VERSION 5.8 ;
BUSBITCHARS "[]" ;
DIVIDERCHAR "/" ;
UNITS
    DATABASE MICRONS 1000 ;
END UNITS

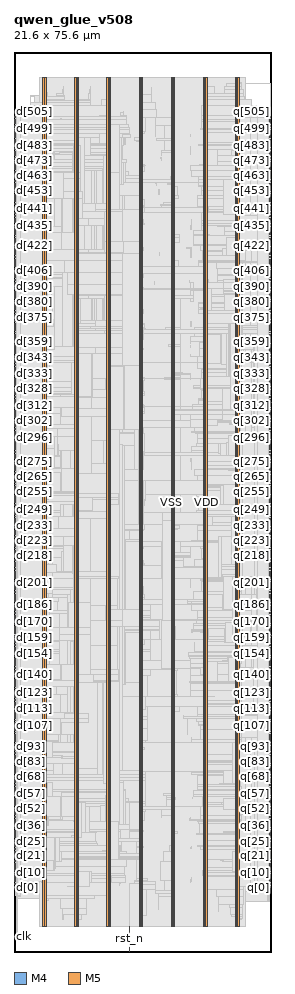
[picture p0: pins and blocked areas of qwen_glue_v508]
MACRO qwen_glue_v508
  FOREIGN qwen_glue_v508 0 0 ;
  CLASS BLOCK ;
  SIZE 21.6 BY 75.6 ;
  PIN clk
    DIRECTION INPUT ;
    USE SIGNAL ;
    PORT
      LAYER M4 ;
        RECT  0.054 1.296 0.138 1.32 ;
    END
    PORT
      LAYER M4 ;
        RECT  0.108 1.296 0.275 1.32 ;
    END
  END clk
  PIN d[0]
    DIRECTION INPUT ;
    USE SIGNAL ;
    PORT
      LAYER M4 ;
        RECT  0.054 5.424 0.138 5.448 ;
    END
  END d[0]
  PIN d[100]
    DIRECTION INPUT ;
    USE SIGNAL ;
    PORT
      LAYER M4 ;
        RECT  0.054 18.192 0.138 18.216 ;
    END
  END d[100]
  PIN d[101]
    DIRECTION INPUT ;
    USE SIGNAL ;
    PORT
      LAYER M4 ;
        RECT  0.054 18.288 0.138 18.312 ;
    END
  END d[101]
  PIN d[102]
    DIRECTION INPUT ;
    USE SIGNAL ;
    PORT
      LAYER M4 ;
        RECT  0.054 18.432 0.138 18.456 ;
    END
  END d[102]
  PIN d[103]
    DIRECTION INPUT ;
    USE SIGNAL ;
    PORT
      LAYER M4 ;
        RECT  0.054 18.576 0.138 18.6 ;
    END
  END d[103]
  PIN d[104]
    DIRECTION INPUT ;
    USE SIGNAL ;
    PORT
      LAYER M4 ;
        RECT  0.054 18.672 0.138 18.696 ;
    END
  END d[104]
  PIN d[105]
    DIRECTION INPUT ;
    USE SIGNAL ;
    PORT
      LAYER M4 ;
        RECT  0.054 18.816 0.138 18.84 ;
    END
  END d[105]
  PIN d[106]
    DIRECTION INPUT ;
    USE SIGNAL ;
    PORT
      LAYER M4 ;
        RECT  0.054 18.912 0.138 18.936 ;
    END
  END d[106]
  PIN d[107]
    DIRECTION INPUT ;
    USE SIGNAL ;
    PORT
      LAYER M4 ;
        RECT  0.054 19.056 0.138 19.08 ;
    END
  END d[107]
  PIN d[108]
    DIRECTION INPUT ;
    USE SIGNAL ;
    PORT
      LAYER M4 ;
        RECT  0.054 19.2 0.138 19.224 ;
    END
  END d[108]
  PIN d[109]
    DIRECTION INPUT ;
    USE SIGNAL ;
    PORT
      LAYER M4 ;
        RECT  0.054 19.296 0.138 19.32 ;
    END
  END d[109]
  PIN d[10]
    DIRECTION INPUT ;
    USE SIGNAL ;
    PORT
      LAYER M4 ;
        RECT  0.054 6.672 0.138 6.696 ;
    END
  END d[10]
  PIN d[110]
    DIRECTION INPUT ;
    USE SIGNAL ;
    PORT
      LAYER M4 ;
        RECT  0.054 19.44 0.138 19.464 ;
    END
  END d[110]
  PIN d[111]
    DIRECTION INPUT ;
    USE SIGNAL ;
    PORT
      LAYER M4 ;
        RECT  0.054 19.584 0.138 19.608 ;
    END
  END d[111]
  PIN d[112]
    DIRECTION INPUT ;
    USE SIGNAL ;
    PORT
      LAYER M4 ;
        RECT  0.054 19.68 0.138 19.704 ;
    END
  END d[112]
  PIN d[113]
    DIRECTION INPUT ;
    USE SIGNAL ;
    PORT
      LAYER M4 ;
        RECT  0.054 19.824 0.138 19.848 ;
    END
  END d[113]
  PIN d[114]
    DIRECTION INPUT ;
    USE SIGNAL ;
    PORT
      LAYER M4 ;
        RECT  0.054 19.968 0.138 19.992 ;
    END
  END d[114]
  PIN d[115]
    DIRECTION INPUT ;
    USE SIGNAL ;
    PORT
      LAYER M4 ;
        RECT  0.054 20.064 0.138 20.088 ;
    END
  END d[115]
  PIN d[116]
    DIRECTION INPUT ;
    USE SIGNAL ;
    PORT
      LAYER M4 ;
        RECT  0.054 20.208 0.138 20.232 ;
    END
  END d[116]
  PIN d[117]
    DIRECTION INPUT ;
    USE SIGNAL ;
    PORT
      LAYER M4 ;
        RECT  0.054 20.352 0.138 20.376 ;
    END
  END d[117]
  PIN d[118]
    DIRECTION INPUT ;
    USE SIGNAL ;
    PORT
      LAYER M4 ;
        RECT  0.054 20.448 0.138 20.472 ;
    END
  END d[118]
  PIN d[119]
    DIRECTION INPUT ;
    USE SIGNAL ;
    PORT
      LAYER M4 ;
        RECT  0.054 20.592 0.138 20.616 ;
    END
  END d[119]
  PIN d[11]
    DIRECTION INPUT ;
    USE SIGNAL ;
    PORT
      LAYER M4 ;
        RECT  0.054 6.816 0.138 6.84 ;
    END
  END d[11]
  PIN d[120]
    DIRECTION INPUT ;
    USE SIGNAL ;
    PORT
      LAYER M4 ;
        RECT  0.054 20.736 0.138 20.76 ;
    END
  END d[120]
  PIN d[121]
    DIRECTION INPUT ;
    USE SIGNAL ;
    PORT
      LAYER M4 ;
        RECT  0.054 20.832 0.138 20.856 ;
    END
  END d[121]
  PIN d[122]
    DIRECTION INPUT ;
    USE SIGNAL ;
    PORT
      LAYER M4 ;
        RECT  0.054 20.976 0.138 21 ;
    END
  END d[122]
  PIN d[123]
    DIRECTION INPUT ;
    USE SIGNAL ;
    PORT
      LAYER M4 ;
        RECT  0.054 21.12 0.138 21.144 ;
    END
  END d[123]
  PIN d[124]
    DIRECTION INPUT ;
    USE SIGNAL ;
    PORT
      LAYER M4 ;
        RECT  0.054 21.216 0.138 21.24 ;
    END
  END d[124]
  PIN d[125]
    DIRECTION INPUT ;
    USE SIGNAL ;
    PORT
      LAYER M4 ;
        RECT  0.054 21.36 0.138 21.384 ;
    END
  END d[125]
  PIN d[126]
    DIRECTION INPUT ;
    USE SIGNAL ;
    PORT
      LAYER M4 ;
        RECT  0.054 21.504 0.138 21.528 ;
    END
  END d[126]
  PIN d[127]
    DIRECTION INPUT ;
    USE SIGNAL ;
    PORT
      LAYER M4 ;
        RECT  0.054 21.6 0.138 21.624 ;
    END
  END d[127]
  PIN d[128]
    DIRECTION INPUT ;
    USE SIGNAL ;
    PORT
      LAYER M4 ;
        RECT  0.054 21.744 0.138 21.768 ;
    END
  END d[128]
  PIN d[129]
    DIRECTION INPUT ;
    USE SIGNAL ;
    PORT
      LAYER M4 ;
        RECT  0.054 21.888 0.138 21.912 ;
    END
  END d[129]
  PIN d[12]
    DIRECTION INPUT ;
    USE SIGNAL ;
    PORT
      LAYER M4 ;
        RECT  0.054 6.912 0.138 6.936 ;
    END
  END d[12]
  PIN d[130]
    DIRECTION INPUT ;
    USE SIGNAL ;
    PORT
      LAYER M4 ;
        RECT  0.054 21.984 0.138 22.008 ;
    END
  END d[130]
  PIN d[131]
    DIRECTION INPUT ;
    USE SIGNAL ;
    PORT
      LAYER M4 ;
        RECT  0.054 22.128 0.138 22.152 ;
    END
  END d[131]
  PIN d[132]
    DIRECTION INPUT ;
    USE SIGNAL ;
    PORT
      LAYER M4 ;
        RECT  0.054 22.272 0.138 22.296 ;
    END
  END d[132]
  PIN d[133]
    DIRECTION INPUT ;
    USE SIGNAL ;
    PORT
      LAYER M4 ;
        RECT  0.054 22.368 0.138 22.392 ;
    END
  END d[133]
  PIN d[134]
    DIRECTION INPUT ;
    USE SIGNAL ;
    PORT
      LAYER M4 ;
        RECT  0.054 22.512 0.138 22.536 ;
    END
  END d[134]
  PIN d[135]
    DIRECTION INPUT ;
    USE SIGNAL ;
    PORT
      LAYER M4 ;
        RECT  0.054 22.656 0.138 22.68 ;
    END
  END d[135]
  PIN d[136]
    DIRECTION INPUT ;
    USE SIGNAL ;
    PORT
      LAYER M4 ;
        RECT  0.054 22.752 0.138 22.776 ;
    END
  END d[136]
  PIN d[137]
    DIRECTION INPUT ;
    USE SIGNAL ;
    PORT
      LAYER M4 ;
        RECT  0.054 22.896 0.138 22.92 ;
    END
  END d[137]
  PIN d[138]
    DIRECTION INPUT ;
    USE SIGNAL ;
    PORT
      LAYER M4 ;
        RECT  0.054 23.04 0.138 23.064 ;
    END
  END d[138]
  PIN d[139]
    DIRECTION INPUT ;
    USE SIGNAL ;
    PORT
      LAYER M4 ;
        RECT  0.054 23.136 0.138 23.16 ;
    END
  END d[139]
  PIN d[13]
    DIRECTION INPUT ;
    USE SIGNAL ;
    PORT
      LAYER M4 ;
        RECT  0.054 7.056 0.138 7.08 ;
    END
  END d[13]
  PIN d[140]
    DIRECTION INPUT ;
    USE SIGNAL ;
    PORT
      LAYER M4 ;
        RECT  0.054 23.28 0.138 23.304 ;
    END
  END d[140]
  PIN d[141]
    DIRECTION INPUT ;
    USE SIGNAL ;
    PORT
      LAYER M4 ;
        RECT  0.054 23.424 0.138 23.448 ;
    END
  END d[141]
  PIN d[142]
    DIRECTION INPUT ;
    USE SIGNAL ;
    PORT
      LAYER M4 ;
        RECT  0.054 23.52 0.138 23.544 ;
    END
  END d[142]
  PIN d[143]
    DIRECTION INPUT ;
    USE SIGNAL ;
    PORT
      LAYER M4 ;
        RECT  0.054 23.664 0.138 23.688 ;
    END
  END d[143]
  PIN d[144]
    DIRECTION INPUT ;
    USE SIGNAL ;
    PORT
      LAYER M4 ;
        RECT  0.054 23.808 0.138 23.832 ;
    END
  END d[144]
  PIN d[145]
    DIRECTION INPUT ;
    USE SIGNAL ;
    PORT
      LAYER M4 ;
        RECT  0.054 23.904 0.138 23.928 ;
    END
  END d[145]
  PIN d[146]
    DIRECTION INPUT ;
    USE SIGNAL ;
    PORT
      LAYER M4 ;
        RECT  0.054 24.048 0.138 24.072 ;
    END
  END d[146]
  PIN d[147]
    DIRECTION INPUT ;
    USE SIGNAL ;
    PORT
      LAYER M4 ;
        RECT  0.054 24.192 0.138 24.216 ;
    END
  END d[147]
  PIN d[148]
    DIRECTION INPUT ;
    USE SIGNAL ;
    PORT
      LAYER M4 ;
        RECT  0.054 24.288 0.138 24.312 ;
    END
  END d[148]
  PIN d[149]
    DIRECTION INPUT ;
    USE SIGNAL ;
    PORT
      LAYER M4 ;
        RECT  0.054 24.432 0.138 24.456 ;
    END
  END d[149]
  PIN d[14]
    DIRECTION INPUT ;
    USE SIGNAL ;
    PORT
      LAYER M4 ;
        RECT  0.054 7.2 0.138 7.224 ;
    END
  END d[14]
  PIN d[150]
    DIRECTION INPUT ;
    USE SIGNAL ;
    PORT
      LAYER M4 ;
        RECT  0.054 24.576 0.138 24.6 ;
    END
  END d[150]
  PIN d[151]
    DIRECTION INPUT ;
    USE SIGNAL ;
    PORT
      LAYER M4 ;
        RECT  0.054 24.672 0.138 24.696 ;
    END
  END d[151]
  PIN d[152]
    DIRECTION INPUT ;
    USE SIGNAL ;
    PORT
      LAYER M4 ;
        RECT  0.054 24.816 0.138 24.84 ;
    END
  END d[152]
  PIN d[153]
    DIRECTION INPUT ;
    USE SIGNAL ;
    PORT
      LAYER M4 ;
        RECT  0.054 24.96 0.138 24.984 ;
    END
  END d[153]
  PIN d[154]
    DIRECTION INPUT ;
    USE SIGNAL ;
    PORT
      LAYER M4 ;
        RECT  0.054 25.056 0.138 25.08 ;
    END
  END d[154]
  PIN d[155]
    DIRECTION INPUT ;
    USE SIGNAL ;
    PORT
      LAYER M4 ;
        RECT  0.054 25.2 0.138 25.224 ;
    END
  END d[155]
  PIN d[156]
    DIRECTION INPUT ;
    USE SIGNAL ;
    PORT
      LAYER M4 ;
        RECT  0.054 25.344 0.138 25.368 ;
    END
  END d[156]
  PIN d[157]
    DIRECTION INPUT ;
    USE SIGNAL ;
    PORT
      LAYER M4 ;
        RECT  0.054 25.44 0.138 25.464 ;
    END
  END d[157]
  PIN d[158]
    DIRECTION INPUT ;
    USE SIGNAL ;
    PORT
      LAYER M4 ;
        RECT  0.054 25.584 0.138 25.608 ;
    END
  END d[158]
  PIN d[159]
    DIRECTION INPUT ;
    USE SIGNAL ;
    PORT
      LAYER M4 ;
        RECT  0.054 25.728 0.138 25.752 ;
    END
  END d[159]
  PIN d[15]
    DIRECTION INPUT ;
    USE SIGNAL ;
    PORT
      LAYER M4 ;
        RECT  0.054 7.296 0.138 7.32 ;
    END
  END d[15]
  PIN d[160]
    DIRECTION INPUT ;
    USE SIGNAL ;
    PORT
      LAYER M4 ;
        RECT  0.054 25.824 0.138 25.848 ;
    END
  END d[160]
  PIN d[161]
    DIRECTION INPUT ;
    USE SIGNAL ;
    PORT
      LAYER M4 ;
        RECT  0.054 25.968 0.138 25.992 ;
    END
  END d[161]
  PIN d[162]
    DIRECTION INPUT ;
    USE SIGNAL ;
    PORT
      LAYER M4 ;
        RECT  0.054 26.112 0.138 26.136 ;
    END
  END d[162]
  PIN d[163]
    DIRECTION INPUT ;
    USE SIGNAL ;
    PORT
      LAYER M4 ;
        RECT  0.054 26.208 0.138 26.232 ;
    END
  END d[163]
  PIN d[164]
    DIRECTION INPUT ;
    USE SIGNAL ;
    PORT
      LAYER M4 ;
        RECT  0.054 26.352 0.138 26.376 ;
    END
  END d[164]
  PIN d[165]
    DIRECTION INPUT ;
    USE SIGNAL ;
    PORT
      LAYER M4 ;
        RECT  0.054 26.496 0.138 26.52 ;
    END
  END d[165]
  PIN d[166]
    DIRECTION INPUT ;
    USE SIGNAL ;
    PORT
      LAYER M4 ;
        RECT  0.054 26.592 0.138 26.616 ;
    END
    PORT
      LAYER M4 ;
        RECT  0.025 26.592 0.108 26.616 ;
    END
  END d[166]
  PIN d[167]
    DIRECTION INPUT ;
    USE SIGNAL ;
    PORT
      LAYER M4 ;
        RECT  0.054 26.736 0.138 26.76 ;
    END
  END d[167]
  PIN d[168]
    DIRECTION INPUT ;
    USE SIGNAL ;
    PORT
      LAYER M4 ;
        RECT  0.054 26.88 0.138 26.904 ;
    END
  END d[168]
  PIN d[169]
    DIRECTION INPUT ;
    USE SIGNAL ;
    PORT
      LAYER M4 ;
        RECT  0.054 26.976 0.138 27 ;
    END
  END d[169]
  PIN d[16]
    DIRECTION INPUT ;
    USE SIGNAL ;
    PORT
      LAYER M4 ;
        RECT  0.054 7.44 0.138 7.464 ;
    END
  END d[16]
  PIN d[170]
    DIRECTION INPUT ;
    USE SIGNAL ;
    PORT
      LAYER M4 ;
        RECT  0.054 27.12 0.138 27.144 ;
    END
  END d[170]
  PIN d[171]
    DIRECTION INPUT ;
    USE SIGNAL ;
    PORT
      LAYER M4 ;
        RECT  0.054 27.264 0.138 27.288 ;
    END
  END d[171]
  PIN d[172]
    DIRECTION INPUT ;
    USE SIGNAL ;
    PORT
      LAYER M4 ;
        RECT  0.054 27.36 0.138 27.384 ;
    END
  END d[172]
  PIN d[173]
    DIRECTION INPUT ;
    USE SIGNAL ;
    PORT
      LAYER M4 ;
        RECT  0.054 27.504 0.138 27.528 ;
    END
  END d[173]
  PIN d[174]
    DIRECTION INPUT ;
    USE SIGNAL ;
    PORT
      LAYER M4 ;
        RECT  0.054 27.648 0.138 27.672 ;
    END
  END d[174]
  PIN d[175]
    DIRECTION INPUT ;
    USE SIGNAL ;
    PORT
      LAYER M4 ;
        RECT  0.054 27.744 0.138 27.768 ;
    END
  END d[175]
  PIN d[176]
    DIRECTION INPUT ;
    USE SIGNAL ;
    PORT
      LAYER M4 ;
        RECT  0.054 27.888 0.138 27.912 ;
    END
  END d[176]
  PIN d[177]
    DIRECTION INPUT ;
    USE SIGNAL ;
    PORT
      LAYER M4 ;
        RECT  0.054 28.032 0.138 28.056 ;
    END
  END d[177]
  PIN d[178]
    DIRECTION INPUT ;
    USE SIGNAL ;
    PORT
      LAYER M4 ;
        RECT  0.054 28.128 0.138 28.152 ;
    END
  END d[178]
  PIN d[179]
    DIRECTION INPUT ;
    USE SIGNAL ;
    PORT
      LAYER M4 ;
        RECT  0.054 28.272 0.138 28.296 ;
    END
  END d[179]
  PIN d[17]
    DIRECTION INPUT ;
    USE SIGNAL ;
    PORT
      LAYER M4 ;
        RECT  0.054 7.584 0.138 7.608 ;
    END
  END d[17]
  PIN d[180]
    DIRECTION INPUT ;
    USE SIGNAL ;
    PORT
      LAYER M4 ;
        RECT  0.054 28.416 0.138 28.44 ;
    END
  END d[180]
  PIN d[181]
    DIRECTION INPUT ;
    USE SIGNAL ;
    PORT
      LAYER M4 ;
        RECT  0.054 28.512 0.138 28.536 ;
    END
  END d[181]
  PIN d[182]
    DIRECTION INPUT ;
    USE SIGNAL ;
    PORT
      LAYER M4 ;
        RECT  0.054 28.656 0.138 28.68 ;
    END
  END d[182]
  PIN d[183]
    DIRECTION INPUT ;
    USE SIGNAL ;
    PORT
      LAYER M4 ;
        RECT  0.054 28.8 0.138 28.824 ;
    END
  END d[183]
  PIN d[184]
    DIRECTION INPUT ;
    USE SIGNAL ;
    PORT
      LAYER M4 ;
        RECT  0.054 28.896 0.138 28.92 ;
    END
  END d[184]
  PIN d[185]
    DIRECTION INPUT ;
    USE SIGNAL ;
    PORT
      LAYER M4 ;
        RECT  0.054 29.04 0.138 29.064 ;
    END
  END d[185]
  PIN d[186]
    DIRECTION INPUT ;
    USE SIGNAL ;
    PORT
      LAYER M4 ;
        RECT  0.054 29.184 0.138 29.208 ;
    END
  END d[186]
  PIN d[187]
    DIRECTION INPUT ;
    USE SIGNAL ;
    PORT
      LAYER M4 ;
        RECT  0.054 29.28 0.138 29.304 ;
    END
  END d[187]
  PIN d[188]
    DIRECTION INPUT ;
    USE SIGNAL ;
    PORT
      LAYER M4 ;
        RECT  0.054 29.424 0.138 29.448 ;
    END
  END d[188]
  PIN d[189]
    DIRECTION INPUT ;
    USE SIGNAL ;
    PORT
      LAYER M4 ;
        RECT  0.054 29.568 0.138 29.592 ;
    END
  END d[189]
  PIN d[18]
    DIRECTION INPUT ;
    USE SIGNAL ;
    PORT
      LAYER M4 ;
        RECT  0.054 7.68 0.138 7.704 ;
    END
  END d[18]
  PIN d[190]
    DIRECTION INPUT ;
    USE SIGNAL ;
    PORT
      LAYER M4 ;
        RECT  0.054 29.664 0.138 29.688 ;
    END
  END d[190]
  PIN d[191]
    DIRECTION INPUT ;
    USE SIGNAL ;
    PORT
      LAYER M4 ;
        RECT  0.054 29.808 0.138 29.832 ;
    END
  END d[191]
  PIN d[192]
    DIRECTION INPUT ;
    USE SIGNAL ;
    PORT
      LAYER M4 ;
        RECT  0.054 29.904 0.138 29.928 ;
    END
  END d[192]
  PIN d[193]
    DIRECTION INPUT ;
    USE SIGNAL ;
    PORT
      LAYER M4 ;
        RECT  0.054 30.048 0.138 30.072 ;
    END
  END d[193]
  PIN d[194]
    DIRECTION INPUT ;
    USE SIGNAL ;
    PORT
      LAYER M4 ;
        RECT  0.054 30.192 0.138 30.216 ;
    END
  END d[194]
  PIN d[195]
    DIRECTION INPUT ;
    USE SIGNAL ;
    PORT
      LAYER M4 ;
        RECT  0.054 30.288 0.138 30.312 ;
    END
  END d[195]
  PIN d[196]
    DIRECTION INPUT ;
    USE SIGNAL ;
    PORT
      LAYER M4 ;
        RECT  0.054 30.432 0.138 30.456 ;
    END
  END d[196]
  PIN d[197]
    DIRECTION INPUT ;
    USE SIGNAL ;
    PORT
      LAYER M4 ;
        RECT  0.054 30.576 0.138 30.6 ;
    END
  END d[197]
  PIN d[198]
    DIRECTION INPUT ;
    USE SIGNAL ;
    PORT
      LAYER M4 ;
        RECT  0.054 30.672 0.138 30.696 ;
    END
  END d[198]
  PIN d[199]
    DIRECTION INPUT ;
    USE SIGNAL ;
    PORT
      LAYER M4 ;
        RECT  0.054 30.816 0.138 30.84 ;
    END
  END d[199]
  PIN d[19]
    DIRECTION INPUT ;
    USE SIGNAL ;
    PORT
      LAYER M4 ;
        RECT  0.054 7.824 0.138 7.848 ;
    END
  END d[19]
  PIN d[1]
    DIRECTION INPUT ;
    USE SIGNAL ;
    PORT
      LAYER M4 ;
        RECT  0.054 5.52 0.138 5.544 ;
    END
  END d[1]
  PIN d[200]
    DIRECTION INPUT ;
    USE SIGNAL ;
    PORT
      LAYER M4 ;
        RECT  0.054 30.96 0.138 30.984 ;
    END
  END d[200]
  PIN d[201]
    DIRECTION INPUT ;
    USE SIGNAL ;
    PORT
      LAYER M4 ;
        RECT  0.054 31.056 0.138 31.08 ;
    END
  END d[201]
  PIN d[202]
    DIRECTION INPUT ;
    USE SIGNAL ;
    PORT
      LAYER M4 ;
        RECT  0.054 31.2 0.138 31.224 ;
    END
  END d[202]
  PIN d[203]
    DIRECTION INPUT ;
    USE SIGNAL ;
    PORT
      LAYER M4 ;
        RECT  0.054 31.344 0.138 31.368 ;
    END
  END d[203]
  PIN d[204]
    DIRECTION INPUT ;
    USE SIGNAL ;
    PORT
      LAYER M4 ;
        RECT  0.054 31.44 0.138 31.464 ;
    END
  END d[204]
  PIN d[205]
    DIRECTION INPUT ;
    USE SIGNAL ;
    PORT
      LAYER M4 ;
        RECT  0.054 31.584 0.138 31.608 ;
    END
  END d[205]
  PIN d[206]
    DIRECTION INPUT ;
    USE SIGNAL ;
    PORT
      LAYER M4 ;
        RECT  0.054 31.728 0.138 31.752 ;
    END
  END d[206]
  PIN d[207]
    DIRECTION INPUT ;
    USE SIGNAL ;
    PORT
      LAYER M4 ;
        RECT  0.054 31.824 0.138 31.848 ;
    END
  END d[207]
  PIN d[208]
    DIRECTION INPUT ;
    USE SIGNAL ;
    PORT
      LAYER M4 ;
        RECT  0.054 31.968 0.138 31.992 ;
    END
  END d[208]
  PIN d[209]
    DIRECTION INPUT ;
    USE SIGNAL ;
    PORT
      LAYER M4 ;
        RECT  0.054 32.112 0.138 32.136 ;
    END
  END d[209]
  PIN d[20]
    DIRECTION INPUT ;
    USE SIGNAL ;
    PORT
      LAYER M4 ;
        RECT  0.054 7.968 0.138 7.992 ;
    END
  END d[20]
  PIN d[210]
    DIRECTION INPUT ;
    USE SIGNAL ;
    PORT
      LAYER M4 ;
        RECT  0.054 32.208 0.138 32.232 ;
    END
  END d[210]
  PIN d[211]
    DIRECTION INPUT ;
    USE SIGNAL ;
    PORT
      LAYER M4 ;
        RECT  0.054 32.352 0.138 32.376 ;
    END
  END d[211]
  PIN d[212]
    DIRECTION INPUT ;
    USE SIGNAL ;
    PORT
      LAYER M4 ;
        RECT  0.054 32.496 0.138 32.52 ;
    END
  END d[212]
  PIN d[213]
    DIRECTION INPUT ;
    USE SIGNAL ;
    PORT
      LAYER M4 ;
        RECT  0.054 32.592 0.138 32.616 ;
    END
  END d[213]
  PIN d[214]
    DIRECTION INPUT ;
    USE SIGNAL ;
    PORT
      LAYER M4 ;
        RECT  0.054 32.736 0.138 32.76 ;
    END
  END d[214]
  PIN d[215]
    DIRECTION INPUT ;
    USE SIGNAL ;
    PORT
      LAYER M4 ;
        RECT  0.054 32.88 0.138 32.904 ;
    END
  END d[215]
  PIN d[216]
    DIRECTION INPUT ;
    USE SIGNAL ;
    PORT
      LAYER M4 ;
        RECT  0.054 32.976 0.138 33 ;
    END
  END d[216]
  PIN d[217]
    DIRECTION INPUT ;
    USE SIGNAL ;
    PORT
      LAYER M4 ;
        RECT  0.054 33.12 0.138 33.144 ;
    END
  END d[217]
  PIN d[218]
    DIRECTION INPUT ;
    USE SIGNAL ;
    PORT
      LAYER M4 ;
        RECT  0.054 33.264 0.138 33.288 ;
    END
  END d[218]
  PIN d[219]
    DIRECTION INPUT ;
    USE SIGNAL ;
    PORT
      LAYER M4 ;
        RECT  0.054 33.36 0.138 33.384 ;
    END
  END d[219]
  PIN d[21]
    DIRECTION INPUT ;
    USE SIGNAL ;
    PORT
      LAYER M4 ;
        RECT  0.054 8.064 0.138 8.088 ;
    END
  END d[21]
  PIN d[220]
    DIRECTION INPUT ;
    USE SIGNAL ;
    PORT
      LAYER M4 ;
        RECT  0.054 33.504 0.138 33.528 ;
    END
    PORT
      LAYER M4 ;
        RECT  0.025 33.504 0.108 33.528 ;
    END
  END d[220]
  PIN d[221]
    DIRECTION INPUT ;
    USE SIGNAL ;
    PORT
      LAYER M4 ;
        RECT  0.054 33.648 0.138 33.672 ;
    END
  END d[221]
  PIN d[222]
    DIRECTION INPUT ;
    USE SIGNAL ;
    PORT
      LAYER M4 ;
        RECT  0.054 33.744 0.138 33.768 ;
    END
  END d[222]
  PIN d[223]
    DIRECTION INPUT ;
    USE SIGNAL ;
    PORT
      LAYER M4 ;
        RECT  0.054 33.888 0.138 33.912 ;
    END
  END d[223]
  PIN d[224]
    DIRECTION INPUT ;
    USE SIGNAL ;
    PORT
      LAYER M4 ;
        RECT  0.054 34.032 0.138 34.056 ;
    END
  END d[224]
  PIN d[225]
    DIRECTION INPUT ;
    USE SIGNAL ;
    PORT
      LAYER M4 ;
        RECT  0.054 34.128 0.138 34.152 ;
    END
  END d[225]
  PIN d[226]
    DIRECTION INPUT ;
    USE SIGNAL ;
    PORT
      LAYER M4 ;
        RECT  0.054 34.272 0.138 34.296 ;
    END
  END d[226]
  PIN d[227]
    DIRECTION INPUT ;
    USE SIGNAL ;
    PORT
      LAYER M4 ;
        RECT  0.054 34.416 0.138 34.44 ;
    END
  END d[227]
  PIN d[228]
    DIRECTION INPUT ;
    USE SIGNAL ;
    PORT
      LAYER M4 ;
        RECT  0.054 34.512 0.138 34.536 ;
    END
  END d[228]
  PIN d[229]
    DIRECTION INPUT ;
    USE SIGNAL ;
    PORT
      LAYER M4 ;
        RECT  0.054 34.656 0.138 34.68 ;
    END
  END d[229]
  PIN d[22]
    DIRECTION INPUT ;
    USE SIGNAL ;
    PORT
      LAYER M4 ;
        RECT  0.054 8.208 0.138 8.232 ;
    END
  END d[22]
  PIN d[230]
    DIRECTION INPUT ;
    USE SIGNAL ;
    PORT
      LAYER M4 ;
        RECT  0.054 34.8 0.138 34.824 ;
    END
  END d[230]
  PIN d[231]
    DIRECTION INPUT ;
    USE SIGNAL ;
    PORT
      LAYER M4 ;
        RECT  0.054 34.896 0.138 34.92 ;
    END
  END d[231]
  PIN d[232]
    DIRECTION INPUT ;
    USE SIGNAL ;
    PORT
      LAYER M4 ;
        RECT  0.054 35.04 0.138 35.064 ;
    END
  END d[232]
  PIN d[233]
    DIRECTION INPUT ;
    USE SIGNAL ;
    PORT
      LAYER M4 ;
        RECT  0.054 35.184 0.138 35.208 ;
    END
  END d[233]
  PIN d[234]
    DIRECTION INPUT ;
    USE SIGNAL ;
    PORT
      LAYER M4 ;
        RECT  0.054 35.28 0.138 35.304 ;
    END
  END d[234]
  PIN d[235]
    DIRECTION INPUT ;
    USE SIGNAL ;
    PORT
      LAYER M4 ;
        RECT  0.054 35.424 0.138 35.448 ;
    END
  END d[235]
  PIN d[236]
    DIRECTION INPUT ;
    USE SIGNAL ;
    PORT
      LAYER M4 ;
        RECT  0.054 35.568 0.138 35.592 ;
    END
  END d[236]
  PIN d[237]
    DIRECTION INPUT ;
    USE SIGNAL ;
    PORT
      LAYER M4 ;
        RECT  0.054 35.664 0.138 35.688 ;
    END
  END d[237]
  PIN d[238]
    DIRECTION INPUT ;
    USE SIGNAL ;
    PORT
      LAYER M4 ;
        RECT  0.054 35.808 0.138 35.832 ;
    END
  END d[238]
  PIN d[239]
    DIRECTION INPUT ;
    USE SIGNAL ;
    PORT
      LAYER M4 ;
        RECT  0.054 35.952 0.138 35.976 ;
    END
  END d[239]
  PIN d[23]
    DIRECTION INPUT ;
    USE SIGNAL ;
    PORT
      LAYER M4 ;
        RECT  0.054 8.304 0.138 8.328 ;
    END
  END d[23]
  PIN d[240]
    DIRECTION INPUT ;
    USE SIGNAL ;
    PORT
      LAYER M4 ;
        RECT  0.054 36.048 0.138 36.072 ;
    END
  END d[240]
  PIN d[241]
    DIRECTION INPUT ;
    USE SIGNAL ;
    PORT
      LAYER M4 ;
        RECT  0.054 36.192 0.138 36.216 ;
    END
  END d[241]
  PIN d[242]
    DIRECTION INPUT ;
    USE SIGNAL ;
    PORT
      LAYER M4 ;
        RECT  0.054 36.336 0.138 36.36 ;
    END
  END d[242]
  PIN d[243]
    DIRECTION INPUT ;
    USE SIGNAL ;
    PORT
      LAYER M4 ;
        RECT  0.054 36.432 0.138 36.456 ;
    END
  END d[243]
  PIN d[244]
    DIRECTION INPUT ;
    USE SIGNAL ;
    PORT
      LAYER M4 ;
        RECT  0.054 36.576 0.138 36.6 ;
    END
  END d[244]
  PIN d[245]
    DIRECTION INPUT ;
    USE SIGNAL ;
    PORT
      LAYER M4 ;
        RECT  0.054 36.72 0.138 36.744 ;
    END
  END d[245]
  PIN d[246]
    DIRECTION INPUT ;
    USE SIGNAL ;
    PORT
      LAYER M4 ;
        RECT  0.054 36.816 0.138 36.84 ;
    END
  END d[246]
  PIN d[247]
    DIRECTION INPUT ;
    USE SIGNAL ;
    PORT
      LAYER M4 ;
        RECT  0.054 36.96 0.138 36.984 ;
    END
  END d[247]
  PIN d[248]
    DIRECTION INPUT ;
    USE SIGNAL ;
    PORT
      LAYER M4 ;
        RECT  0.054 37.104 0.138 37.128 ;
    END
  END d[248]
  PIN d[249]
    DIRECTION INPUT ;
    USE SIGNAL ;
    PORT
      LAYER M4 ;
        RECT  0.054 37.2 0.138 37.224 ;
    END
  END d[249]
  PIN d[24]
    DIRECTION INPUT ;
    USE SIGNAL ;
    PORT
      LAYER M4 ;
        RECT  0.054 8.448 0.138 8.472 ;
    END
  END d[24]
  PIN d[250]
    DIRECTION INPUT ;
    USE SIGNAL ;
    PORT
      LAYER M4 ;
        RECT  0.054 37.344 0.138 37.368 ;
    END
  END d[250]
  PIN d[251]
    DIRECTION INPUT ;
    USE SIGNAL ;
    PORT
      LAYER M4 ;
        RECT  0.054 37.488 0.138 37.512 ;
    END
  END d[251]
  PIN d[252]
    DIRECTION INPUT ;
    USE SIGNAL ;
    PORT
      LAYER M4 ;
        RECT  0.054 37.584 0.138 37.608 ;
    END
  END d[252]
  PIN d[253]
    DIRECTION INPUT ;
    USE SIGNAL ;
    PORT
      LAYER M4 ;
        RECT  0.054 37.728 0.138 37.752 ;
    END
  END d[253]
  PIN d[254]
    DIRECTION INPUT ;
    USE SIGNAL ;
    PORT
      LAYER M4 ;
        RECT  0.054 37.872 0.138 37.896 ;
    END
  END d[254]
  PIN d[255]
    DIRECTION INPUT ;
    USE SIGNAL ;
    PORT
      LAYER M4 ;
        RECT  0.054 37.968 0.138 37.992 ;
    END
  END d[255]
  PIN d[256]
    DIRECTION INPUT ;
    USE SIGNAL ;
    PORT
      LAYER M4 ;
        RECT  0.054 38.112 0.138 38.136 ;
    END
  END d[256]
  PIN d[257]
    DIRECTION INPUT ;
    USE SIGNAL ;
    PORT
      LAYER M4 ;
        RECT  0.054 38.256 0.138 38.28 ;
    END
  END d[257]
  PIN d[258]
    DIRECTION INPUT ;
    USE SIGNAL ;
    PORT
      LAYER M4 ;
        RECT  0.054 38.352 0.138 38.376 ;
    END
  END d[258]
  PIN d[259]
    DIRECTION INPUT ;
    USE SIGNAL ;
    PORT
      LAYER M4 ;
        RECT  0.054 38.496 0.138 38.52 ;
    END
  END d[259]
  PIN d[25]
    DIRECTION INPUT ;
    USE SIGNAL ;
    PORT
      LAYER M4 ;
        RECT  0.054 8.592 0.138 8.616 ;
    END
  END d[25]
  PIN d[260]
    DIRECTION INPUT ;
    USE SIGNAL ;
    PORT
      LAYER M4 ;
        RECT  0.054 38.64 0.138 38.664 ;
    END
  END d[260]
  PIN d[261]
    DIRECTION INPUT ;
    USE SIGNAL ;
    PORT
      LAYER M4 ;
        RECT  0.054 38.736 0.138 38.76 ;
    END
  END d[261]
  PIN d[262]
    DIRECTION INPUT ;
    USE SIGNAL ;
    PORT
      LAYER M4 ;
        RECT  0.054 38.88 0.138 38.904 ;
    END
  END d[262]
  PIN d[263]
    DIRECTION INPUT ;
    USE SIGNAL ;
    PORT
      LAYER M4 ;
        RECT  0.054 39.024 0.138 39.048 ;
    END
  END d[263]
  PIN d[264]
    DIRECTION INPUT ;
    USE SIGNAL ;
    PORT
      LAYER M4 ;
        RECT  0.054 39.12 0.138 39.144 ;
    END
  END d[264]
  PIN d[265]
    DIRECTION INPUT ;
    USE SIGNAL ;
    PORT
      LAYER M4 ;
        RECT  0.054 39.264 0.138 39.288 ;
    END
  END d[265]
  PIN d[266]
    DIRECTION INPUT ;
    USE SIGNAL ;
    PORT
      LAYER M4 ;
        RECT  0.054 39.408 0.138 39.432 ;
    END
  END d[266]
  PIN d[267]
    DIRECTION INPUT ;
    USE SIGNAL ;
    PORT
      LAYER M4 ;
        RECT  0.054 39.504 0.138 39.528 ;
    END
  END d[267]
  PIN d[268]
    DIRECTION INPUT ;
    USE SIGNAL ;
    PORT
      LAYER M4 ;
        RECT  0.054 39.648 0.138 39.672 ;
    END
  END d[268]
  PIN d[269]
    DIRECTION INPUT ;
    USE SIGNAL ;
    PORT
      LAYER M4 ;
        RECT  0.054 39.792 0.138 39.816 ;
    END
  END d[269]
  PIN d[26]
    DIRECTION INPUT ;
    USE SIGNAL ;
    PORT
      LAYER M4 ;
        RECT  0.054 8.688 0.138 8.712 ;
    END
  END d[26]
  PIN d[270]
    DIRECTION INPUT ;
    USE SIGNAL ;
    PORT
      LAYER M4 ;
        RECT  0.054 39.888 0.138 39.912 ;
    END
  END d[270]
  PIN d[271]
    DIRECTION INPUT ;
    USE SIGNAL ;
    PORT
      LAYER M4 ;
        RECT  0.054 40.032 0.138 40.056 ;
    END
  END d[271]
  PIN d[272]
    DIRECTION INPUT ;
    USE SIGNAL ;
    PORT
      LAYER M4 ;
        RECT  0.054 40.176 0.138 40.2 ;
    END
  END d[272]
  PIN d[273]
    DIRECTION INPUT ;
    USE SIGNAL ;
    PORT
      LAYER M4 ;
        RECT  0.054 40.272 0.138 40.296 ;
    END
  END d[273]
  PIN d[274]
    DIRECTION INPUT ;
    USE SIGNAL ;
    PORT
      LAYER M4 ;
        RECT  0.054 40.416 0.138 40.44 ;
    END
  END d[274]
  PIN d[275]
    DIRECTION INPUT ;
    USE SIGNAL ;
    PORT
      LAYER M4 ;
        RECT  0.054 40.512 0.138 40.536 ;
    END
  END d[275]
  PIN d[276]
    DIRECTION INPUT ;
    USE SIGNAL ;
    PORT
      LAYER M4 ;
        RECT  0.054 40.656 0.138 40.68 ;
    END
  END d[276]
  PIN d[277]
    DIRECTION INPUT ;
    USE SIGNAL ;
    PORT
      LAYER M4 ;
        RECT  0.054 40.8 0.138 40.824 ;
    END
  END d[277]
  PIN d[278]
    DIRECTION INPUT ;
    USE SIGNAL ;
    PORT
      LAYER M4 ;
        RECT  0.054 40.896 0.138 40.92 ;
    END
  END d[278]
  PIN d[279]
    DIRECTION INPUT ;
    USE SIGNAL ;
    PORT
      LAYER M4 ;
        RECT  0.054 41.04 0.138 41.064 ;
    END
  END d[279]
  PIN d[27]
    DIRECTION INPUT ;
    USE SIGNAL ;
    PORT
      LAYER M4 ;
        RECT  0.054 8.832 0.138 8.856 ;
    END
  END d[27]
  PIN d[280]
    DIRECTION INPUT ;
    USE SIGNAL ;
    PORT
      LAYER M4 ;
        RECT  0.054 41.184 0.138 41.208 ;
    END
  END d[280]
  PIN d[281]
    DIRECTION INPUT ;
    USE SIGNAL ;
    PORT
      LAYER M4 ;
        RECT  0.054 41.28 0.138 41.304 ;
    END
  END d[281]
  PIN d[282]
    DIRECTION INPUT ;
    USE SIGNAL ;
    PORT
      LAYER M4 ;
        RECT  0.054 41.424 0.138 41.448 ;
    END
  END d[282]
  PIN d[283]
    DIRECTION INPUT ;
    USE SIGNAL ;
    PORT
      LAYER M4 ;
        RECT  0.054 41.568 0.138 41.592 ;
    END
  END d[283]
  PIN d[284]
    DIRECTION INPUT ;
    USE SIGNAL ;
    PORT
      LAYER M4 ;
        RECT  0.054 41.664 0.138 41.688 ;
    END
  END d[284]
  PIN d[285]
    DIRECTION INPUT ;
    USE SIGNAL ;
    PORT
      LAYER M4 ;
        RECT  0.054 41.808 0.138 41.832 ;
    END
  END d[285]
  PIN d[286]
    DIRECTION INPUT ;
    USE SIGNAL ;
    PORT
      LAYER M4 ;
        RECT  0.054 41.952 0.138 41.976 ;
    END
  END d[286]
  PIN d[287]
    DIRECTION INPUT ;
    USE SIGNAL ;
    PORT
      LAYER M4 ;
        RECT  0.054 42.048 0.138 42.072 ;
    END
  END d[287]
  PIN d[288]
    DIRECTION INPUT ;
    USE SIGNAL ;
    PORT
      LAYER M4 ;
        RECT  0.054 42.192 0.138 42.216 ;
    END
  END d[288]
  PIN d[289]
    DIRECTION INPUT ;
    USE SIGNAL ;
    PORT
      LAYER M4 ;
        RECT  0.054 42.336 0.138 42.36 ;
    END
  END d[289]
  PIN d[28]
    DIRECTION INPUT ;
    USE SIGNAL ;
    PORT
      LAYER M4 ;
        RECT  0.054 8.976 0.138 9 ;
    END
  END d[28]
  PIN d[290]
    DIRECTION INPUT ;
    USE SIGNAL ;
    PORT
      LAYER M4 ;
        RECT  0.054 42.432 0.138 42.456 ;
    END
  END d[290]
  PIN d[291]
    DIRECTION INPUT ;
    USE SIGNAL ;
    PORT
      LAYER M4 ;
        RECT  0.054 42.576 0.138 42.6 ;
    END
  END d[291]
  PIN d[292]
    DIRECTION INPUT ;
    USE SIGNAL ;
    PORT
      LAYER M4 ;
        RECT  0.054 42.72 0.138 42.744 ;
    END
  END d[292]
  PIN d[293]
    DIRECTION INPUT ;
    USE SIGNAL ;
    PORT
      LAYER M4 ;
        RECT  0.054 42.816 0.138 42.84 ;
    END
  END d[293]
  PIN d[294]
    DIRECTION INPUT ;
    USE SIGNAL ;
    PORT
      LAYER M4 ;
        RECT  0.054 42.96 0.138 42.984 ;
    END
  END d[294]
  PIN d[295]
    DIRECTION INPUT ;
    USE SIGNAL ;
    PORT
      LAYER M4 ;
        RECT  0.054 43.104 0.138 43.128 ;
    END
  END d[295]
  PIN d[296]
    DIRECTION INPUT ;
    USE SIGNAL ;
    PORT
      LAYER M4 ;
        RECT  0.054 43.2 0.138 43.224 ;
    END
  END d[296]
  PIN d[297]
    DIRECTION INPUT ;
    USE SIGNAL ;
    PORT
      LAYER M4 ;
        RECT  0.054 43.344 0.138 43.368 ;
    END
  END d[297]
  PIN d[298]
    DIRECTION INPUT ;
    USE SIGNAL ;
    PORT
      LAYER M4 ;
        RECT  0.054 43.488 0.138 43.512 ;
    END
  END d[298]
  PIN d[299]
    DIRECTION INPUT ;
    USE SIGNAL ;
    PORT
      LAYER M4 ;
        RECT  0.054 43.584 0.138 43.608 ;
    END
  END d[299]
  PIN d[29]
    DIRECTION INPUT ;
    USE SIGNAL ;
    PORT
      LAYER M4 ;
        RECT  0.054 9.072 0.138 9.096 ;
    END
  END d[29]
  PIN d[2]
    DIRECTION INPUT ;
    USE SIGNAL ;
    PORT
      LAYER M4 ;
        RECT  0.054 5.664 0.138 5.688 ;
    END
  END d[2]
  PIN d[300]
    DIRECTION INPUT ;
    USE SIGNAL ;
    PORT
      LAYER M4 ;
        RECT  0.054 43.728 0.138 43.752 ;
    END
  END d[300]
  PIN d[301]
    DIRECTION INPUT ;
    USE SIGNAL ;
    PORT
      LAYER M4 ;
        RECT  0.054 43.872 0.138 43.896 ;
    END
  END d[301]
  PIN d[302]
    DIRECTION INPUT ;
    USE SIGNAL ;
    PORT
      LAYER M4 ;
        RECT  0.054 43.968 0.138 43.992 ;
    END
  END d[302]
  PIN d[303]
    DIRECTION INPUT ;
    USE SIGNAL ;
    PORT
      LAYER M4 ;
        RECT  0.054 44.112 0.138 44.136 ;
    END
  END d[303]
  PIN d[304]
    DIRECTION INPUT ;
    USE SIGNAL ;
    PORT
      LAYER M4 ;
        RECT  0.054 44.256 0.138 44.28 ;
    END
  END d[304]
  PIN d[305]
    DIRECTION INPUT ;
    USE SIGNAL ;
    PORT
      LAYER M4 ;
        RECT  0.054 44.352 0.138 44.376 ;
    END
  END d[305]
  PIN d[306]
    DIRECTION INPUT ;
    USE SIGNAL ;
    PORT
      LAYER M4 ;
        RECT  0.054 44.496 0.138 44.52 ;
    END
  END d[306]
  PIN d[307]
    DIRECTION INPUT ;
    USE SIGNAL ;
    PORT
      LAYER M4 ;
        RECT  0.054 44.64 0.138 44.664 ;
    END
  END d[307]
  PIN d[308]
    DIRECTION INPUT ;
    USE SIGNAL ;
    PORT
      LAYER M4 ;
        RECT  0.054 44.736 0.138 44.76 ;
    END
  END d[308]
  PIN d[309]
    DIRECTION INPUT ;
    USE SIGNAL ;
    PORT
      LAYER M4 ;
        RECT  0.054 44.88 0.138 44.904 ;
    END
  END d[309]
  PIN d[30]
    DIRECTION INPUT ;
    USE SIGNAL ;
    PORT
      LAYER M4 ;
        RECT  0.054 9.216 0.138 9.24 ;
    END
  END d[30]
  PIN d[310]
    DIRECTION INPUT ;
    USE SIGNAL ;
    PORT
      LAYER M4 ;
        RECT  0.054 45.024 0.138 45.048 ;
    END
  END d[310]
  PIN d[311]
    DIRECTION INPUT ;
    USE SIGNAL ;
    PORT
      LAYER M4 ;
        RECT  0.054 45.12 0.138 45.144 ;
    END
  END d[311]
  PIN d[312]
    DIRECTION INPUT ;
    USE SIGNAL ;
    PORT
      LAYER M4 ;
        RECT  0.054 45.264 0.138 45.288 ;
    END
  END d[312]
  PIN d[313]
    DIRECTION INPUT ;
    USE SIGNAL ;
    PORT
      LAYER M4 ;
        RECT  0.054 45.408 0.138 45.432 ;
    END
  END d[313]
  PIN d[314]
    DIRECTION INPUT ;
    USE SIGNAL ;
    PORT
      LAYER M4 ;
        RECT  0.054 45.504 0.138 45.528 ;
    END
  END d[314]
  PIN d[315]
    DIRECTION INPUT ;
    USE SIGNAL ;
    PORT
      LAYER M4 ;
        RECT  0.054 45.648 0.138 45.672 ;
    END
  END d[315]
  PIN d[316]
    DIRECTION INPUT ;
    USE SIGNAL ;
    PORT
      LAYER M4 ;
        RECT  0.054 45.792 0.138 45.816 ;
    END
  END d[316]
  PIN d[317]
    DIRECTION INPUT ;
    USE SIGNAL ;
    PORT
      LAYER M4 ;
        RECT  0.054 45.888 0.138 45.912 ;
    END
  END d[317]
  PIN d[318]
    DIRECTION INPUT ;
    USE SIGNAL ;
    PORT
      LAYER M4 ;
        RECT  0.054 46.032 0.138 46.056 ;
    END
  END d[318]
  PIN d[319]
    DIRECTION INPUT ;
    USE SIGNAL ;
    PORT
      LAYER M4 ;
        RECT  0.054 46.176 0.138 46.2 ;
    END
  END d[319]
  PIN d[31]
    DIRECTION INPUT ;
    USE SIGNAL ;
    PORT
      LAYER M4 ;
        RECT  0.054 9.36 0.138 9.384 ;
    END
  END d[31]
  PIN d[320]
    DIRECTION INPUT ;
    USE SIGNAL ;
    PORT
      LAYER M4 ;
        RECT  0.054 46.272 0.138 46.296 ;
    END
  END d[320]
  PIN d[321]
    DIRECTION INPUT ;
    USE SIGNAL ;
    PORT
      LAYER M4 ;
        RECT  0.054 46.416 0.138 46.44 ;
    END
  END d[321]
  PIN d[322]
    DIRECTION INPUT ;
    USE SIGNAL ;
    PORT
      LAYER M4 ;
        RECT  0.054 46.56 0.138 46.584 ;
    END
  END d[322]
  PIN d[323]
    DIRECTION INPUT ;
    USE SIGNAL ;
    PORT
      LAYER M4 ;
        RECT  0.054 46.656 0.138 46.68 ;
    END
  END d[323]
  PIN d[324]
    DIRECTION INPUT ;
    USE SIGNAL ;
    PORT
      LAYER M4 ;
        RECT  0.054 46.8 0.138 46.824 ;
    END
  END d[324]
  PIN d[325]
    DIRECTION INPUT ;
    USE SIGNAL ;
    PORT
      LAYER M4 ;
        RECT  0.054 46.944 0.138 46.968 ;
    END
  END d[325]
  PIN d[326]
    DIRECTION INPUT ;
    USE SIGNAL ;
    PORT
      LAYER M4 ;
        RECT  0.054 47.04 0.138 47.064 ;
    END
  END d[326]
  PIN d[327]
    DIRECTION INPUT ;
    USE SIGNAL ;
    PORT
      LAYER M4 ;
        RECT  0.054 47.184 0.138 47.208 ;
    END
  END d[327]
  PIN d[328]
    DIRECTION INPUT ;
    USE SIGNAL ;
    PORT
      LAYER M4 ;
        RECT  0.054 47.328 0.138 47.352 ;
    END
  END d[328]
  PIN d[329]
    DIRECTION INPUT ;
    USE SIGNAL ;
    PORT
      LAYER M4 ;
        RECT  0.054 47.424 0.138 47.448 ;
    END
  END d[329]
  PIN d[32]
    DIRECTION INPUT ;
    USE SIGNAL ;
    PORT
      LAYER M4 ;
        RECT  0.054 9.456 0.138 9.48 ;
    END
  END d[32]
  PIN d[330]
    DIRECTION INPUT ;
    USE SIGNAL ;
    PORT
      LAYER M4 ;
        RECT  0.054 47.568 0.138 47.592 ;
    END
  END d[330]
  PIN d[331]
    DIRECTION INPUT ;
    USE SIGNAL ;
    PORT
      LAYER M4 ;
        RECT  0.054 47.712 0.138 47.736 ;
    END
  END d[331]
  PIN d[332]
    DIRECTION INPUT ;
    USE SIGNAL ;
    PORT
      LAYER M4 ;
        RECT  0.054 47.808 0.138 47.832 ;
    END
  END d[332]
  PIN d[333]
    DIRECTION INPUT ;
    USE SIGNAL ;
    PORT
      LAYER M4 ;
        RECT  0.054 47.952 0.138 47.976 ;
    END
  END d[333]
  PIN d[334]
    DIRECTION INPUT ;
    USE SIGNAL ;
    PORT
      LAYER M4 ;
        RECT  0.054 48.096 0.138 48.12 ;
    END
  END d[334]
  PIN d[335]
    DIRECTION INPUT ;
    USE SIGNAL ;
    PORT
      LAYER M4 ;
        RECT  0.054 48.192 0.138 48.216 ;
    END
  END d[335]
  PIN d[336]
    DIRECTION INPUT ;
    USE SIGNAL ;
    PORT
      LAYER M4 ;
        RECT  0.054 48.336 0.138 48.36 ;
    END
  END d[336]
  PIN d[337]
    DIRECTION INPUT ;
    USE SIGNAL ;
    PORT
      LAYER M4 ;
        RECT  0.054 48.48 0.138 48.504 ;
    END
  END d[337]
  PIN d[338]
    DIRECTION INPUT ;
    USE SIGNAL ;
    PORT
      LAYER M4 ;
        RECT  0.054 48.576 0.138 48.6 ;
    END
  END d[338]
  PIN d[339]
    DIRECTION INPUT ;
    USE SIGNAL ;
    PORT
      LAYER M4 ;
        RECT  0.054 48.72 0.138 48.744 ;
    END
  END d[339]
  PIN d[33]
    DIRECTION INPUT ;
    USE SIGNAL ;
    PORT
      LAYER M4 ;
        RECT  0.054 9.6 0.138 9.624 ;
    END
  END d[33]
  PIN d[340]
    DIRECTION INPUT ;
    USE SIGNAL ;
    PORT
      LAYER M4 ;
        RECT  0.054 48.864 0.138 48.888 ;
    END
  END d[340]
  PIN d[341]
    DIRECTION INPUT ;
    USE SIGNAL ;
    PORT
      LAYER M4 ;
        RECT  0.054 48.96 0.138 48.984 ;
    END
  END d[341]
  PIN d[342]
    DIRECTION INPUT ;
    USE SIGNAL ;
    PORT
      LAYER M4 ;
        RECT  0.054 49.104 0.138 49.128 ;
    END
  END d[342]
  PIN d[343]
    DIRECTION INPUT ;
    USE SIGNAL ;
    PORT
      LAYER M4 ;
        RECT  0.054 49.248 0.138 49.272 ;
    END
  END d[343]
  PIN d[344]
    DIRECTION INPUT ;
    USE SIGNAL ;
    PORT
      LAYER M4 ;
        RECT  0.054 49.344 0.138 49.368 ;
    END
  END d[344]
  PIN d[345]
    DIRECTION INPUT ;
    USE SIGNAL ;
    PORT
      LAYER M4 ;
        RECT  0.054 49.488 0.138 49.512 ;
    END
  END d[345]
  PIN d[346]
    DIRECTION INPUT ;
    USE SIGNAL ;
    PORT
      LAYER M4 ;
        RECT  0.054 49.632 0.138 49.656 ;
    END
  END d[346]
  PIN d[347]
    DIRECTION INPUT ;
    USE SIGNAL ;
    PORT
      LAYER M4 ;
        RECT  0.054 49.728 0.138 49.752 ;
    END
  END d[347]
  PIN d[348]
    DIRECTION INPUT ;
    USE SIGNAL ;
    PORT
      LAYER M4 ;
        RECT  0.054 49.872 0.138 49.896 ;
    END
  END d[348]
  PIN d[349]
    DIRECTION INPUT ;
    USE SIGNAL ;
    PORT
      LAYER M4 ;
        RECT  0.054 50.016 0.138 50.04 ;
    END
  END d[349]
  PIN d[34]
    DIRECTION INPUT ;
    USE SIGNAL ;
    PORT
      LAYER M4 ;
        RECT  0.054 9.744 0.138 9.768 ;
    END
  END d[34]
  PIN d[350]
    DIRECTION INPUT ;
    USE SIGNAL ;
    PORT
      LAYER M4 ;
        RECT  0.054 50.112 0.138 50.136 ;
    END
  END d[350]
  PIN d[351]
    DIRECTION INPUT ;
    USE SIGNAL ;
    PORT
      LAYER M4 ;
        RECT  0.054 50.256 0.138 50.28 ;
    END
  END d[351]
  PIN d[352]
    DIRECTION INPUT ;
    USE SIGNAL ;
    PORT
      LAYER M4 ;
        RECT  0.054 50.4 0.138 50.424 ;
    END
  END d[352]
  PIN d[353]
    DIRECTION INPUT ;
    USE SIGNAL ;
    PORT
      LAYER M4 ;
        RECT  0.054 50.496 0.138 50.52 ;
    END
  END d[353]
  PIN d[354]
    DIRECTION INPUT ;
    USE SIGNAL ;
    PORT
      LAYER M4 ;
        RECT  0.054 50.64 0.138 50.664 ;
    END
  END d[354]
  PIN d[355]
    DIRECTION INPUT ;
    USE SIGNAL ;
    PORT
      LAYER M4 ;
        RECT  0.054 50.784 0.138 50.808 ;
    END
  END d[355]
  PIN d[356]
    DIRECTION INPUT ;
    USE SIGNAL ;
    PORT
      LAYER M4 ;
        RECT  0.054 50.88 0.138 50.904 ;
    END
  END d[356]
  PIN d[357]
    DIRECTION INPUT ;
    USE SIGNAL ;
    PORT
      LAYER M4 ;
        RECT  0.054 51.024 0.138 51.048 ;
    END
  END d[357]
  PIN d[358]
    DIRECTION INPUT ;
    USE SIGNAL ;
    PORT
      LAYER M4 ;
        RECT  0.054 51.168 0.138 51.192 ;
    END
  END d[358]
  PIN d[359]
    DIRECTION INPUT ;
    USE SIGNAL ;
    PORT
      LAYER M4 ;
        RECT  0.054 51.264 0.138 51.288 ;
    END
  END d[359]
  PIN d[35]
    DIRECTION INPUT ;
    USE SIGNAL ;
    PORT
      LAYER M4 ;
        RECT  0.054 9.84 0.138 9.864 ;
    END
  END d[35]
  PIN d[360]
    DIRECTION INPUT ;
    USE SIGNAL ;
    PORT
      LAYER M4 ;
        RECT  0.054 51.408 0.138 51.432 ;
    END
  END d[360]
  PIN d[361]
    DIRECTION INPUT ;
    USE SIGNAL ;
    PORT
      LAYER M4 ;
        RECT  0.054 51.504 0.138 51.528 ;
    END
  END d[361]
  PIN d[362]
    DIRECTION INPUT ;
    USE SIGNAL ;
    PORT
      LAYER M4 ;
        RECT  0.054 51.648 0.138 51.672 ;
    END
  END d[362]
  PIN d[363]
    DIRECTION INPUT ;
    USE SIGNAL ;
    PORT
      LAYER M4 ;
        RECT  0.054 51.792 0.138 51.816 ;
    END
  END d[363]
  PIN d[364]
    DIRECTION INPUT ;
    USE SIGNAL ;
    PORT
      LAYER M4 ;
        RECT  0.054 51.888 0.138 51.912 ;
    END
  END d[364]
  PIN d[365]
    DIRECTION INPUT ;
    USE SIGNAL ;
    PORT
      LAYER M4 ;
        RECT  0.054 52.032 0.138 52.056 ;
    END
  END d[365]
  PIN d[366]
    DIRECTION INPUT ;
    USE SIGNAL ;
    PORT
      LAYER M4 ;
        RECT  0.054 52.176 0.138 52.2 ;
    END
  END d[366]
  PIN d[367]
    DIRECTION INPUT ;
    USE SIGNAL ;
    PORT
      LAYER M4 ;
        RECT  0.054 52.272 0.138 52.296 ;
    END
  END d[367]
  PIN d[368]
    DIRECTION INPUT ;
    USE SIGNAL ;
    PORT
      LAYER M4 ;
        RECT  0.054 52.416 0.138 52.44 ;
    END
  END d[368]
  PIN d[369]
    DIRECTION INPUT ;
    USE SIGNAL ;
    PORT
      LAYER M4 ;
        RECT  0.054 52.56 0.138 52.584 ;
    END
  END d[369]
  PIN d[36]
    DIRECTION INPUT ;
    USE SIGNAL ;
    PORT
      LAYER M4 ;
        RECT  0.054 9.984 0.138 10.008 ;
    END
  END d[36]
  PIN d[370]
    DIRECTION INPUT ;
    USE SIGNAL ;
    PORT
      LAYER M4 ;
        RECT  0.054 52.656 0.138 52.68 ;
    END
  END d[370]
  PIN d[371]
    DIRECTION INPUT ;
    USE SIGNAL ;
    PORT
      LAYER M4 ;
        RECT  0.054 52.8 0.138 52.824 ;
    END
  END d[371]
  PIN d[372]
    DIRECTION INPUT ;
    USE SIGNAL ;
    PORT
      LAYER M4 ;
        RECT  0.054 52.944 0.138 52.968 ;
    END
  END d[372]
  PIN d[373]
    DIRECTION INPUT ;
    USE SIGNAL ;
    PORT
      LAYER M4 ;
        RECT  0.054 53.04 0.138 53.064 ;
    END
  END d[373]
  PIN d[374]
    DIRECTION INPUT ;
    USE SIGNAL ;
    PORT
      LAYER M4 ;
        RECT  0.054 53.184 0.138 53.208 ;
    END
  END d[374]
  PIN d[375]
    DIRECTION INPUT ;
    USE SIGNAL ;
    PORT
      LAYER M4 ;
        RECT  0.054 53.328 0.138 53.352 ;
    END
  END d[375]
  PIN d[376]
    DIRECTION INPUT ;
    USE SIGNAL ;
    PORT
      LAYER M4 ;
        RECT  0.054 53.424 0.138 53.448 ;
    END
  END d[376]
  PIN d[377]
    DIRECTION INPUT ;
    USE SIGNAL ;
    PORT
      LAYER M4 ;
        RECT  0.054 53.568 0.138 53.592 ;
    END
  END d[377]
  PIN d[378]
    DIRECTION INPUT ;
    USE SIGNAL ;
    PORT
      LAYER M4 ;
        RECT  0.054 53.712 0.138 53.736 ;
    END
  END d[378]
  PIN d[379]
    DIRECTION INPUT ;
    USE SIGNAL ;
    PORT
      LAYER M4 ;
        RECT  0.054 53.808 0.138 53.832 ;
    END
  END d[379]
  PIN d[37]
    DIRECTION INPUT ;
    USE SIGNAL ;
    PORT
      LAYER M4 ;
        RECT  0.054 10.128 0.138 10.152 ;
    END
  END d[37]
  PIN d[380]
    DIRECTION INPUT ;
    USE SIGNAL ;
    PORT
      LAYER M4 ;
        RECT  0.054 53.952 0.138 53.976 ;
    END
  END d[380]
  PIN d[381]
    DIRECTION INPUT ;
    USE SIGNAL ;
    PORT
      LAYER M4 ;
        RECT  0.054 54.096 0.138 54.12 ;
    END
  END d[381]
  PIN d[382]
    DIRECTION INPUT ;
    USE SIGNAL ;
    PORT
      LAYER M4 ;
        RECT  0.054 54.192 0.138 54.216 ;
    END
  END d[382]
  PIN d[383]
    DIRECTION INPUT ;
    USE SIGNAL ;
    PORT
      LAYER M4 ;
        RECT  0.054 54.336 0.138 54.36 ;
    END
  END d[383]
  PIN d[384]
    DIRECTION INPUT ;
    USE SIGNAL ;
    PORT
      LAYER M4 ;
        RECT  0.054 54.48 0.138 54.504 ;
    END
  END d[384]
  PIN d[385]
    DIRECTION INPUT ;
    USE SIGNAL ;
    PORT
      LAYER M4 ;
        RECT  0.054 54.576 0.138 54.6 ;
    END
  END d[385]
  PIN d[386]
    DIRECTION INPUT ;
    USE SIGNAL ;
    PORT
      LAYER M4 ;
        RECT  0.054 54.72 0.138 54.744 ;
    END
  END d[386]
  PIN d[387]
    DIRECTION INPUT ;
    USE SIGNAL ;
    PORT
      LAYER M4 ;
        RECT  0.054 54.864 0.138 54.888 ;
    END
  END d[387]
  PIN d[388]
    DIRECTION INPUT ;
    USE SIGNAL ;
    PORT
      LAYER M4 ;
        RECT  0.054 54.96 0.138 54.984 ;
    END
  END d[388]
  PIN d[389]
    DIRECTION INPUT ;
    USE SIGNAL ;
    PORT
      LAYER M4 ;
        RECT  0.054 55.104 0.138 55.128 ;
    END
  END d[389]
  PIN d[38]
    DIRECTION INPUT ;
    USE SIGNAL ;
    PORT
      LAYER M4 ;
        RECT  0.054 10.224 0.138 10.248 ;
    END
  END d[38]
  PIN d[390]
    DIRECTION INPUT ;
    USE SIGNAL ;
    PORT
      LAYER M4 ;
        RECT  0.054 55.248 0.138 55.272 ;
    END
  END d[390]
  PIN d[391]
    DIRECTION INPUT ;
    USE SIGNAL ;
    PORT
      LAYER M4 ;
        RECT  0.054 55.344 0.138 55.368 ;
    END
  END d[391]
  PIN d[392]
    DIRECTION INPUT ;
    USE SIGNAL ;
    PORT
      LAYER M4 ;
        RECT  0.054 55.488 0.138 55.512 ;
    END
  END d[392]
  PIN d[393]
    DIRECTION INPUT ;
    USE SIGNAL ;
    PORT
      LAYER M4 ;
        RECT  0.054 55.632 0.138 55.656 ;
    END
  END d[393]
  PIN d[394]
    DIRECTION INPUT ;
    USE SIGNAL ;
    PORT
      LAYER M4 ;
        RECT  0.054 55.728 0.138 55.752 ;
    END
  END d[394]
  PIN d[395]
    DIRECTION INPUT ;
    USE SIGNAL ;
    PORT
      LAYER M4 ;
        RECT  0.054 55.872 0.138 55.896 ;
    END
  END d[395]
  PIN d[396]
    DIRECTION INPUT ;
    USE SIGNAL ;
    PORT
      LAYER M4 ;
        RECT  0.054 56.016 0.138 56.04 ;
    END
  END d[396]
  PIN d[397]
    DIRECTION INPUT ;
    USE SIGNAL ;
    PORT
      LAYER M4 ;
        RECT  0.054 56.112 0.138 56.136 ;
    END
  END d[397]
  PIN d[398]
    DIRECTION INPUT ;
    USE SIGNAL ;
    PORT
      LAYER M4 ;
        RECT  0.054 56.256 0.138 56.28 ;
    END
  END d[398]
  PIN d[399]
    DIRECTION INPUT ;
    USE SIGNAL ;
    PORT
      LAYER M4 ;
        RECT  0.054 56.4 0.138 56.424 ;
    END
  END d[399]
  PIN d[39]
    DIRECTION INPUT ;
    USE SIGNAL ;
    PORT
      LAYER M4 ;
        RECT  0.054 10.368 0.138 10.392 ;
    END
  END d[39]
  PIN d[3]
    DIRECTION INPUT ;
    USE SIGNAL ;
    PORT
      LAYER M4 ;
        RECT  0.054 5.76 0.138 5.784 ;
    END
  END d[3]
  PIN d[400]
    DIRECTION INPUT ;
    USE SIGNAL ;
    PORT
      LAYER M4 ;
        RECT  0.054 56.496 0.138 56.52 ;
    END
  END d[400]
  PIN d[401]
    DIRECTION INPUT ;
    USE SIGNAL ;
    PORT
      LAYER M4 ;
        RECT  0.054 56.64 0.138 56.664 ;
    END
  END d[401]
  PIN d[402]
    DIRECTION INPUT ;
    USE SIGNAL ;
    PORT
      LAYER M4 ;
        RECT  0.054 56.784 0.138 56.808 ;
    END
  END d[402]
  PIN d[403]
    DIRECTION INPUT ;
    USE SIGNAL ;
    PORT
      LAYER M4 ;
        RECT  0.054 56.88 0.138 56.904 ;
    END
  END d[403]
  PIN d[404]
    DIRECTION INPUT ;
    USE SIGNAL ;
    PORT
      LAYER M4 ;
        RECT  0.054 57.024 0.138 57.048 ;
    END
  END d[404]
  PIN d[405]
    DIRECTION INPUT ;
    USE SIGNAL ;
    PORT
      LAYER M4 ;
        RECT  0.054 57.168 0.138 57.192 ;
    END
  END d[405]
  PIN d[406]
    DIRECTION INPUT ;
    USE SIGNAL ;
    PORT
      LAYER M4 ;
        RECT  0.054 57.264 0.138 57.288 ;
    END
  END d[406]
  PIN d[407]
    DIRECTION INPUT ;
    USE SIGNAL ;
    PORT
      LAYER M4 ;
        RECT  0.054 57.408 0.138 57.432 ;
    END
  END d[407]
  PIN d[408]
    DIRECTION INPUT ;
    USE SIGNAL ;
    PORT
      LAYER M4 ;
        RECT  0.054 57.552 0.138 57.576 ;
    END
  END d[408]
  PIN d[409]
    DIRECTION INPUT ;
    USE SIGNAL ;
    PORT
      LAYER M4 ;
        RECT  0.054 57.648 0.138 57.672 ;
    END
  END d[409]
  PIN d[40]
    DIRECTION INPUT ;
    USE SIGNAL ;
    PORT
      LAYER M4 ;
        RECT  0.054 10.512 0.138 10.536 ;
    END
  END d[40]
  PIN d[410]
    DIRECTION INPUT ;
    USE SIGNAL ;
    PORT
      LAYER M4 ;
        RECT  0.054 57.792 0.138 57.816 ;
    END
  END d[410]
  PIN d[411]
    DIRECTION INPUT ;
    USE SIGNAL ;
    PORT
      LAYER M4 ;
        RECT  0.054 57.936 0.138 57.96 ;
    END
  END d[411]
  PIN d[412]
    DIRECTION INPUT ;
    USE SIGNAL ;
    PORT
      LAYER M4 ;
        RECT  0.054 58.032 0.138 58.056 ;
    END
  END d[412]
  PIN d[413]
    DIRECTION INPUT ;
    USE SIGNAL ;
    PORT
      LAYER M4 ;
        RECT  0.054 58.176 0.138 58.2 ;
    END
  END d[413]
  PIN d[414]
    DIRECTION INPUT ;
    USE SIGNAL ;
    PORT
      LAYER M4 ;
        RECT  0.054 58.32 0.138 58.344 ;
    END
  END d[414]
  PIN d[415]
    DIRECTION INPUT ;
    USE SIGNAL ;
    PORT
      LAYER M4 ;
        RECT  0.054 58.416 0.138 58.44 ;
    END
  END d[415]
  PIN d[416]
    DIRECTION INPUT ;
    USE SIGNAL ;
    PORT
      LAYER M4 ;
        RECT  0.054 58.56 0.138 58.584 ;
    END
  END d[416]
  PIN d[417]
    DIRECTION INPUT ;
    USE SIGNAL ;
    PORT
      LAYER M4 ;
        RECT  0.054 58.704 0.138 58.728 ;
    END
  END d[417]
  PIN d[418]
    DIRECTION INPUT ;
    USE SIGNAL ;
    PORT
      LAYER M4 ;
        RECT  0.054 58.8 0.138 58.824 ;
    END
  END d[418]
  PIN d[419]
    DIRECTION INPUT ;
    USE SIGNAL ;
    PORT
      LAYER M4 ;
        RECT  0.054 58.944 0.138 58.968 ;
    END
  END d[419]
  PIN d[41]
    DIRECTION INPUT ;
    USE SIGNAL ;
    PORT
      LAYER M4 ;
        RECT  0.054 10.608 0.138 10.632 ;
    END
  END d[41]
  PIN d[420]
    DIRECTION INPUT ;
    USE SIGNAL ;
    PORT
      LAYER M4 ;
        RECT  0.054 59.088 0.138 59.112 ;
    END
  END d[420]
  PIN d[421]
    DIRECTION INPUT ;
    USE SIGNAL ;
    PORT
      LAYER M4 ;
        RECT  0.054 59.184 0.138 59.208 ;
    END
  END d[421]
  PIN d[422]
    DIRECTION INPUT ;
    USE SIGNAL ;
    PORT
      LAYER M4 ;
        RECT  0.054 59.328 0.138 59.352 ;
    END
  END d[422]
  PIN d[423]
    DIRECTION INPUT ;
    USE SIGNAL ;
    PORT
      LAYER M4 ;
        RECT  0.054 59.472 0.138 59.496 ;
    END
  END d[423]
  PIN d[424]
    DIRECTION INPUT ;
    USE SIGNAL ;
    PORT
      LAYER M4 ;
        RECT  0.054 59.568 0.138 59.592 ;
    END
  END d[424]
  PIN d[425]
    DIRECTION INPUT ;
    USE SIGNAL ;
    PORT
      LAYER M4 ;
        RECT  0.054 59.712 0.138 59.736 ;
    END
  END d[425]
  PIN d[426]
    DIRECTION INPUT ;
    USE SIGNAL ;
    PORT
      LAYER M4 ;
        RECT  0.054 59.856 0.138 59.88 ;
    END
  END d[426]
  PIN d[427]
    DIRECTION INPUT ;
    USE SIGNAL ;
    PORT
      LAYER M4 ;
        RECT  0.054 59.952 0.138 59.976 ;
    END
  END d[427]
  PIN d[428]
    DIRECTION INPUT ;
    USE SIGNAL ;
    PORT
      LAYER M4 ;
        RECT  0.054 60.096 0.138 60.12 ;
    END
  END d[428]
  PIN d[429]
    DIRECTION INPUT ;
    USE SIGNAL ;
    PORT
      LAYER M4 ;
        RECT  0.054 60.24 0.138 60.264 ;
    END
  END d[429]
  PIN d[42]
    DIRECTION INPUT ;
    USE SIGNAL ;
    PORT
      LAYER M4 ;
        RECT  0.054 10.752 0.138 10.776 ;
    END
  END d[42]
  PIN d[430]
    DIRECTION INPUT ;
    USE SIGNAL ;
    PORT
      LAYER M4 ;
        RECT  0.054 60.336 0.138 60.36 ;
    END
  END d[430]
  PIN d[431]
    DIRECTION INPUT ;
    USE SIGNAL ;
    PORT
      LAYER M4 ;
        RECT  0.054 60.48 0.138 60.504 ;
    END
  END d[431]
  PIN d[432]
    DIRECTION INPUT ;
    USE SIGNAL ;
    PORT
      LAYER M4 ;
        RECT  0.054 60.624 0.138 60.648 ;
    END
  END d[432]
  PIN d[433]
    DIRECTION INPUT ;
    USE SIGNAL ;
    PORT
      LAYER M4 ;
        RECT  0.054 60.72 0.138 60.744 ;
    END
  END d[433]
  PIN d[434]
    DIRECTION INPUT ;
    USE SIGNAL ;
    PORT
      LAYER M4 ;
        RECT  0.054 60.864 0.138 60.888 ;
    END
  END d[434]
  PIN d[435]
    DIRECTION INPUT ;
    USE SIGNAL ;
    PORT
      LAYER M4 ;
        RECT  0.054 61.008 0.138 61.032 ;
    END
  END d[435]
  PIN d[436]
    DIRECTION INPUT ;
    USE SIGNAL ;
    PORT
      LAYER M4 ;
        RECT  0.054 61.104 0.138 61.128 ;
    END
  END d[436]
  PIN d[437]
    DIRECTION INPUT ;
    USE SIGNAL ;
    PORT
      LAYER M4 ;
        RECT  0.054 61.248 0.138 61.272 ;
    END
  END d[437]
  PIN d[438]
    DIRECTION INPUT ;
    USE SIGNAL ;
    PORT
      LAYER M4 ;
        RECT  0.054 61.392 0.138 61.416 ;
    END
  END d[438]
  PIN d[439]
    DIRECTION INPUT ;
    USE SIGNAL ;
    PORT
      LAYER M4 ;
        RECT  0.054 61.488 0.138 61.512 ;
    END
  END d[439]
  PIN d[43]
    DIRECTION INPUT ;
    USE SIGNAL ;
    PORT
      LAYER M4 ;
        RECT  0.054 10.896 0.138 10.92 ;
    END
  END d[43]
  PIN d[440]
    DIRECTION INPUT ;
    USE SIGNAL ;
    PORT
      LAYER M4 ;
        RECT  0.054 61.632 0.138 61.656 ;
    END
  END d[440]
  PIN d[441]
    DIRECTION INPUT ;
    USE SIGNAL ;
    PORT
      LAYER M4 ;
        RECT  0.054 61.776 0.138 61.8 ;
    END
  END d[441]
  PIN d[442]
    DIRECTION INPUT ;
    USE SIGNAL ;
    PORT
      LAYER M4 ;
        RECT  0.054 61.872 0.138 61.896 ;
    END
  END d[442]
  PIN d[443]
    DIRECTION INPUT ;
    USE SIGNAL ;
    PORT
      LAYER M4 ;
        RECT  0.054 62.016 0.138 62.04 ;
    END
  END d[443]
  PIN d[444]
    DIRECTION INPUT ;
    USE SIGNAL ;
    PORT
      LAYER M4 ;
        RECT  0.054 62.112 0.138 62.136 ;
    END
  END d[444]
  PIN d[445]
    DIRECTION INPUT ;
    USE SIGNAL ;
    PORT
      LAYER M4 ;
        RECT  0.054 62.256 0.138 62.28 ;
    END
  END d[445]
  PIN d[446]
    DIRECTION INPUT ;
    USE SIGNAL ;
    PORT
      LAYER M4 ;
        RECT  0.054 62.4 0.138 62.424 ;
    END
  END d[446]
  PIN d[447]
    DIRECTION INPUT ;
    USE SIGNAL ;
    PORT
      LAYER M4 ;
        RECT  0.054 62.496 0.138 62.52 ;
    END
  END d[447]
  PIN d[448]
    DIRECTION INPUT ;
    USE SIGNAL ;
    PORT
      LAYER M4 ;
        RECT  0.054 62.64 0.138 62.664 ;
    END
  END d[448]
  PIN d[449]
    DIRECTION INPUT ;
    USE SIGNAL ;
    PORT
      LAYER M4 ;
        RECT  0.054 62.784 0.138 62.808 ;
    END
  END d[449]
  PIN d[44]
    DIRECTION INPUT ;
    USE SIGNAL ;
    PORT
      LAYER M4 ;
        RECT  0.054 10.992 0.138 11.016 ;
    END
  END d[44]
  PIN d[450]
    DIRECTION INPUT ;
    USE SIGNAL ;
    PORT
      LAYER M4 ;
        RECT  0.054 62.88 0.138 62.904 ;
    END
  END d[450]
  PIN d[451]
    DIRECTION INPUT ;
    USE SIGNAL ;
    PORT
      LAYER M4 ;
        RECT  0.054 63.024 0.138 63.048 ;
    END
  END d[451]
  PIN d[452]
    DIRECTION INPUT ;
    USE SIGNAL ;
    PORT
      LAYER M4 ;
        RECT  0.054 63.168 0.138 63.192 ;
    END
  END d[452]
  PIN d[453]
    DIRECTION INPUT ;
    USE SIGNAL ;
    PORT
      LAYER M4 ;
        RECT  0.054 63.264 0.138 63.288 ;
    END
  END d[453]
  PIN d[454]
    DIRECTION INPUT ;
    USE SIGNAL ;
    PORT
      LAYER M4 ;
        RECT  0.054 63.408 0.138 63.432 ;
    END
  END d[454]
  PIN d[455]
    DIRECTION INPUT ;
    USE SIGNAL ;
    PORT
      LAYER M4 ;
        RECT  0.054 63.552 0.138 63.576 ;
    END
  END d[455]
  PIN d[456]
    DIRECTION INPUT ;
    USE SIGNAL ;
    PORT
      LAYER M4 ;
        RECT  0.054 63.648 0.138 63.672 ;
    END
  END d[456]
  PIN d[457]
    DIRECTION INPUT ;
    USE SIGNAL ;
    PORT
      LAYER M4 ;
        RECT  0.054 63.792 0.138 63.816 ;
    END
    PORT
      LAYER M4 ;
        RECT  0.025 63.792 0.108 63.816 ;
    END
  END d[457]
  PIN d[458]
    DIRECTION INPUT ;
    USE SIGNAL ;
    PORT
      LAYER M4 ;
        RECT  0.054 63.936 0.138 63.96 ;
    END
  END d[458]
  PIN d[459]
    DIRECTION INPUT ;
    USE SIGNAL ;
    PORT
      LAYER M4 ;
        RECT  0.054 64.032 0.138 64.056 ;
    END
  END d[459]
  PIN d[45]
    DIRECTION INPUT ;
    USE SIGNAL ;
    PORT
      LAYER M4 ;
        RECT  0.054 11.136 0.138 11.16 ;
    END
  END d[45]
  PIN d[460]
    DIRECTION INPUT ;
    USE SIGNAL ;
    PORT
      LAYER M4 ;
        RECT  0.054 64.176 0.138 64.2 ;
    END
  END d[460]
  PIN d[461]
    DIRECTION INPUT ;
    USE SIGNAL ;
    PORT
      LAYER M4 ;
        RECT  0.054 64.32 0.138 64.344 ;
    END
  END d[461]
  PIN d[462]
    DIRECTION INPUT ;
    USE SIGNAL ;
    PORT
      LAYER M4 ;
        RECT  0.054 64.416 0.138 64.44 ;
    END
  END d[462]
  PIN d[463]
    DIRECTION INPUT ;
    USE SIGNAL ;
    PORT
      LAYER M4 ;
        RECT  0.054 64.56 0.138 64.584 ;
    END
  END d[463]
  PIN d[464]
    DIRECTION INPUT ;
    USE SIGNAL ;
    PORT
      LAYER M4 ;
        RECT  0.054 64.704 0.138 64.728 ;
    END
  END d[464]
  PIN d[465]
    DIRECTION INPUT ;
    USE SIGNAL ;
    PORT
      LAYER M4 ;
        RECT  0.054 64.8 0.138 64.824 ;
    END
  END d[465]
  PIN d[466]
    DIRECTION INPUT ;
    USE SIGNAL ;
    PORT
      LAYER M4 ;
        RECT  0.054 64.944 0.138 64.968 ;
    END
  END d[466]
  PIN d[467]
    DIRECTION INPUT ;
    USE SIGNAL ;
    PORT
      LAYER M4 ;
        RECT  0.054 65.088 0.138 65.112 ;
    END
  END d[467]
  PIN d[468]
    DIRECTION INPUT ;
    USE SIGNAL ;
    PORT
      LAYER M4 ;
        RECT  0.054 65.184 0.138 65.208 ;
    END
  END d[468]
  PIN d[469]
    DIRECTION INPUT ;
    USE SIGNAL ;
    PORT
      LAYER M4 ;
        RECT  0.054 65.328 0.138 65.352 ;
    END
  END d[469]
  PIN d[46]
    DIRECTION INPUT ;
    USE SIGNAL ;
    PORT
      LAYER M4 ;
        RECT  0.054 11.28 0.138 11.304 ;
    END
  END d[46]
  PIN d[470]
    DIRECTION INPUT ;
    USE SIGNAL ;
    PORT
      LAYER M4 ;
        RECT  0.054 65.472 0.138 65.496 ;
    END
  END d[470]
  PIN d[471]
    DIRECTION INPUT ;
    USE SIGNAL ;
    PORT
      LAYER M4 ;
        RECT  0.054 65.568 0.138 65.592 ;
    END
  END d[471]
  PIN d[472]
    DIRECTION INPUT ;
    USE SIGNAL ;
    PORT
      LAYER M4 ;
        RECT  0.054 65.712 0.138 65.736 ;
    END
  END d[472]
  PIN d[473]
    DIRECTION INPUT ;
    USE SIGNAL ;
    PORT
      LAYER M4 ;
        RECT  0.054 65.856 0.138 65.88 ;
    END
  END d[473]
  PIN d[474]
    DIRECTION INPUT ;
    USE SIGNAL ;
    PORT
      LAYER M4 ;
        RECT  0.054 65.952 0.138 65.976 ;
    END
  END d[474]
  PIN d[475]
    DIRECTION INPUT ;
    USE SIGNAL ;
    PORT
      LAYER M4 ;
        RECT  0.054 66.096 0.138 66.12 ;
    END
  END d[475]
  PIN d[476]
    DIRECTION INPUT ;
    USE SIGNAL ;
    PORT
      LAYER M4 ;
        RECT  0.054 66.24 0.138 66.264 ;
    END
  END d[476]
  PIN d[477]
    DIRECTION INPUT ;
    USE SIGNAL ;
    PORT
      LAYER M4 ;
        RECT  0.054 66.336 0.138 66.36 ;
    END
  END d[477]
  PIN d[478]
    DIRECTION INPUT ;
    USE SIGNAL ;
    PORT
      LAYER M4 ;
        RECT  0.054 66.48 0.138 66.504 ;
    END
  END d[478]
  PIN d[479]
    DIRECTION INPUT ;
    USE SIGNAL ;
    PORT
      LAYER M4 ;
        RECT  0.054 66.624 0.138 66.648 ;
    END
  END d[479]
  PIN d[47]
    DIRECTION INPUT ;
    USE SIGNAL ;
    PORT
      LAYER M4 ;
        RECT  0.054 11.376 0.138 11.4 ;
    END
  END d[47]
  PIN d[480]
    DIRECTION INPUT ;
    USE SIGNAL ;
    PORT
      LAYER M4 ;
        RECT  0.054 66.72 0.138 66.744 ;
    END
  END d[480]
  PIN d[481]
    DIRECTION INPUT ;
    USE SIGNAL ;
    PORT
      LAYER M4 ;
        RECT  0.054 66.864 0.138 66.888 ;
    END
  END d[481]
  PIN d[482]
    DIRECTION INPUT ;
    USE SIGNAL ;
    PORT
      LAYER M4 ;
        RECT  0.054 67.008 0.138 67.032 ;
    END
  END d[482]
  PIN d[483]
    DIRECTION INPUT ;
    USE SIGNAL ;
    PORT
      LAYER M4 ;
        RECT  0.054 67.104 0.138 67.128 ;
    END
  END d[483]
  PIN d[484]
    DIRECTION INPUT ;
    USE SIGNAL ;
    PORT
      LAYER M4 ;
        RECT  0.054 67.248 0.138 67.272 ;
    END
  END d[484]
  PIN d[485]
    DIRECTION INPUT ;
    USE SIGNAL ;
    PORT
      LAYER M4 ;
        RECT  0.054 67.392 0.138 67.416 ;
    END
  END d[485]
  PIN d[486]
    DIRECTION INPUT ;
    USE SIGNAL ;
    PORT
      LAYER M4 ;
        RECT  0.054 67.488 0.138 67.512 ;
    END
  END d[486]
  PIN d[487]
    DIRECTION INPUT ;
    USE SIGNAL ;
    PORT
      LAYER M4 ;
        RECT  0.054 67.632 0.138 67.656 ;
    END
  END d[487]
  PIN d[488]
    DIRECTION INPUT ;
    USE SIGNAL ;
    PORT
      LAYER M4 ;
        RECT  0.054 67.776 0.138 67.8 ;
    END
  END d[488]
  PIN d[489]
    DIRECTION INPUT ;
    USE SIGNAL ;
    PORT
      LAYER M4 ;
        RECT  0.054 67.872 0.138 67.896 ;
    END
  END d[489]
  PIN d[48]
    DIRECTION INPUT ;
    USE SIGNAL ;
    PORT
      LAYER M4 ;
        RECT  0.054 11.52 0.138 11.544 ;
    END
  END d[48]
  PIN d[490]
    DIRECTION INPUT ;
    USE SIGNAL ;
    PORT
      LAYER M4 ;
        RECT  0.054 68.016 0.138 68.04 ;
    END
  END d[490]
  PIN d[491]
    DIRECTION INPUT ;
    USE SIGNAL ;
    PORT
      LAYER M4 ;
        RECT  0.054 68.16 0.138 68.184 ;
    END
  END d[491]
  PIN d[492]
    DIRECTION INPUT ;
    USE SIGNAL ;
    PORT
      LAYER M4 ;
        RECT  0.054 68.256 0.138 68.28 ;
    END
  END d[492]
  PIN d[493]
    DIRECTION INPUT ;
    USE SIGNAL ;
    PORT
      LAYER M4 ;
        RECT  0.054 68.4 0.138 68.424 ;
    END
  END d[493]
  PIN d[494]
    DIRECTION INPUT ;
    USE SIGNAL ;
    PORT
      LAYER M4 ;
        RECT  0.054 68.544 0.138 68.568 ;
    END
  END d[494]
  PIN d[495]
    DIRECTION INPUT ;
    USE SIGNAL ;
    PORT
      LAYER M4 ;
        RECT  0.054 68.64 0.138 68.664 ;
    END
    PORT
      LAYER M4 ;
        RECT  0.025 68.64 0.108 68.664 ;
    END
  END d[495]
  PIN d[496]
    DIRECTION INPUT ;
    USE SIGNAL ;
    PORT
      LAYER M4 ;
        RECT  0.054 68.784 0.138 68.808 ;
    END
  END d[496]
  PIN d[497]
    DIRECTION INPUT ;
    USE SIGNAL ;
    PORT
      LAYER M4 ;
        RECT  0.054 68.928 0.138 68.952 ;
    END
  END d[497]
  PIN d[498]
    DIRECTION INPUT ;
    USE SIGNAL ;
    PORT
      LAYER M4 ;
        RECT  0.054 69.024 0.138 69.048 ;
    END
  END d[498]
  PIN d[499]
    DIRECTION INPUT ;
    USE SIGNAL ;
    PORT
      LAYER M4 ;
        RECT  0.054 69.168 0.138 69.192 ;
    END
  END d[499]
  PIN d[49]
    DIRECTION INPUT ;
    USE SIGNAL ;
    PORT
      LAYER M4 ;
        RECT  0.054 11.664 0.138 11.688 ;
    END
  END d[49]
  PIN d[4]
    DIRECTION INPUT ;
    USE SIGNAL ;
    PORT
      LAYER M4 ;
        RECT  0.054 5.904 0.138 5.928 ;
    END
  END d[4]
  PIN d[500]
    DIRECTION INPUT ;
    USE SIGNAL ;
    PORT
      LAYER M4 ;
        RECT  0.054 69.312 0.138 69.336 ;
    END
  END d[500]
  PIN d[501]
    DIRECTION INPUT ;
    USE SIGNAL ;
    PORT
      LAYER M4 ;
        RECT  0.054 69.408 0.138 69.432 ;
    END
  END d[501]
  PIN d[502]
    DIRECTION INPUT ;
    USE SIGNAL ;
    PORT
      LAYER M4 ;
        RECT  0.054 69.552 0.138 69.576 ;
    END
  END d[502]
  PIN d[503]
    DIRECTION INPUT ;
    USE SIGNAL ;
    PORT
      LAYER M4 ;
        RECT  0.054 69.696 0.138 69.72 ;
    END
  END d[503]
  PIN d[504]
    DIRECTION INPUT ;
    USE SIGNAL ;
    PORT
      LAYER M4 ;
        RECT  0.054 69.792 0.138 69.816 ;
    END
    PORT
      LAYER M4 ;
        RECT  0.025 69.792 0.108 69.816 ;
    END
  END d[504]
  PIN d[505]
    DIRECTION INPUT ;
    USE SIGNAL ;
    PORT
      LAYER M4 ;
        RECT  0.054 69.936 0.138 69.96 ;
    END
  END d[505]
  PIN d[506]
    DIRECTION INPUT ;
    USE SIGNAL ;
    PORT
      LAYER M4 ;
        RECT  0.054 70.08 0.138 70.104 ;
    END
  END d[506]
  PIN d[507]
    DIRECTION INPUT ;
    USE SIGNAL ;
    PORT
      LAYER M4 ;
        RECT  0.054 70.176 0.138 70.2 ;
    END
  END d[507]
  PIN d[50]
    DIRECTION INPUT ;
    USE SIGNAL ;
    PORT
      LAYER M4 ;
        RECT  0.054 11.76 0.138 11.784 ;
    END
  END d[50]
  PIN d[51]
    DIRECTION INPUT ;
    USE SIGNAL ;
    PORT
      LAYER M4 ;
        RECT  0.054 11.904 0.138 11.928 ;
    END
  END d[51]
  PIN d[52]
    DIRECTION INPUT ;
    USE SIGNAL ;
    PORT
      LAYER M4 ;
        RECT  0.054 12.048 0.138 12.072 ;
    END
  END d[52]
  PIN d[53]
    DIRECTION INPUT ;
    USE SIGNAL ;
    PORT
      LAYER M4 ;
        RECT  0.054 12.144 0.138 12.168 ;
    END
  END d[53]
  PIN d[54]
    DIRECTION INPUT ;
    USE SIGNAL ;
    PORT
      LAYER M4 ;
        RECT  0.054 12.288 0.138 12.312 ;
    END
  END d[54]
  PIN d[55]
    DIRECTION INPUT ;
    USE SIGNAL ;
    PORT
      LAYER M4 ;
        RECT  0.054 12.432 0.138 12.456 ;
    END
  END d[55]
  PIN d[56]
    DIRECTION INPUT ;
    USE SIGNAL ;
    PORT
      LAYER M4 ;
        RECT  0.054 12.528 0.138 12.552 ;
    END
  END d[56]
  PIN d[57]
    DIRECTION INPUT ;
    USE SIGNAL ;
    PORT
      LAYER M4 ;
        RECT  0.054 12.672 0.138 12.696 ;
    END
  END d[57]
  PIN d[58]
    DIRECTION INPUT ;
    USE SIGNAL ;
    PORT
      LAYER M4 ;
        RECT  0.054 12.816 0.138 12.84 ;
    END
  END d[58]
  PIN d[59]
    DIRECTION INPUT ;
    USE SIGNAL ;
    PORT
      LAYER M4 ;
        RECT  0.054 12.912 0.138 12.936 ;
    END
  END d[59]
  PIN d[5]
    DIRECTION INPUT ;
    USE SIGNAL ;
    PORT
      LAYER M4 ;
        RECT  0.054 6.048 0.138 6.072 ;
    END
  END d[5]
  PIN d[60]
    DIRECTION INPUT ;
    USE SIGNAL ;
    PORT
      LAYER M4 ;
        RECT  0.054 13.056 0.138 13.08 ;
    END
  END d[60]
  PIN d[61]
    DIRECTION INPUT ;
    USE SIGNAL ;
    PORT
      LAYER M4 ;
        RECT  0.054 13.2 0.138 13.224 ;
    END
  END d[61]
  PIN d[62]
    DIRECTION INPUT ;
    USE SIGNAL ;
    PORT
      LAYER M4 ;
        RECT  0.054 13.296 0.138 13.32 ;
    END
  END d[62]
  PIN d[63]
    DIRECTION INPUT ;
    USE SIGNAL ;
    PORT
      LAYER M4 ;
        RECT  0.054 13.44 0.138 13.464 ;
    END
  END d[63]
  PIN d[64]
    DIRECTION INPUT ;
    USE SIGNAL ;
    PORT
      LAYER M4 ;
        RECT  0.054 13.584 0.138 13.608 ;
    END
  END d[64]
  PIN d[65]
    DIRECTION INPUT ;
    USE SIGNAL ;
    PORT
      LAYER M4 ;
        RECT  0.054 13.68 0.138 13.704 ;
    END
  END d[65]
  PIN d[66]
    DIRECTION INPUT ;
    USE SIGNAL ;
    PORT
      LAYER M4 ;
        RECT  0.054 13.824 0.138 13.848 ;
    END
  END d[66]
  PIN d[67]
    DIRECTION INPUT ;
    USE SIGNAL ;
    PORT
      LAYER M4 ;
        RECT  0.054 13.968 0.138 13.992 ;
    END
  END d[67]
  PIN d[68]
    DIRECTION INPUT ;
    USE SIGNAL ;
    PORT
      LAYER M4 ;
        RECT  0.054 14.064 0.138 14.088 ;
    END
  END d[68]
  PIN d[69]
    DIRECTION INPUT ;
    USE SIGNAL ;
    PORT
      LAYER M4 ;
        RECT  0.054 14.208 0.138 14.232 ;
    END
  END d[69]
  PIN d[6]
    DIRECTION INPUT ;
    USE SIGNAL ;
    PORT
      LAYER M4 ;
        RECT  0.054 6.144 0.138 6.168 ;
    END
  END d[6]
  PIN d[70]
    DIRECTION INPUT ;
    USE SIGNAL ;
    PORT
      LAYER M4 ;
        RECT  0.054 14.352 0.138 14.376 ;
    END
  END d[70]
  PIN d[71]
    DIRECTION INPUT ;
    USE SIGNAL ;
    PORT
      LAYER M4 ;
        RECT  0.054 14.448 0.138 14.472 ;
    END
  END d[71]
  PIN d[72]
    DIRECTION INPUT ;
    USE SIGNAL ;
    PORT
      LAYER M4 ;
        RECT  0.054 14.592 0.138 14.616 ;
    END
  END d[72]
  PIN d[73]
    DIRECTION INPUT ;
    USE SIGNAL ;
    PORT
      LAYER M4 ;
        RECT  0.054 14.736 0.138 14.76 ;
    END
  END d[73]
  PIN d[74]
    DIRECTION INPUT ;
    USE SIGNAL ;
    PORT
      LAYER M4 ;
        RECT  0.054 14.832 0.138 14.856 ;
    END
  END d[74]
  PIN d[75]
    DIRECTION INPUT ;
    USE SIGNAL ;
    PORT
      LAYER M4 ;
        RECT  0.054 14.976 0.138 15 ;
    END
  END d[75]
  PIN d[76]
    DIRECTION INPUT ;
    USE SIGNAL ;
    PORT
      LAYER M4 ;
        RECT  0.054 15.12 0.138 15.144 ;
    END
  END d[76]
  PIN d[77]
    DIRECTION INPUT ;
    USE SIGNAL ;
    PORT
      LAYER M4 ;
        RECT  0.054 15.216 0.138 15.24 ;
    END
  END d[77]
  PIN d[78]
    DIRECTION INPUT ;
    USE SIGNAL ;
    PORT
      LAYER M4 ;
        RECT  0.054 15.36 0.138 15.384 ;
    END
  END d[78]
  PIN d[79]
    DIRECTION INPUT ;
    USE SIGNAL ;
    PORT
      LAYER M4 ;
        RECT  0.054 15.504 0.138 15.528 ;
    END
  END d[79]
  PIN d[7]
    DIRECTION INPUT ;
    USE SIGNAL ;
    PORT
      LAYER M4 ;
        RECT  0.054 6.288 0.138 6.312 ;
    END
  END d[7]
  PIN d[80]
    DIRECTION INPUT ;
    USE SIGNAL ;
    PORT
      LAYER M4 ;
        RECT  0.054 15.6 0.138 15.624 ;
    END
  END d[80]
  PIN d[81]
    DIRECTION INPUT ;
    USE SIGNAL ;
    PORT
      LAYER M4 ;
        RECT  0.054 15.744 0.138 15.768 ;
    END
  END d[81]
  PIN d[82]
    DIRECTION INPUT ;
    USE SIGNAL ;
    PORT
      LAYER M4 ;
        RECT  0.054 15.888 0.138 15.912 ;
    END
  END d[82]
  PIN d[83]
    DIRECTION INPUT ;
    USE SIGNAL ;
    PORT
      LAYER M4 ;
        RECT  0.054 15.984 0.138 16.008 ;
    END
  END d[83]
  PIN d[84]
    DIRECTION INPUT ;
    USE SIGNAL ;
    PORT
      LAYER M4 ;
        RECT  0.054 16.128 0.138 16.152 ;
    END
  END d[84]
  PIN d[85]
    DIRECTION INPUT ;
    USE SIGNAL ;
    PORT
      LAYER M4 ;
        RECT  0.054 16.272 0.138 16.296 ;
    END
  END d[85]
  PIN d[86]
    DIRECTION INPUT ;
    USE SIGNAL ;
    PORT
      LAYER M4 ;
        RECT  0.054 16.368 0.138 16.392 ;
    END
  END d[86]
  PIN d[87]
    DIRECTION INPUT ;
    USE SIGNAL ;
    PORT
      LAYER M4 ;
        RECT  0.054 16.512 0.138 16.536 ;
    END
  END d[87]
  PIN d[88]
    DIRECTION INPUT ;
    USE SIGNAL ;
    PORT
      LAYER M4 ;
        RECT  0.054 16.656 0.138 16.68 ;
    END
  END d[88]
  PIN d[89]
    DIRECTION INPUT ;
    USE SIGNAL ;
    PORT
      LAYER M4 ;
        RECT  0.054 16.752 0.138 16.776 ;
    END
  END d[89]
  PIN d[8]
    DIRECTION INPUT ;
    USE SIGNAL ;
    PORT
      LAYER M4 ;
        RECT  0.054 6.432 0.138 6.456 ;
    END
  END d[8]
  PIN d[90]
    DIRECTION INPUT ;
    USE SIGNAL ;
    PORT
      LAYER M4 ;
        RECT  0.054 16.896 0.138 16.92 ;
    END
  END d[90]
  PIN d[91]
    DIRECTION INPUT ;
    USE SIGNAL ;
    PORT
      LAYER M4 ;
        RECT  0.054 17.04 0.138 17.064 ;
    END
  END d[91]
  PIN d[92]
    DIRECTION INPUT ;
    USE SIGNAL ;
    PORT
      LAYER M4 ;
        RECT  0.054 17.136 0.138 17.16 ;
    END
  END d[92]
  PIN d[93]
    DIRECTION INPUT ;
    USE SIGNAL ;
    PORT
      LAYER M4 ;
        RECT  0.054 17.28 0.138 17.304 ;
    END
  END d[93]
  PIN d[94]
    DIRECTION INPUT ;
    USE SIGNAL ;
    PORT
      LAYER M4 ;
        RECT  0.054 17.424 0.138 17.448 ;
    END
  END d[94]
  PIN d[95]
    DIRECTION INPUT ;
    USE SIGNAL ;
    PORT
      LAYER M4 ;
        RECT  0.054 17.52 0.138 17.544 ;
    END
  END d[95]
  PIN d[96]
    DIRECTION INPUT ;
    USE SIGNAL ;
    PORT
      LAYER M4 ;
        RECT  0.054 17.664 0.138 17.688 ;
    END
  END d[96]
  PIN d[97]
    DIRECTION INPUT ;
    USE SIGNAL ;
    PORT
      LAYER M4 ;
        RECT  0.054 17.808 0.138 17.832 ;
    END
  END d[97]
  PIN d[98]
    DIRECTION INPUT ;
    USE SIGNAL ;
    PORT
      LAYER M4 ;
        RECT  0.054 17.904 0.138 17.928 ;
    END
  END d[98]
  PIN d[99]
    DIRECTION INPUT ;
    USE SIGNAL ;
    PORT
      LAYER M4 ;
        RECT  0.054 18.048 0.138 18.072 ;
    END
  END d[99]
  PIN d[9]
    DIRECTION INPUT ;
    USE SIGNAL ;
    PORT
      LAYER M4 ;
        RECT  0.054 6.528 0.138 6.552 ;
    END
  END d[9]
  PIN q[0]
    DIRECTION OUTPUT ;
    USE SIGNAL ;
    PORT
      LAYER M4 ;
        RECT  21.462 5.424 21.546 5.448 ;
    END
  END q[0]
  PIN q[100]
    DIRECTION OUTPUT ;
    USE SIGNAL ;
    PORT
      LAYER M4 ;
        RECT  21.462 18.192 21.546 18.216 ;
    END
  END q[100]
  PIN q[101]
    DIRECTION OUTPUT ;
    USE SIGNAL ;
    PORT
      LAYER M4 ;
        RECT  21.462 18.288 21.546 18.312 ;
    END
  END q[101]
  PIN q[102]
    DIRECTION OUTPUT ;
    USE SIGNAL ;
    PORT
      LAYER M4 ;
        RECT  21.462 18.432 21.546 18.456 ;
    END
  END q[102]
  PIN q[103]
    DIRECTION OUTPUT ;
    USE SIGNAL ;
    PORT
      LAYER M4 ;
        RECT  21.462 18.576 21.546 18.6 ;
    END
  END q[103]
  PIN q[104]
    DIRECTION OUTPUT ;
    USE SIGNAL ;
    PORT
      LAYER M4 ;
        RECT  21.462 18.672 21.546 18.696 ;
    END
  END q[104]
  PIN q[105]
    DIRECTION OUTPUT ;
    USE SIGNAL ;
    PORT
      LAYER M4 ;
        RECT  21.462 18.816 21.546 18.84 ;
    END
  END q[105]
  PIN q[106]
    DIRECTION OUTPUT ;
    USE SIGNAL ;
    PORT
      LAYER M4 ;
        RECT  21.462 18.912 21.546 18.936 ;
    END
  END q[106]
  PIN q[107]
    DIRECTION OUTPUT ;
    USE SIGNAL ;
    PORT
      LAYER M4 ;
        RECT  21.462 19.056 21.546 19.08 ;
    END
  END q[107]
  PIN q[108]
    DIRECTION OUTPUT ;
    USE SIGNAL ;
    PORT
      LAYER M4 ;
        RECT  21.462 19.2 21.546 19.224 ;
    END
  END q[108]
  PIN q[109]
    DIRECTION OUTPUT ;
    USE SIGNAL ;
    PORT
      LAYER M4 ;
        RECT  21.462 19.296 21.546 19.32 ;
    END
  END q[109]
  PIN q[10]
    DIRECTION OUTPUT ;
    USE SIGNAL ;
    PORT
      LAYER M4 ;
        RECT  21.462 6.672 21.546 6.696 ;
    END
  END q[10]
  PIN q[110]
    DIRECTION OUTPUT ;
    USE SIGNAL ;
    PORT
      LAYER M4 ;
        RECT  21.462 19.44 21.546 19.464 ;
    END
  END q[110]
  PIN q[111]
    DIRECTION OUTPUT ;
    USE SIGNAL ;
    PORT
      LAYER M4 ;
        RECT  21.462 19.584 21.546 19.608 ;
    END
  END q[111]
  PIN q[112]
    DIRECTION OUTPUT ;
    USE SIGNAL ;
    PORT
      LAYER M4 ;
        RECT  21.462 19.68 21.546 19.704 ;
    END
  END q[112]
  PIN q[113]
    DIRECTION OUTPUT ;
    USE SIGNAL ;
    PORT
      LAYER M4 ;
        RECT  21.462 19.824 21.546 19.848 ;
    END
  END q[113]
  PIN q[114]
    DIRECTION OUTPUT ;
    USE SIGNAL ;
    PORT
      LAYER M4 ;
        RECT  21.462 19.968 21.546 19.992 ;
    END
  END q[114]
  PIN q[115]
    DIRECTION OUTPUT ;
    USE SIGNAL ;
    PORT
      LAYER M4 ;
        RECT  21.462 20.064 21.546 20.088 ;
    END
  END q[115]
  PIN q[116]
    DIRECTION OUTPUT ;
    USE SIGNAL ;
    PORT
      LAYER M4 ;
        RECT  21.462 20.208 21.546 20.232 ;
    END
  END q[116]
  PIN q[117]
    DIRECTION OUTPUT ;
    USE SIGNAL ;
    PORT
      LAYER M4 ;
        RECT  21.462 20.352 21.546 20.376 ;
    END
  END q[117]
  PIN q[118]
    DIRECTION OUTPUT ;
    USE SIGNAL ;
    PORT
      LAYER M4 ;
        RECT  21.462 20.448 21.546 20.472 ;
    END
  END q[118]
  PIN q[119]
    DIRECTION OUTPUT ;
    USE SIGNAL ;
    PORT
      LAYER M4 ;
        RECT  21.462 20.592 21.546 20.616 ;
    END
  END q[119]
  PIN q[11]
    DIRECTION OUTPUT ;
    USE SIGNAL ;
    PORT
      LAYER M4 ;
        RECT  21.462 6.816 21.546 6.84 ;
    END
  END q[11]
  PIN q[120]
    DIRECTION OUTPUT ;
    USE SIGNAL ;
    PORT
      LAYER M4 ;
        RECT  21.462 20.736 21.546 20.76 ;
    END
  END q[120]
  PIN q[121]
    DIRECTION OUTPUT ;
    USE SIGNAL ;
    PORT
      LAYER M4 ;
        RECT  21.462 20.832 21.546 20.856 ;
    END
  END q[121]
  PIN q[122]
    DIRECTION OUTPUT ;
    USE SIGNAL ;
    PORT
      LAYER M4 ;
        RECT  21.462 20.976 21.546 21 ;
    END
  END q[122]
  PIN q[123]
    DIRECTION OUTPUT ;
    USE SIGNAL ;
    PORT
      LAYER M4 ;
        RECT  21.462 21.12 21.546 21.144 ;
    END
  END q[123]
  PIN q[124]
    DIRECTION OUTPUT ;
    USE SIGNAL ;
    PORT
      LAYER M4 ;
        RECT  21.462 21.216 21.546 21.24 ;
    END
  END q[124]
  PIN q[125]
    DIRECTION OUTPUT ;
    USE SIGNAL ;
    PORT
      LAYER M4 ;
        RECT  21.462 21.36 21.546 21.384 ;
    END
  END q[125]
  PIN q[126]
    DIRECTION OUTPUT ;
    USE SIGNAL ;
    PORT
      LAYER M4 ;
        RECT  21.462 21.504 21.546 21.528 ;
    END
  END q[126]
  PIN q[127]
    DIRECTION OUTPUT ;
    USE SIGNAL ;
    PORT
      LAYER M4 ;
        RECT  21.462 21.6 21.546 21.624 ;
    END
  END q[127]
  PIN q[128]
    DIRECTION OUTPUT ;
    USE SIGNAL ;
    PORT
      LAYER M4 ;
        RECT  21.462 21.744 21.546 21.768 ;
    END
  END q[128]
  PIN q[129]
    DIRECTION OUTPUT ;
    USE SIGNAL ;
    PORT
      LAYER M4 ;
        RECT  21.462 21.888 21.546 21.912 ;
    END
  END q[129]
  PIN q[12]
    DIRECTION OUTPUT ;
    USE SIGNAL ;
    PORT
      LAYER M4 ;
        RECT  21.462 6.912 21.546 6.936 ;
    END
  END q[12]
  PIN q[130]
    DIRECTION OUTPUT ;
    USE SIGNAL ;
    PORT
      LAYER M4 ;
        RECT  21.462 21.984 21.546 22.008 ;
    END
  END q[130]
  PIN q[131]
    DIRECTION OUTPUT ;
    USE SIGNAL ;
    PORT
      LAYER M4 ;
        RECT  21.462 22.128 21.546 22.152 ;
    END
  END q[131]
  PIN q[132]
    DIRECTION OUTPUT ;
    USE SIGNAL ;
    PORT
      LAYER M4 ;
        RECT  21.462 22.272 21.546 22.296 ;
    END
  END q[132]
  PIN q[133]
    DIRECTION OUTPUT ;
    USE SIGNAL ;
    PORT
      LAYER M4 ;
        RECT  21.462 22.368 21.546 22.392 ;
    END
  END q[133]
  PIN q[134]
    DIRECTION OUTPUT ;
    USE SIGNAL ;
    PORT
      LAYER M4 ;
        RECT  21.462 22.512 21.546 22.536 ;
    END
  END q[134]
  PIN q[135]
    DIRECTION OUTPUT ;
    USE SIGNAL ;
    PORT
      LAYER M4 ;
        RECT  21.462 22.656 21.546 22.68 ;
    END
  END q[135]
  PIN q[136]
    DIRECTION OUTPUT ;
    USE SIGNAL ;
    PORT
      LAYER M4 ;
        RECT  21.462 22.752 21.546 22.776 ;
    END
  END q[136]
  PIN q[137]
    DIRECTION OUTPUT ;
    USE SIGNAL ;
    PORT
      LAYER M4 ;
        RECT  21.462 22.896 21.546 22.92 ;
    END
  END q[137]
  PIN q[138]
    DIRECTION OUTPUT ;
    USE SIGNAL ;
    PORT
      LAYER M4 ;
        RECT  21.462 23.04 21.546 23.064 ;
    END
  END q[138]
  PIN q[139]
    DIRECTION OUTPUT ;
    USE SIGNAL ;
    PORT
      LAYER M4 ;
        RECT  21.462 23.136 21.546 23.16 ;
    END
  END q[139]
  PIN q[13]
    DIRECTION OUTPUT ;
    USE SIGNAL ;
    PORT
      LAYER M4 ;
        RECT  21.462 7.056 21.546 7.08 ;
    END
  END q[13]
  PIN q[140]
    DIRECTION OUTPUT ;
    USE SIGNAL ;
    PORT
      LAYER M4 ;
        RECT  21.462 23.28 21.546 23.304 ;
    END
  END q[140]
  PIN q[141]
    DIRECTION OUTPUT ;
    USE SIGNAL ;
    PORT
      LAYER M4 ;
        RECT  21.462 23.424 21.546 23.448 ;
    END
  END q[141]
  PIN q[142]
    DIRECTION OUTPUT ;
    USE SIGNAL ;
    PORT
      LAYER M4 ;
        RECT  21.462 23.52 21.546 23.544 ;
    END
  END q[142]
  PIN q[143]
    DIRECTION OUTPUT ;
    USE SIGNAL ;
    PORT
      LAYER M4 ;
        RECT  21.462 23.664 21.546 23.688 ;
    END
  END q[143]
  PIN q[144]
    DIRECTION OUTPUT ;
    USE SIGNAL ;
    PORT
      LAYER M4 ;
        RECT  21.462 23.808 21.546 23.832 ;
    END
  END q[144]
  PIN q[145]
    DIRECTION OUTPUT ;
    USE SIGNAL ;
    PORT
      LAYER M4 ;
        RECT  21.462 23.904 21.546 23.928 ;
    END
  END q[145]
  PIN q[146]
    DIRECTION OUTPUT ;
    USE SIGNAL ;
    PORT
      LAYER M4 ;
        RECT  21.462 24.048 21.546 24.072 ;
    END
  END q[146]
  PIN q[147]
    DIRECTION OUTPUT ;
    USE SIGNAL ;
    PORT
      LAYER M4 ;
        RECT  21.462 24.192 21.546 24.216 ;
    END
  END q[147]
  PIN q[148]
    DIRECTION OUTPUT ;
    USE SIGNAL ;
    PORT
      LAYER M4 ;
        RECT  21.462 24.288 21.546 24.312 ;
    END
  END q[148]
  PIN q[149]
    DIRECTION OUTPUT ;
    USE SIGNAL ;
    PORT
      LAYER M4 ;
        RECT  21.462 24.432 21.546 24.456 ;
    END
  END q[149]
  PIN q[14]
    DIRECTION OUTPUT ;
    USE SIGNAL ;
    PORT
      LAYER M4 ;
        RECT  21.462 7.2 21.546 7.224 ;
    END
  END q[14]
  PIN q[150]
    DIRECTION OUTPUT ;
    USE SIGNAL ;
    PORT
      LAYER M4 ;
        RECT  21.462 24.576 21.546 24.6 ;
    END
  END q[150]
  PIN q[151]
    DIRECTION OUTPUT ;
    USE SIGNAL ;
    PORT
      LAYER M4 ;
        RECT  21.462 24.672 21.546 24.696 ;
    END
  END q[151]
  PIN q[152]
    DIRECTION OUTPUT ;
    USE SIGNAL ;
    PORT
      LAYER M4 ;
        RECT  21.462 24.816 21.546 24.84 ;
    END
  END q[152]
  PIN q[153]
    DIRECTION OUTPUT ;
    USE SIGNAL ;
    PORT
      LAYER M4 ;
        RECT  21.462 24.96 21.546 24.984 ;
    END
  END q[153]
  PIN q[154]
    DIRECTION OUTPUT ;
    USE SIGNAL ;
    PORT
      LAYER M4 ;
        RECT  21.462 25.056 21.546 25.08 ;
    END
  END q[154]
  PIN q[155]
    DIRECTION OUTPUT ;
    USE SIGNAL ;
    PORT
      LAYER M4 ;
        RECT  21.462 25.2 21.546 25.224 ;
    END
  END q[155]
  PIN q[156]
    DIRECTION OUTPUT ;
    USE SIGNAL ;
    PORT
      LAYER M4 ;
        RECT  21.462 25.344 21.546 25.368 ;
    END
  END q[156]
  PIN q[157]
    DIRECTION OUTPUT ;
    USE SIGNAL ;
    PORT
      LAYER M4 ;
        RECT  21.462 25.44 21.546 25.464 ;
    END
  END q[157]
  PIN q[158]
    DIRECTION OUTPUT ;
    USE SIGNAL ;
    PORT
      LAYER M4 ;
        RECT  21.462 25.584 21.546 25.608 ;
    END
  END q[158]
  PIN q[159]
    DIRECTION OUTPUT ;
    USE SIGNAL ;
    PORT
      LAYER M4 ;
        RECT  21.462 25.728 21.546 25.752 ;
    END
  END q[159]
  PIN q[15]
    DIRECTION OUTPUT ;
    USE SIGNAL ;
    PORT
      LAYER M4 ;
        RECT  21.462 7.296 21.546 7.32 ;
    END
  END q[15]
  PIN q[160]
    DIRECTION OUTPUT ;
    USE SIGNAL ;
    PORT
      LAYER M4 ;
        RECT  21.462 25.824 21.546 25.848 ;
    END
  END q[160]
  PIN q[161]
    DIRECTION OUTPUT ;
    USE SIGNAL ;
    PORT
      LAYER M4 ;
        RECT  21.462 25.968 21.546 25.992 ;
    END
  END q[161]
  PIN q[162]
    DIRECTION OUTPUT ;
    USE SIGNAL ;
    PORT
      LAYER M4 ;
        RECT  21.462 26.112 21.546 26.136 ;
    END
  END q[162]
  PIN q[163]
    DIRECTION OUTPUT ;
    USE SIGNAL ;
    PORT
      LAYER M4 ;
        RECT  21.462 26.208 21.546 26.232 ;
    END
  END q[163]
  PIN q[164]
    DIRECTION OUTPUT ;
    USE SIGNAL ;
    PORT
      LAYER M4 ;
        RECT  21.462 26.352 21.546 26.376 ;
    END
  END q[164]
  PIN q[165]
    DIRECTION OUTPUT ;
    USE SIGNAL ;
    PORT
      LAYER M4 ;
        RECT  21.462 26.496 21.546 26.52 ;
    END
  END q[165]
  PIN q[166]
    DIRECTION OUTPUT ;
    USE SIGNAL ;
    PORT
      LAYER M4 ;
        RECT  21.462 26.592 21.546 26.616 ;
    END
    PORT
      LAYER M4 ;
        RECT  21.516 26.592 21.593 26.616 ;
    END
  END q[166]
  PIN q[167]
    DIRECTION OUTPUT ;
    USE SIGNAL ;
    PORT
      LAYER M4 ;
        RECT  21.462 26.736 21.546 26.76 ;
    END
  END q[167]
  PIN q[168]
    DIRECTION OUTPUT ;
    USE SIGNAL ;
    PORT
      LAYER M4 ;
        RECT  21.462 26.88 21.546 26.904 ;
    END
  END q[168]
  PIN q[169]
    DIRECTION OUTPUT ;
    USE SIGNAL ;
    PORT
      LAYER M4 ;
        RECT  21.462 26.976 21.546 27 ;
    END
  END q[169]
  PIN q[16]
    DIRECTION OUTPUT ;
    USE SIGNAL ;
    PORT
      LAYER M4 ;
        RECT  21.462 7.44 21.546 7.464 ;
    END
  END q[16]
  PIN q[170]
    DIRECTION OUTPUT ;
    USE SIGNAL ;
    PORT
      LAYER M4 ;
        RECT  21.462 27.12 21.546 27.144 ;
    END
  END q[170]
  PIN q[171]
    DIRECTION OUTPUT ;
    USE SIGNAL ;
    PORT
      LAYER M4 ;
        RECT  21.462 27.264 21.546 27.288 ;
    END
  END q[171]
  PIN q[172]
    DIRECTION OUTPUT ;
    USE SIGNAL ;
    PORT
      LAYER M4 ;
        RECT  21.462 27.36 21.546 27.384 ;
    END
  END q[172]
  PIN q[173]
    DIRECTION OUTPUT ;
    USE SIGNAL ;
    PORT
      LAYER M4 ;
        RECT  21.462 27.504 21.546 27.528 ;
    END
  END q[173]
  PIN q[174]
    DIRECTION OUTPUT ;
    USE SIGNAL ;
    PORT
      LAYER M4 ;
        RECT  21.462 27.648 21.546 27.672 ;
    END
  END q[174]
  PIN q[175]
    DIRECTION OUTPUT ;
    USE SIGNAL ;
    PORT
      LAYER M4 ;
        RECT  21.462 27.744 21.546 27.768 ;
    END
  END q[175]
  PIN q[176]
    DIRECTION OUTPUT ;
    USE SIGNAL ;
    PORT
      LAYER M4 ;
        RECT  21.462 27.888 21.546 27.912 ;
    END
  END q[176]
  PIN q[177]
    DIRECTION OUTPUT ;
    USE SIGNAL ;
    PORT
      LAYER M4 ;
        RECT  21.462 28.032 21.546 28.056 ;
    END
  END q[177]
  PIN q[178]
    DIRECTION OUTPUT ;
    USE SIGNAL ;
    PORT
      LAYER M4 ;
        RECT  21.462 28.128 21.546 28.152 ;
    END
  END q[178]
  PIN q[179]
    DIRECTION OUTPUT ;
    USE SIGNAL ;
    PORT
      LAYER M4 ;
        RECT  21.462 28.272 21.546 28.296 ;
    END
  END q[179]
  PIN q[17]
    DIRECTION OUTPUT ;
    USE SIGNAL ;
    PORT
      LAYER M4 ;
        RECT  21.462 7.584 21.546 7.608 ;
    END
  END q[17]
  PIN q[180]
    DIRECTION OUTPUT ;
    USE SIGNAL ;
    PORT
      LAYER M4 ;
        RECT  21.462 28.416 21.546 28.44 ;
    END
  END q[180]
  PIN q[181]
    DIRECTION OUTPUT ;
    USE SIGNAL ;
    PORT
      LAYER M4 ;
        RECT  21.462 28.512 21.546 28.536 ;
    END
  END q[181]
  PIN q[182]
    DIRECTION OUTPUT ;
    USE SIGNAL ;
    PORT
      LAYER M4 ;
        RECT  21.462 28.656 21.546 28.68 ;
    END
  END q[182]
  PIN q[183]
    DIRECTION OUTPUT ;
    USE SIGNAL ;
    PORT
      LAYER M4 ;
        RECT  21.462 28.8 21.546 28.824 ;
    END
  END q[183]
  PIN q[184]
    DIRECTION OUTPUT ;
    USE SIGNAL ;
    PORT
      LAYER M4 ;
        RECT  21.462 28.896 21.546 28.92 ;
    END
  END q[184]
  PIN q[185]
    DIRECTION OUTPUT ;
    USE SIGNAL ;
    PORT
      LAYER M4 ;
        RECT  21.462 29.04 21.546 29.064 ;
    END
  END q[185]
  PIN q[186]
    DIRECTION OUTPUT ;
    USE SIGNAL ;
    PORT
      LAYER M4 ;
        RECT  21.462 29.184 21.546 29.208 ;
    END
  END q[186]
  PIN q[187]
    DIRECTION OUTPUT ;
    USE SIGNAL ;
    PORT
      LAYER M4 ;
        RECT  21.462 29.28 21.546 29.304 ;
    END
  END q[187]
  PIN q[188]
    DIRECTION OUTPUT ;
    USE SIGNAL ;
    PORT
      LAYER M4 ;
        RECT  21.462 29.424 21.546 29.448 ;
    END
  END q[188]
  PIN q[189]
    DIRECTION OUTPUT ;
    USE SIGNAL ;
    PORT
      LAYER M4 ;
        RECT  21.462 29.568 21.546 29.592 ;
    END
  END q[189]
  PIN q[18]
    DIRECTION OUTPUT ;
    USE SIGNAL ;
    PORT
      LAYER M4 ;
        RECT  21.462 7.68 21.546 7.704 ;
    END
  END q[18]
  PIN q[190]
    DIRECTION OUTPUT ;
    USE SIGNAL ;
    PORT
      LAYER M4 ;
        RECT  21.462 29.664 21.546 29.688 ;
    END
  END q[190]
  PIN q[191]
    DIRECTION OUTPUT ;
    USE SIGNAL ;
    PORT
      LAYER M4 ;
        RECT  21.462 29.808 21.546 29.832 ;
    END
  END q[191]
  PIN q[192]
    DIRECTION OUTPUT ;
    USE SIGNAL ;
    PORT
      LAYER M4 ;
        RECT  21.462 29.904 21.546 29.928 ;
    END
  END q[192]
  PIN q[193]
    DIRECTION OUTPUT ;
    USE SIGNAL ;
    PORT
      LAYER M4 ;
        RECT  21.462 30.048 21.546 30.072 ;
    END
  END q[193]
  PIN q[194]
    DIRECTION OUTPUT ;
    USE SIGNAL ;
    PORT
      LAYER M4 ;
        RECT  21.462 30.192 21.546 30.216 ;
    END
  END q[194]
  PIN q[195]
    DIRECTION OUTPUT ;
    USE SIGNAL ;
    PORT
      LAYER M4 ;
        RECT  21.462 30.288 21.546 30.312 ;
    END
  END q[195]
  PIN q[196]
    DIRECTION OUTPUT ;
    USE SIGNAL ;
    PORT
      LAYER M4 ;
        RECT  21.462 30.432 21.546 30.456 ;
    END
  END q[196]
  PIN q[197]
    DIRECTION OUTPUT ;
    USE SIGNAL ;
    PORT
      LAYER M4 ;
        RECT  21.462 30.576 21.546 30.6 ;
    END
  END q[197]
  PIN q[198]
    DIRECTION OUTPUT ;
    USE SIGNAL ;
    PORT
      LAYER M4 ;
        RECT  21.462 30.672 21.546 30.696 ;
    END
  END q[198]
  PIN q[199]
    DIRECTION OUTPUT ;
    USE SIGNAL ;
    PORT
      LAYER M4 ;
        RECT  21.462 30.816 21.546 30.84 ;
    END
  END q[199]
  PIN q[19]
    DIRECTION OUTPUT ;
    USE SIGNAL ;
    PORT
      LAYER M4 ;
        RECT  21.462 7.824 21.546 7.848 ;
    END
  END q[19]
  PIN q[1]
    DIRECTION OUTPUT ;
    USE SIGNAL ;
    PORT
      LAYER M4 ;
        RECT  21.462 5.52 21.546 5.544 ;
    END
  END q[1]
  PIN q[200]
    DIRECTION OUTPUT ;
    USE SIGNAL ;
    PORT
      LAYER M4 ;
        RECT  21.462 30.96 21.546 30.984 ;
    END
  END q[200]
  PIN q[201]
    DIRECTION OUTPUT ;
    USE SIGNAL ;
    PORT
      LAYER M4 ;
        RECT  21.462 31.056 21.546 31.08 ;
    END
  END q[201]
  PIN q[202]
    DIRECTION OUTPUT ;
    USE SIGNAL ;
    PORT
      LAYER M4 ;
        RECT  21.462 31.2 21.546 31.224 ;
    END
  END q[202]
  PIN q[203]
    DIRECTION OUTPUT ;
    USE SIGNAL ;
    PORT
      LAYER M4 ;
        RECT  21.462 31.344 21.546 31.368 ;
    END
  END q[203]
  PIN q[204]
    DIRECTION OUTPUT ;
    USE SIGNAL ;
    PORT
      LAYER M4 ;
        RECT  21.462 31.44 21.546 31.464 ;
    END
  END q[204]
  PIN q[205]
    DIRECTION OUTPUT ;
    USE SIGNAL ;
    PORT
      LAYER M4 ;
        RECT  21.462 31.584 21.546 31.608 ;
    END
  END q[205]
  PIN q[206]
    DIRECTION OUTPUT ;
    USE SIGNAL ;
    PORT
      LAYER M4 ;
        RECT  21.462 31.728 21.546 31.752 ;
    END
  END q[206]
  PIN q[207]
    DIRECTION OUTPUT ;
    USE SIGNAL ;
    PORT
      LAYER M4 ;
        RECT  21.462 31.824 21.546 31.848 ;
    END
  END q[207]
  PIN q[208]
    DIRECTION OUTPUT ;
    USE SIGNAL ;
    PORT
      LAYER M4 ;
        RECT  21.462 31.968 21.546 31.992 ;
    END
  END q[208]
  PIN q[209]
    DIRECTION OUTPUT ;
    USE SIGNAL ;
    PORT
      LAYER M4 ;
        RECT  21.462 32.112 21.546 32.136 ;
    END
  END q[209]
  PIN q[20]
    DIRECTION OUTPUT ;
    USE SIGNAL ;
    PORT
      LAYER M4 ;
        RECT  21.462 7.968 21.546 7.992 ;
    END
  END q[20]
  PIN q[210]
    DIRECTION OUTPUT ;
    USE SIGNAL ;
    PORT
      LAYER M4 ;
        RECT  21.462 32.208 21.546 32.232 ;
    END
  END q[210]
  PIN q[211]
    DIRECTION OUTPUT ;
    USE SIGNAL ;
    PORT
      LAYER M4 ;
        RECT  21.462 32.352 21.546 32.376 ;
    END
  END q[211]
  PIN q[212]
    DIRECTION OUTPUT ;
    USE SIGNAL ;
    PORT
      LAYER M4 ;
        RECT  21.462 32.496 21.546 32.52 ;
    END
  END q[212]
  PIN q[213]
    DIRECTION OUTPUT ;
    USE SIGNAL ;
    PORT
      LAYER M4 ;
        RECT  21.462 32.592 21.546 32.616 ;
    END
  END q[213]
  PIN q[214]
    DIRECTION OUTPUT ;
    USE SIGNAL ;
    PORT
      LAYER M4 ;
        RECT  21.462 32.736 21.546 32.76 ;
    END
  END q[214]
  PIN q[215]
    DIRECTION OUTPUT ;
    USE SIGNAL ;
    PORT
      LAYER M4 ;
        RECT  21.462 32.88 21.546 32.904 ;
    END
  END q[215]
  PIN q[216]
    DIRECTION OUTPUT ;
    USE SIGNAL ;
    PORT
      LAYER M4 ;
        RECT  21.462 32.976 21.546 33 ;
    END
  END q[216]
  PIN q[217]
    DIRECTION OUTPUT ;
    USE SIGNAL ;
    PORT
      LAYER M4 ;
        RECT  21.462 33.12 21.546 33.144 ;
    END
  END q[217]
  PIN q[218]
    DIRECTION OUTPUT ;
    USE SIGNAL ;
    PORT
      LAYER M4 ;
        RECT  21.462 33.264 21.546 33.288 ;
    END
  END q[218]
  PIN q[219]
    DIRECTION OUTPUT ;
    USE SIGNAL ;
    PORT
      LAYER M4 ;
        RECT  21.462 33.36 21.546 33.384 ;
    END
  END q[219]
  PIN q[21]
    DIRECTION OUTPUT ;
    USE SIGNAL ;
    PORT
      LAYER M4 ;
        RECT  21.462 8.064 21.546 8.088 ;
    END
  END q[21]
  PIN q[220]
    DIRECTION OUTPUT ;
    USE SIGNAL ;
    PORT
      LAYER M4 ;
        RECT  21.462 33.504 21.546 33.528 ;
    END
  END q[220]
  PIN q[221]
    DIRECTION OUTPUT ;
    USE SIGNAL ;
    PORT
      LAYER M4 ;
        RECT  21.462 33.648 21.546 33.672 ;
    END
  END q[221]
  PIN q[222]
    DIRECTION OUTPUT ;
    USE SIGNAL ;
    PORT
      LAYER M4 ;
        RECT  21.462 33.744 21.546 33.768 ;
    END
  END q[222]
  PIN q[223]
    DIRECTION OUTPUT ;
    USE SIGNAL ;
    PORT
      LAYER M4 ;
        RECT  21.462 33.888 21.546 33.912 ;
    END
  END q[223]
  PIN q[224]
    DIRECTION OUTPUT ;
    USE SIGNAL ;
    PORT
      LAYER M4 ;
        RECT  21.462 34.032 21.546 34.056 ;
    END
  END q[224]
  PIN q[225]
    DIRECTION OUTPUT ;
    USE SIGNAL ;
    PORT
      LAYER M4 ;
        RECT  21.462 34.128 21.546 34.152 ;
    END
  END q[225]
  PIN q[226]
    DIRECTION OUTPUT ;
    USE SIGNAL ;
    PORT
      LAYER M4 ;
        RECT  21.462 34.272 21.546 34.296 ;
    END
  END q[226]
  PIN q[227]
    DIRECTION OUTPUT ;
    USE SIGNAL ;
    PORT
      LAYER M4 ;
        RECT  21.462 34.416 21.546 34.44 ;
    END
  END q[227]
  PIN q[228]
    DIRECTION OUTPUT ;
    USE SIGNAL ;
    PORT
      LAYER M4 ;
        RECT  21.462 34.512 21.546 34.536 ;
    END
  END q[228]
  PIN q[229]
    DIRECTION OUTPUT ;
    USE SIGNAL ;
    PORT
      LAYER M4 ;
        RECT  21.462 34.656 21.546 34.68 ;
    END
  END q[229]
  PIN q[22]
    DIRECTION OUTPUT ;
    USE SIGNAL ;
    PORT
      LAYER M4 ;
        RECT  21.462 8.208 21.546 8.232 ;
    END
  END q[22]
  PIN q[230]
    DIRECTION OUTPUT ;
    USE SIGNAL ;
    PORT
      LAYER M4 ;
        RECT  21.462 34.8 21.546 34.824 ;
    END
  END q[230]
  PIN q[231]
    DIRECTION OUTPUT ;
    USE SIGNAL ;
    PORT
      LAYER M4 ;
        RECT  21.462 34.896 21.546 34.92 ;
    END
  END q[231]
  PIN q[232]
    DIRECTION OUTPUT ;
    USE SIGNAL ;
    PORT
      LAYER M4 ;
        RECT  21.462 35.04 21.546 35.064 ;
    END
  END q[232]
  PIN q[233]
    DIRECTION OUTPUT ;
    USE SIGNAL ;
    PORT
      LAYER M4 ;
        RECT  21.462 35.184 21.546 35.208 ;
    END
  END q[233]
  PIN q[234]
    DIRECTION OUTPUT ;
    USE SIGNAL ;
    PORT
      LAYER M4 ;
        RECT  21.462 35.28 21.546 35.304 ;
    END
  END q[234]
  PIN q[235]
    DIRECTION OUTPUT ;
    USE SIGNAL ;
    PORT
      LAYER M4 ;
        RECT  21.462 35.424 21.546 35.448 ;
    END
  END q[235]
  PIN q[236]
    DIRECTION OUTPUT ;
    USE SIGNAL ;
    PORT
      LAYER M4 ;
        RECT  21.462 35.568 21.546 35.592 ;
    END
  END q[236]
  PIN q[237]
    DIRECTION OUTPUT ;
    USE SIGNAL ;
    PORT
      LAYER M4 ;
        RECT  21.462 35.664 21.546 35.688 ;
    END
  END q[237]
  PIN q[238]
    DIRECTION OUTPUT ;
    USE SIGNAL ;
    PORT
      LAYER M4 ;
        RECT  21.462 35.808 21.546 35.832 ;
    END
  END q[238]
  PIN q[239]
    DIRECTION OUTPUT ;
    USE SIGNAL ;
    PORT
      LAYER M4 ;
        RECT  21.462 35.952 21.546 35.976 ;
    END
  END q[239]
  PIN q[23]
    DIRECTION OUTPUT ;
    USE SIGNAL ;
    PORT
      LAYER M4 ;
        RECT  21.462 8.304 21.546 8.328 ;
    END
  END q[23]
  PIN q[240]
    DIRECTION OUTPUT ;
    USE SIGNAL ;
    PORT
      LAYER M4 ;
        RECT  21.462 36.048 21.546 36.072 ;
    END
  END q[240]
  PIN q[241]
    DIRECTION OUTPUT ;
    USE SIGNAL ;
    PORT
      LAYER M4 ;
        RECT  21.462 36.192 21.546 36.216 ;
    END
  END q[241]
  PIN q[242]
    DIRECTION OUTPUT ;
    USE SIGNAL ;
    PORT
      LAYER M4 ;
        RECT  21.462 36.336 21.546 36.36 ;
    END
  END q[242]
  PIN q[243]
    DIRECTION OUTPUT ;
    USE SIGNAL ;
    PORT
      LAYER M4 ;
        RECT  21.462 36.432 21.546 36.456 ;
    END
  END q[243]
  PIN q[244]
    DIRECTION OUTPUT ;
    USE SIGNAL ;
    PORT
      LAYER M4 ;
        RECT  21.462 36.576 21.546 36.6 ;
    END
  END q[244]
  PIN q[245]
    DIRECTION OUTPUT ;
    USE SIGNAL ;
    PORT
      LAYER M4 ;
        RECT  21.462 36.72 21.546 36.744 ;
    END
  END q[245]
  PIN q[246]
    DIRECTION OUTPUT ;
    USE SIGNAL ;
    PORT
      LAYER M4 ;
        RECT  21.462 36.816 21.546 36.84 ;
    END
  END q[246]
  PIN q[247]
    DIRECTION OUTPUT ;
    USE SIGNAL ;
    PORT
      LAYER M4 ;
        RECT  21.462 36.96 21.546 36.984 ;
    END
  END q[247]
  PIN q[248]
    DIRECTION OUTPUT ;
    USE SIGNAL ;
    PORT
      LAYER M4 ;
        RECT  21.462 37.104 21.546 37.128 ;
    END
  END q[248]
  PIN q[249]
    DIRECTION OUTPUT ;
    USE SIGNAL ;
    PORT
      LAYER M4 ;
        RECT  21.462 37.2 21.546 37.224 ;
    END
  END q[249]
  PIN q[24]
    DIRECTION OUTPUT ;
    USE SIGNAL ;
    PORT
      LAYER M4 ;
        RECT  21.462 8.448 21.546 8.472 ;
    END
  END q[24]
  PIN q[250]
    DIRECTION OUTPUT ;
    USE SIGNAL ;
    PORT
      LAYER M4 ;
        RECT  21.462 37.344 21.546 37.368 ;
    END
  END q[250]
  PIN q[251]
    DIRECTION OUTPUT ;
    USE SIGNAL ;
    PORT
      LAYER M4 ;
        RECT  21.462 37.488 21.546 37.512 ;
    END
  END q[251]
  PIN q[252]
    DIRECTION OUTPUT ;
    USE SIGNAL ;
    PORT
      LAYER M4 ;
        RECT  21.462 37.584 21.546 37.608 ;
    END
  END q[252]
  PIN q[253]
    DIRECTION OUTPUT ;
    USE SIGNAL ;
    PORT
      LAYER M4 ;
        RECT  21.462 37.728 21.546 37.752 ;
    END
  END q[253]
  PIN q[254]
    DIRECTION OUTPUT ;
    USE SIGNAL ;
    PORT
      LAYER M4 ;
        RECT  21.462 37.872 21.546 37.896 ;
    END
  END q[254]
  PIN q[255]
    DIRECTION OUTPUT ;
    USE SIGNAL ;
    PORT
      LAYER M4 ;
        RECT  21.462 37.968 21.546 37.992 ;
    END
  END q[255]
  PIN q[256]
    DIRECTION OUTPUT ;
    USE SIGNAL ;
    PORT
      LAYER M4 ;
        RECT  21.462 38.112 21.546 38.136 ;
    END
  END q[256]
  PIN q[257]
    DIRECTION OUTPUT ;
    USE SIGNAL ;
    PORT
      LAYER M4 ;
        RECT  21.462 38.256 21.546 38.28 ;
    END
  END q[257]
  PIN q[258]
    DIRECTION OUTPUT ;
    USE SIGNAL ;
    PORT
      LAYER M4 ;
        RECT  21.462 38.352 21.546 38.376 ;
    END
  END q[258]
  PIN q[259]
    DIRECTION OUTPUT ;
    USE SIGNAL ;
    PORT
      LAYER M4 ;
        RECT  21.462 38.496 21.546 38.52 ;
    END
  END q[259]
  PIN q[25]
    DIRECTION OUTPUT ;
    USE SIGNAL ;
    PORT
      LAYER M4 ;
        RECT  21.462 8.592 21.546 8.616 ;
    END
  END q[25]
  PIN q[260]
    DIRECTION OUTPUT ;
    USE SIGNAL ;
    PORT
      LAYER M4 ;
        RECT  21.462 38.64 21.546 38.664 ;
    END
  END q[260]
  PIN q[261]
    DIRECTION OUTPUT ;
    USE SIGNAL ;
    PORT
      LAYER M4 ;
        RECT  21.462 38.736 21.546 38.76 ;
    END
  END q[261]
  PIN q[262]
    DIRECTION OUTPUT ;
    USE SIGNAL ;
    PORT
      LAYER M4 ;
        RECT  21.462 38.88 21.546 38.904 ;
    END
  END q[262]
  PIN q[263]
    DIRECTION OUTPUT ;
    USE SIGNAL ;
    PORT
      LAYER M4 ;
        RECT  21.462 39.024 21.546 39.048 ;
    END
  END q[263]
  PIN q[264]
    DIRECTION OUTPUT ;
    USE SIGNAL ;
    PORT
      LAYER M4 ;
        RECT  21.462 39.12 21.546 39.144 ;
    END
  END q[264]
  PIN q[265]
    DIRECTION OUTPUT ;
    USE SIGNAL ;
    PORT
      LAYER M4 ;
        RECT  21.462 39.264 21.546 39.288 ;
    END
  END q[265]
  PIN q[266]
    DIRECTION OUTPUT ;
    USE SIGNAL ;
    PORT
      LAYER M4 ;
        RECT  21.462 39.408 21.546 39.432 ;
    END
  END q[266]
  PIN q[267]
    DIRECTION OUTPUT ;
    USE SIGNAL ;
    PORT
      LAYER M4 ;
        RECT  21.462 39.504 21.546 39.528 ;
    END
  END q[267]
  PIN q[268]
    DIRECTION OUTPUT ;
    USE SIGNAL ;
    PORT
      LAYER M4 ;
        RECT  21.462 39.648 21.546 39.672 ;
    END
  END q[268]
  PIN q[269]
    DIRECTION OUTPUT ;
    USE SIGNAL ;
    PORT
      LAYER M4 ;
        RECT  21.462 39.792 21.546 39.816 ;
    END
  END q[269]
  PIN q[26]
    DIRECTION OUTPUT ;
    USE SIGNAL ;
    PORT
      LAYER M4 ;
        RECT  21.462 8.688 21.546 8.712 ;
    END
  END q[26]
  PIN q[270]
    DIRECTION OUTPUT ;
    USE SIGNAL ;
    PORT
      LAYER M4 ;
        RECT  21.462 39.888 21.546 39.912 ;
    END
  END q[270]
  PIN q[271]
    DIRECTION OUTPUT ;
    USE SIGNAL ;
    PORT
      LAYER M4 ;
        RECT  21.462 40.032 21.546 40.056 ;
    END
  END q[271]
  PIN q[272]
    DIRECTION OUTPUT ;
    USE SIGNAL ;
    PORT
      LAYER M4 ;
        RECT  21.462 40.176 21.546 40.2 ;
    END
  END q[272]
  PIN q[273]
    DIRECTION OUTPUT ;
    USE SIGNAL ;
    PORT
      LAYER M4 ;
        RECT  21.462 40.272 21.546 40.296 ;
    END
  END q[273]
  PIN q[274]
    DIRECTION OUTPUT ;
    USE SIGNAL ;
    PORT
      LAYER M4 ;
        RECT  21.462 40.416 21.546 40.44 ;
    END
  END q[274]
  PIN q[275]
    DIRECTION OUTPUT ;
    USE SIGNAL ;
    PORT
      LAYER M4 ;
        RECT  21.462 40.512 21.546 40.536 ;
    END
  END q[275]
  PIN q[276]
    DIRECTION OUTPUT ;
    USE SIGNAL ;
    PORT
      LAYER M4 ;
        RECT  21.462 40.656 21.546 40.68 ;
    END
  END q[276]
  PIN q[277]
    DIRECTION OUTPUT ;
    USE SIGNAL ;
    PORT
      LAYER M4 ;
        RECT  21.462 40.8 21.546 40.824 ;
    END
  END q[277]
  PIN q[278]
    DIRECTION OUTPUT ;
    USE SIGNAL ;
    PORT
      LAYER M4 ;
        RECT  21.462 40.896 21.546 40.92 ;
    END
  END q[278]
  PIN q[279]
    DIRECTION OUTPUT ;
    USE SIGNAL ;
    PORT
      LAYER M4 ;
        RECT  21.462 41.04 21.546 41.064 ;
    END
  END q[279]
  PIN q[27]
    DIRECTION OUTPUT ;
    USE SIGNAL ;
    PORT
      LAYER M4 ;
        RECT  21.462 8.832 21.546 8.856 ;
    END
  END q[27]
  PIN q[280]
    DIRECTION OUTPUT ;
    USE SIGNAL ;
    PORT
      LAYER M4 ;
        RECT  21.462 41.184 21.546 41.208 ;
    END
  END q[280]
  PIN q[281]
    DIRECTION OUTPUT ;
    USE SIGNAL ;
    PORT
      LAYER M4 ;
        RECT  21.462 41.28 21.546 41.304 ;
    END
  END q[281]
  PIN q[282]
    DIRECTION OUTPUT ;
    USE SIGNAL ;
    PORT
      LAYER M4 ;
        RECT  21.462 41.424 21.546 41.448 ;
    END
  END q[282]
  PIN q[283]
    DIRECTION OUTPUT ;
    USE SIGNAL ;
    PORT
      LAYER M4 ;
        RECT  21.462 41.568 21.546 41.592 ;
    END
  END q[283]
  PIN q[284]
    DIRECTION OUTPUT ;
    USE SIGNAL ;
    PORT
      LAYER M4 ;
        RECT  21.462 41.664 21.546 41.688 ;
    END
  END q[284]
  PIN q[285]
    DIRECTION OUTPUT ;
    USE SIGNAL ;
    PORT
      LAYER M4 ;
        RECT  21.462 41.808 21.546 41.832 ;
    END
  END q[285]
  PIN q[286]
    DIRECTION OUTPUT ;
    USE SIGNAL ;
    PORT
      LAYER M4 ;
        RECT  21.462 41.952 21.546 41.976 ;
    END
  END q[286]
  PIN q[287]
    DIRECTION OUTPUT ;
    USE SIGNAL ;
    PORT
      LAYER M4 ;
        RECT  21.462 42.048 21.546 42.072 ;
    END
  END q[287]
  PIN q[288]
    DIRECTION OUTPUT ;
    USE SIGNAL ;
    PORT
      LAYER M4 ;
        RECT  21.462 42.192 21.546 42.216 ;
    END
  END q[288]
  PIN q[289]
    DIRECTION OUTPUT ;
    USE SIGNAL ;
    PORT
      LAYER M4 ;
        RECT  21.462 42.336 21.546 42.36 ;
    END
  END q[289]
  PIN q[28]
    DIRECTION OUTPUT ;
    USE SIGNAL ;
    PORT
      LAYER M4 ;
        RECT  21.462 8.976 21.546 9 ;
    END
  END q[28]
  PIN q[290]
    DIRECTION OUTPUT ;
    USE SIGNAL ;
    PORT
      LAYER M4 ;
        RECT  21.462 42.432 21.546 42.456 ;
    END
  END q[290]
  PIN q[291]
    DIRECTION OUTPUT ;
    USE SIGNAL ;
    PORT
      LAYER M4 ;
        RECT  21.462 42.576 21.546 42.6 ;
    END
  END q[291]
  PIN q[292]
    DIRECTION OUTPUT ;
    USE SIGNAL ;
    PORT
      LAYER M4 ;
        RECT  21.462 42.72 21.546 42.744 ;
    END
  END q[292]
  PIN q[293]
    DIRECTION OUTPUT ;
    USE SIGNAL ;
    PORT
      LAYER M4 ;
        RECT  21.462 42.816 21.546 42.84 ;
    END
  END q[293]
  PIN q[294]
    DIRECTION OUTPUT ;
    USE SIGNAL ;
    PORT
      LAYER M4 ;
        RECT  21.462 42.96 21.546 42.984 ;
    END
  END q[294]
  PIN q[295]
    DIRECTION OUTPUT ;
    USE SIGNAL ;
    PORT
      LAYER M4 ;
        RECT  21.462 43.104 21.546 43.128 ;
    END
  END q[295]
  PIN q[296]
    DIRECTION OUTPUT ;
    USE SIGNAL ;
    PORT
      LAYER M4 ;
        RECT  21.462 43.2 21.546 43.224 ;
    END
  END q[296]
  PIN q[297]
    DIRECTION OUTPUT ;
    USE SIGNAL ;
    PORT
      LAYER M4 ;
        RECT  21.462 43.344 21.546 43.368 ;
    END
  END q[297]
  PIN q[298]
    DIRECTION OUTPUT ;
    USE SIGNAL ;
    PORT
      LAYER M4 ;
        RECT  21.462 43.488 21.546 43.512 ;
    END
  END q[298]
  PIN q[299]
    DIRECTION OUTPUT ;
    USE SIGNAL ;
    PORT
      LAYER M4 ;
        RECT  21.462 43.584 21.546 43.608 ;
    END
  END q[299]
  PIN q[29]
    DIRECTION OUTPUT ;
    USE SIGNAL ;
    PORT
      LAYER M4 ;
        RECT  21.462 9.072 21.546 9.096 ;
    END
  END q[29]
  PIN q[2]
    DIRECTION OUTPUT ;
    USE SIGNAL ;
    PORT
      LAYER M4 ;
        RECT  21.462 5.664 21.546 5.688 ;
    END
  END q[2]
  PIN q[300]
    DIRECTION OUTPUT ;
    USE SIGNAL ;
    PORT
      LAYER M4 ;
        RECT  21.462 43.728 21.546 43.752 ;
    END
  END q[300]
  PIN q[301]
    DIRECTION OUTPUT ;
    USE SIGNAL ;
    PORT
      LAYER M4 ;
        RECT  21.462 43.872 21.546 43.896 ;
    END
  END q[301]
  PIN q[302]
    DIRECTION OUTPUT ;
    USE SIGNAL ;
    PORT
      LAYER M4 ;
        RECT  21.462 43.968 21.546 43.992 ;
    END
  END q[302]
  PIN q[303]
    DIRECTION OUTPUT ;
    USE SIGNAL ;
    PORT
      LAYER M4 ;
        RECT  21.462 44.112 21.546 44.136 ;
    END
  END q[303]
  PIN q[304]
    DIRECTION OUTPUT ;
    USE SIGNAL ;
    PORT
      LAYER M4 ;
        RECT  21.462 44.256 21.546 44.28 ;
    END
  END q[304]
  PIN q[305]
    DIRECTION OUTPUT ;
    USE SIGNAL ;
    PORT
      LAYER M4 ;
        RECT  21.462 44.352 21.546 44.376 ;
    END
  END q[305]
  PIN q[306]
    DIRECTION OUTPUT ;
    USE SIGNAL ;
    PORT
      LAYER M4 ;
        RECT  21.462 44.496 21.546 44.52 ;
    END
  END q[306]
  PIN q[307]
    DIRECTION OUTPUT ;
    USE SIGNAL ;
    PORT
      LAYER M4 ;
        RECT  21.462 44.64 21.546 44.664 ;
    END
  END q[307]
  PIN q[308]
    DIRECTION OUTPUT ;
    USE SIGNAL ;
    PORT
      LAYER M4 ;
        RECT  21.462 44.736 21.546 44.76 ;
    END
  END q[308]
  PIN q[309]
    DIRECTION OUTPUT ;
    USE SIGNAL ;
    PORT
      LAYER M4 ;
        RECT  21.462 44.88 21.546 44.904 ;
    END
  END q[309]
  PIN q[30]
    DIRECTION OUTPUT ;
    USE SIGNAL ;
    PORT
      LAYER M4 ;
        RECT  21.462 9.216 21.546 9.24 ;
    END
  END q[30]
  PIN q[310]
    DIRECTION OUTPUT ;
    USE SIGNAL ;
    PORT
      LAYER M4 ;
        RECT  21.462 45.024 21.546 45.048 ;
    END
  END q[310]
  PIN q[311]
    DIRECTION OUTPUT ;
    USE SIGNAL ;
    PORT
      LAYER M4 ;
        RECT  21.462 45.12 21.546 45.144 ;
    END
  END q[311]
  PIN q[312]
    DIRECTION OUTPUT ;
    USE SIGNAL ;
    PORT
      LAYER M4 ;
        RECT  21.462 45.264 21.546 45.288 ;
    END
  END q[312]
  PIN q[313]
    DIRECTION OUTPUT ;
    USE SIGNAL ;
    PORT
      LAYER M4 ;
        RECT  21.462 45.408 21.546 45.432 ;
    END
  END q[313]
  PIN q[314]
    DIRECTION OUTPUT ;
    USE SIGNAL ;
    PORT
      LAYER M4 ;
        RECT  21.462 45.504 21.546 45.528 ;
    END
  END q[314]
  PIN q[315]
    DIRECTION OUTPUT ;
    USE SIGNAL ;
    PORT
      LAYER M4 ;
        RECT  21.462 45.648 21.546 45.672 ;
    END
  END q[315]
  PIN q[316]
    DIRECTION OUTPUT ;
    USE SIGNAL ;
    PORT
      LAYER M4 ;
        RECT  21.462 45.792 21.546 45.816 ;
    END
  END q[316]
  PIN q[317]
    DIRECTION OUTPUT ;
    USE SIGNAL ;
    PORT
      LAYER M4 ;
        RECT  21.462 45.888 21.546 45.912 ;
    END
  END q[317]
  PIN q[318]
    DIRECTION OUTPUT ;
    USE SIGNAL ;
    PORT
      LAYER M4 ;
        RECT  21.462 46.032 21.546 46.056 ;
    END
  END q[318]
  PIN q[319]
    DIRECTION OUTPUT ;
    USE SIGNAL ;
    PORT
      LAYER M4 ;
        RECT  21.462 46.176 21.546 46.2 ;
    END
    PORT
      LAYER M4 ;
        RECT  21.516 46.176 21.593 46.2 ;
    END
  END q[319]
  PIN q[31]
    DIRECTION OUTPUT ;
    USE SIGNAL ;
    PORT
      LAYER M4 ;
        RECT  21.462 9.36 21.546 9.384 ;
    END
  END q[31]
  PIN q[320]
    DIRECTION OUTPUT ;
    USE SIGNAL ;
    PORT
      LAYER M4 ;
        RECT  21.462 46.272 21.546 46.296 ;
    END
  END q[320]
  PIN q[321]
    DIRECTION OUTPUT ;
    USE SIGNAL ;
    PORT
      LAYER M4 ;
        RECT  21.462 46.416 21.546 46.44 ;
    END
  END q[321]
  PIN q[322]
    DIRECTION OUTPUT ;
    USE SIGNAL ;
    PORT
      LAYER M4 ;
        RECT  21.462 46.56 21.546 46.584 ;
    END
  END q[322]
  PIN q[323]
    DIRECTION OUTPUT ;
    USE SIGNAL ;
    PORT
      LAYER M4 ;
        RECT  21.462 46.656 21.546 46.68 ;
    END
  END q[323]
  PIN q[324]
    DIRECTION OUTPUT ;
    USE SIGNAL ;
    PORT
      LAYER M4 ;
        RECT  21.462 46.8 21.546 46.824 ;
    END
  END q[324]
  PIN q[325]
    DIRECTION OUTPUT ;
    USE SIGNAL ;
    PORT
      LAYER M4 ;
        RECT  21.462 46.944 21.546 46.968 ;
    END
  END q[325]
  PIN q[326]
    DIRECTION OUTPUT ;
    USE SIGNAL ;
    PORT
      LAYER M4 ;
        RECT  21.462 47.04 21.546 47.064 ;
    END
  END q[326]
  PIN q[327]
    DIRECTION OUTPUT ;
    USE SIGNAL ;
    PORT
      LAYER M4 ;
        RECT  21.462 47.184 21.546 47.208 ;
    END
  END q[327]
  PIN q[328]
    DIRECTION OUTPUT ;
    USE SIGNAL ;
    PORT
      LAYER M4 ;
        RECT  21.462 47.328 21.546 47.352 ;
    END
  END q[328]
  PIN q[329]
    DIRECTION OUTPUT ;
    USE SIGNAL ;
    PORT
      LAYER M4 ;
        RECT  21.462 47.424 21.546 47.448 ;
    END
  END q[329]
  PIN q[32]
    DIRECTION OUTPUT ;
    USE SIGNAL ;
    PORT
      LAYER M4 ;
        RECT  21.462 9.456 21.546 9.48 ;
    END
  END q[32]
  PIN q[330]
    DIRECTION OUTPUT ;
    USE SIGNAL ;
    PORT
      LAYER M4 ;
        RECT  21.462 47.568 21.546 47.592 ;
    END
  END q[330]
  PIN q[331]
    DIRECTION OUTPUT ;
    USE SIGNAL ;
    PORT
      LAYER M4 ;
        RECT  21.462 47.712 21.546 47.736 ;
    END
  END q[331]
  PIN q[332]
    DIRECTION OUTPUT ;
    USE SIGNAL ;
    PORT
      LAYER M4 ;
        RECT  21.462 47.808 21.546 47.832 ;
    END
  END q[332]
  PIN q[333]
    DIRECTION OUTPUT ;
    USE SIGNAL ;
    PORT
      LAYER M4 ;
        RECT  21.462 47.952 21.546 47.976 ;
    END
  END q[333]
  PIN q[334]
    DIRECTION OUTPUT ;
    USE SIGNAL ;
    PORT
      LAYER M4 ;
        RECT  21.462 48.096 21.546 48.12 ;
    END
  END q[334]
  PIN q[335]
    DIRECTION OUTPUT ;
    USE SIGNAL ;
    PORT
      LAYER M4 ;
        RECT  21.462 48.192 21.546 48.216 ;
    END
  END q[335]
  PIN q[336]
    DIRECTION OUTPUT ;
    USE SIGNAL ;
    PORT
      LAYER M4 ;
        RECT  21.462 48.336 21.546 48.36 ;
    END
  END q[336]
  PIN q[337]
    DIRECTION OUTPUT ;
    USE SIGNAL ;
    PORT
      LAYER M4 ;
        RECT  21.462 48.48 21.546 48.504 ;
    END
  END q[337]
  PIN q[338]
    DIRECTION OUTPUT ;
    USE SIGNAL ;
    PORT
      LAYER M4 ;
        RECT  21.462 48.576 21.546 48.6 ;
    END
  END q[338]
  PIN q[339]
    DIRECTION OUTPUT ;
    USE SIGNAL ;
    PORT
      LAYER M4 ;
        RECT  21.462 48.72 21.546 48.744 ;
    END
  END q[339]
  PIN q[33]
    DIRECTION OUTPUT ;
    USE SIGNAL ;
    PORT
      LAYER M4 ;
        RECT  21.462 9.6 21.546 9.624 ;
    END
  END q[33]
  PIN q[340]
    DIRECTION OUTPUT ;
    USE SIGNAL ;
    PORT
      LAYER M4 ;
        RECT  21.462 48.864 21.546 48.888 ;
    END
  END q[340]
  PIN q[341]
    DIRECTION OUTPUT ;
    USE SIGNAL ;
    PORT
      LAYER M4 ;
        RECT  21.462 48.96 21.546 48.984 ;
    END
  END q[341]
  PIN q[342]
    DIRECTION OUTPUT ;
    USE SIGNAL ;
    PORT
      LAYER M4 ;
        RECT  21.462 49.104 21.546 49.128 ;
    END
  END q[342]
  PIN q[343]
    DIRECTION OUTPUT ;
    USE SIGNAL ;
    PORT
      LAYER M4 ;
        RECT  21.462 49.248 21.546 49.272 ;
    END
  END q[343]
  PIN q[344]
    DIRECTION OUTPUT ;
    USE SIGNAL ;
    PORT
      LAYER M4 ;
        RECT  21.462 49.344 21.546 49.368 ;
    END
  END q[344]
  PIN q[345]
    DIRECTION OUTPUT ;
    USE SIGNAL ;
    PORT
      LAYER M4 ;
        RECT  21.462 49.488 21.546 49.512 ;
    END
  END q[345]
  PIN q[346]
    DIRECTION OUTPUT ;
    USE SIGNAL ;
    PORT
      LAYER M4 ;
        RECT  21.462 49.632 21.546 49.656 ;
    END
  END q[346]
  PIN q[347]
    DIRECTION OUTPUT ;
    USE SIGNAL ;
    PORT
      LAYER M4 ;
        RECT  21.462 49.728 21.546 49.752 ;
    END
  END q[347]
  PIN q[348]
    DIRECTION OUTPUT ;
    USE SIGNAL ;
    PORT
      LAYER M4 ;
        RECT  21.462 49.872 21.546 49.896 ;
    END
  END q[348]
  PIN q[349]
    DIRECTION OUTPUT ;
    USE SIGNAL ;
    PORT
      LAYER M4 ;
        RECT  21.462 50.016 21.546 50.04 ;
    END
  END q[349]
  PIN q[34]
    DIRECTION OUTPUT ;
    USE SIGNAL ;
    PORT
      LAYER M4 ;
        RECT  21.462 9.744 21.546 9.768 ;
    END
  END q[34]
  PIN q[350]
    DIRECTION OUTPUT ;
    USE SIGNAL ;
    PORT
      LAYER M4 ;
        RECT  21.462 50.112 21.546 50.136 ;
    END
  END q[350]
  PIN q[351]
    DIRECTION OUTPUT ;
    USE SIGNAL ;
    PORT
      LAYER M4 ;
        RECT  21.462 50.256 21.546 50.28 ;
    END
  END q[351]
  PIN q[352]
    DIRECTION OUTPUT ;
    USE SIGNAL ;
    PORT
      LAYER M4 ;
        RECT  21.462 50.4 21.546 50.424 ;
    END
  END q[352]
  PIN q[353]
    DIRECTION OUTPUT ;
    USE SIGNAL ;
    PORT
      LAYER M4 ;
        RECT  21.462 50.496 21.546 50.52 ;
    END
  END q[353]
  PIN q[354]
    DIRECTION OUTPUT ;
    USE SIGNAL ;
    PORT
      LAYER M4 ;
        RECT  21.462 50.64 21.546 50.664 ;
    END
  END q[354]
  PIN q[355]
    DIRECTION OUTPUT ;
    USE SIGNAL ;
    PORT
      LAYER M4 ;
        RECT  21.462 50.784 21.546 50.808 ;
    END
  END q[355]
  PIN q[356]
    DIRECTION OUTPUT ;
    USE SIGNAL ;
    PORT
      LAYER M4 ;
        RECT  21.462 50.88 21.546 50.904 ;
    END
  END q[356]
  PIN q[357]
    DIRECTION OUTPUT ;
    USE SIGNAL ;
    PORT
      LAYER M4 ;
        RECT  21.462 51.024 21.546 51.048 ;
    END
  END q[357]
  PIN q[358]
    DIRECTION OUTPUT ;
    USE SIGNAL ;
    PORT
      LAYER M4 ;
        RECT  21.462 51.168 21.546 51.192 ;
    END
  END q[358]
  PIN q[359]
    DIRECTION OUTPUT ;
    USE SIGNAL ;
    PORT
      LAYER M4 ;
        RECT  21.462 51.264 21.546 51.288 ;
    END
  END q[359]
  PIN q[35]
    DIRECTION OUTPUT ;
    USE SIGNAL ;
    PORT
      LAYER M4 ;
        RECT  21.462 9.84 21.546 9.864 ;
    END
  END q[35]
  PIN q[360]
    DIRECTION OUTPUT ;
    USE SIGNAL ;
    PORT
      LAYER M4 ;
        RECT  21.462 51.408 21.546 51.432 ;
    END
  END q[360]
  PIN q[361]
    DIRECTION OUTPUT ;
    USE SIGNAL ;
    PORT
      LAYER M4 ;
        RECT  21.462 51.504 21.546 51.528 ;
    END
  END q[361]
  PIN q[362]
    DIRECTION OUTPUT ;
    USE SIGNAL ;
    PORT
      LAYER M4 ;
        RECT  21.462 51.648 21.546 51.672 ;
    END
  END q[362]
  PIN q[363]
    DIRECTION OUTPUT ;
    USE SIGNAL ;
    PORT
      LAYER M4 ;
        RECT  21.462 51.792 21.546 51.816 ;
    END
  END q[363]
  PIN q[364]
    DIRECTION OUTPUT ;
    USE SIGNAL ;
    PORT
      LAYER M4 ;
        RECT  21.462 51.888 21.546 51.912 ;
    END
  END q[364]
  PIN q[365]
    DIRECTION OUTPUT ;
    USE SIGNAL ;
    PORT
      LAYER M4 ;
        RECT  21.462 52.032 21.546 52.056 ;
    END
  END q[365]
  PIN q[366]
    DIRECTION OUTPUT ;
    USE SIGNAL ;
    PORT
      LAYER M4 ;
        RECT  21.462 52.176 21.546 52.2 ;
    END
  END q[366]
  PIN q[367]
    DIRECTION OUTPUT ;
    USE SIGNAL ;
    PORT
      LAYER M4 ;
        RECT  21.462 52.272 21.546 52.296 ;
    END
  END q[367]
  PIN q[368]
    DIRECTION OUTPUT ;
    USE SIGNAL ;
    PORT
      LAYER M4 ;
        RECT  21.462 52.416 21.546 52.44 ;
    END
  END q[368]
  PIN q[369]
    DIRECTION OUTPUT ;
    USE SIGNAL ;
    PORT
      LAYER M4 ;
        RECT  21.462 52.56 21.546 52.584 ;
    END
  END q[369]
  PIN q[36]
    DIRECTION OUTPUT ;
    USE SIGNAL ;
    PORT
      LAYER M4 ;
        RECT  21.462 9.984 21.546 10.008 ;
    END
  END q[36]
  PIN q[370]
    DIRECTION OUTPUT ;
    USE SIGNAL ;
    PORT
      LAYER M4 ;
        RECT  21.462 52.656 21.546 52.68 ;
    END
  END q[370]
  PIN q[371]
    DIRECTION OUTPUT ;
    USE SIGNAL ;
    PORT
      LAYER M4 ;
        RECT  21.462 52.8 21.546 52.824 ;
    END
  END q[371]
  PIN q[372]
    DIRECTION OUTPUT ;
    USE SIGNAL ;
    PORT
      LAYER M4 ;
        RECT  21.462 52.944 21.546 52.968 ;
    END
  END q[372]
  PIN q[373]
    DIRECTION OUTPUT ;
    USE SIGNAL ;
    PORT
      LAYER M4 ;
        RECT  21.462 53.04 21.546 53.064 ;
    END
  END q[373]
  PIN q[374]
    DIRECTION OUTPUT ;
    USE SIGNAL ;
    PORT
      LAYER M4 ;
        RECT  21.462 53.184 21.546 53.208 ;
    END
  END q[374]
  PIN q[375]
    DIRECTION OUTPUT ;
    USE SIGNAL ;
    PORT
      LAYER M4 ;
        RECT  21.462 53.328 21.546 53.352 ;
    END
  END q[375]
  PIN q[376]
    DIRECTION OUTPUT ;
    USE SIGNAL ;
    PORT
      LAYER M4 ;
        RECT  21.462 53.424 21.546 53.448 ;
    END
  END q[376]
  PIN q[377]
    DIRECTION OUTPUT ;
    USE SIGNAL ;
    PORT
      LAYER M4 ;
        RECT  21.462 53.568 21.546 53.592 ;
    END
  END q[377]
  PIN q[378]
    DIRECTION OUTPUT ;
    USE SIGNAL ;
    PORT
      LAYER M4 ;
        RECT  21.462 53.712 21.546 53.736 ;
    END
  END q[378]
  PIN q[379]
    DIRECTION OUTPUT ;
    USE SIGNAL ;
    PORT
      LAYER M4 ;
        RECT  21.462 53.808 21.546 53.832 ;
    END
  END q[379]
  PIN q[37]
    DIRECTION OUTPUT ;
    USE SIGNAL ;
    PORT
      LAYER M4 ;
        RECT  21.462 10.128 21.546 10.152 ;
    END
  END q[37]
  PIN q[380]
    DIRECTION OUTPUT ;
    USE SIGNAL ;
    PORT
      LAYER M4 ;
        RECT  21.462 53.952 21.546 53.976 ;
    END
  END q[380]
  PIN q[381]
    DIRECTION OUTPUT ;
    USE SIGNAL ;
    PORT
      LAYER M4 ;
        RECT  21.462 54.096 21.546 54.12 ;
    END
  END q[381]
  PIN q[382]
    DIRECTION OUTPUT ;
    USE SIGNAL ;
    PORT
      LAYER M4 ;
        RECT  21.462 54.192 21.546 54.216 ;
    END
  END q[382]
  PIN q[383]
    DIRECTION OUTPUT ;
    USE SIGNAL ;
    PORT
      LAYER M4 ;
        RECT  21.462 54.336 21.546 54.36 ;
    END
  END q[383]
  PIN q[384]
    DIRECTION OUTPUT ;
    USE SIGNAL ;
    PORT
      LAYER M4 ;
        RECT  21.462 54.48 21.546 54.504 ;
    END
  END q[384]
  PIN q[385]
    DIRECTION OUTPUT ;
    USE SIGNAL ;
    PORT
      LAYER M4 ;
        RECT  21.462 54.576 21.546 54.6 ;
    END
  END q[385]
  PIN q[386]
    DIRECTION OUTPUT ;
    USE SIGNAL ;
    PORT
      LAYER M4 ;
        RECT  21.462 54.72 21.546 54.744 ;
    END
  END q[386]
  PIN q[387]
    DIRECTION OUTPUT ;
    USE SIGNAL ;
    PORT
      LAYER M4 ;
        RECT  21.462 54.864 21.546 54.888 ;
    END
  END q[387]
  PIN q[388]
    DIRECTION OUTPUT ;
    USE SIGNAL ;
    PORT
      LAYER M4 ;
        RECT  21.462 54.96 21.546 54.984 ;
    END
  END q[388]
  PIN q[389]
    DIRECTION OUTPUT ;
    USE SIGNAL ;
    PORT
      LAYER M4 ;
        RECT  21.462 55.104 21.546 55.128 ;
    END
  END q[389]
  PIN q[38]
    DIRECTION OUTPUT ;
    USE SIGNAL ;
    PORT
      LAYER M4 ;
        RECT  21.462 10.224 21.546 10.248 ;
    END
  END q[38]
  PIN q[390]
    DIRECTION OUTPUT ;
    USE SIGNAL ;
    PORT
      LAYER M4 ;
        RECT  21.462 55.248 21.546 55.272 ;
    END
  END q[390]
  PIN q[391]
    DIRECTION OUTPUT ;
    USE SIGNAL ;
    PORT
      LAYER M4 ;
        RECT  21.462 55.344 21.546 55.368 ;
    END
  END q[391]
  PIN q[392]
    DIRECTION OUTPUT ;
    USE SIGNAL ;
    PORT
      LAYER M4 ;
        RECT  21.462 55.488 21.546 55.512 ;
    END
  END q[392]
  PIN q[393]
    DIRECTION OUTPUT ;
    USE SIGNAL ;
    PORT
      LAYER M4 ;
        RECT  21.462 55.632 21.546 55.656 ;
    END
  END q[393]
  PIN q[394]
    DIRECTION OUTPUT ;
    USE SIGNAL ;
    PORT
      LAYER M4 ;
        RECT  21.462 55.728 21.546 55.752 ;
    END
  END q[394]
  PIN q[395]
    DIRECTION OUTPUT ;
    USE SIGNAL ;
    PORT
      LAYER M4 ;
        RECT  21.462 55.872 21.546 55.896 ;
    END
  END q[395]
  PIN q[396]
    DIRECTION OUTPUT ;
    USE SIGNAL ;
    PORT
      LAYER M4 ;
        RECT  21.462 56.016 21.546 56.04 ;
    END
  END q[396]
  PIN q[397]
    DIRECTION OUTPUT ;
    USE SIGNAL ;
    PORT
      LAYER M4 ;
        RECT  21.462 56.112 21.546 56.136 ;
    END
  END q[397]
  PIN q[398]
    DIRECTION OUTPUT ;
    USE SIGNAL ;
    PORT
      LAYER M4 ;
        RECT  21.462 56.256 21.546 56.28 ;
    END
  END q[398]
  PIN q[399]
    DIRECTION OUTPUT ;
    USE SIGNAL ;
    PORT
      LAYER M4 ;
        RECT  21.462 56.4 21.546 56.424 ;
    END
  END q[399]
  PIN q[39]
    DIRECTION OUTPUT ;
    USE SIGNAL ;
    PORT
      LAYER M4 ;
        RECT  21.462 10.368 21.546 10.392 ;
    END
  END q[39]
  PIN q[3]
    DIRECTION OUTPUT ;
    USE SIGNAL ;
    PORT
      LAYER M4 ;
        RECT  21.462 5.76 21.546 5.784 ;
    END
  END q[3]
  PIN q[400]
    DIRECTION OUTPUT ;
    USE SIGNAL ;
    PORT
      LAYER M4 ;
        RECT  21.462 56.496 21.546 56.52 ;
    END
  END q[400]
  PIN q[401]
    DIRECTION OUTPUT ;
    USE SIGNAL ;
    PORT
      LAYER M4 ;
        RECT  21.462 56.64 21.546 56.664 ;
    END
  END q[401]
  PIN q[402]
    DIRECTION OUTPUT ;
    USE SIGNAL ;
    PORT
      LAYER M4 ;
        RECT  21.462 56.784 21.546 56.808 ;
    END
  END q[402]
  PIN q[403]
    DIRECTION OUTPUT ;
    USE SIGNAL ;
    PORT
      LAYER M4 ;
        RECT  21.462 56.88 21.546 56.904 ;
    END
  END q[403]
  PIN q[404]
    DIRECTION OUTPUT ;
    USE SIGNAL ;
    PORT
      LAYER M4 ;
        RECT  21.462 57.024 21.546 57.048 ;
    END
  END q[404]
  PIN q[405]
    DIRECTION OUTPUT ;
    USE SIGNAL ;
    PORT
      LAYER M4 ;
        RECT  21.462 57.168 21.546 57.192 ;
    END
  END q[405]
  PIN q[406]
    DIRECTION OUTPUT ;
    USE SIGNAL ;
    PORT
      LAYER M4 ;
        RECT  21.462 57.264 21.546 57.288 ;
    END
  END q[406]
  PIN q[407]
    DIRECTION OUTPUT ;
    USE SIGNAL ;
    PORT
      LAYER M4 ;
        RECT  21.462 57.408 21.546 57.432 ;
    END
  END q[407]
  PIN q[408]
    DIRECTION OUTPUT ;
    USE SIGNAL ;
    PORT
      LAYER M4 ;
        RECT  21.462 57.552 21.546 57.576 ;
    END
  END q[408]
  PIN q[409]
    DIRECTION OUTPUT ;
    USE SIGNAL ;
    PORT
      LAYER M4 ;
        RECT  21.462 57.648 21.546 57.672 ;
    END
  END q[409]
  PIN q[40]
    DIRECTION OUTPUT ;
    USE SIGNAL ;
    PORT
      LAYER M4 ;
        RECT  21.462 10.512 21.546 10.536 ;
    END
  END q[40]
  PIN q[410]
    DIRECTION OUTPUT ;
    USE SIGNAL ;
    PORT
      LAYER M4 ;
        RECT  21.462 57.792 21.546 57.816 ;
    END
  END q[410]
  PIN q[411]
    DIRECTION OUTPUT ;
    USE SIGNAL ;
    PORT
      LAYER M4 ;
        RECT  21.462 57.936 21.546 57.96 ;
    END
  END q[411]
  PIN q[412]
    DIRECTION OUTPUT ;
    USE SIGNAL ;
    PORT
      LAYER M4 ;
        RECT  21.462 58.032 21.546 58.056 ;
    END
  END q[412]
  PIN q[413]
    DIRECTION OUTPUT ;
    USE SIGNAL ;
    PORT
      LAYER M4 ;
        RECT  21.462 58.176 21.546 58.2 ;
    END
  END q[413]
  PIN q[414]
    DIRECTION OUTPUT ;
    USE SIGNAL ;
    PORT
      LAYER M4 ;
        RECT  21.462 58.32 21.546 58.344 ;
    END
  END q[414]
  PIN q[415]
    DIRECTION OUTPUT ;
    USE SIGNAL ;
    PORT
      LAYER M4 ;
        RECT  21.462 58.416 21.546 58.44 ;
    END
  END q[415]
  PIN q[416]
    DIRECTION OUTPUT ;
    USE SIGNAL ;
    PORT
      LAYER M4 ;
        RECT  21.462 58.56 21.546 58.584 ;
    END
  END q[416]
  PIN q[417]
    DIRECTION OUTPUT ;
    USE SIGNAL ;
    PORT
      LAYER M4 ;
        RECT  21.462 58.704 21.546 58.728 ;
    END
  END q[417]
  PIN q[418]
    DIRECTION OUTPUT ;
    USE SIGNAL ;
    PORT
      LAYER M4 ;
        RECT  21.462 58.8 21.546 58.824 ;
    END
  END q[418]
  PIN q[419]
    DIRECTION OUTPUT ;
    USE SIGNAL ;
    PORT
      LAYER M4 ;
        RECT  21.462 58.944 21.546 58.968 ;
    END
  END q[419]
  PIN q[41]
    DIRECTION OUTPUT ;
    USE SIGNAL ;
    PORT
      LAYER M4 ;
        RECT  21.462 10.608 21.546 10.632 ;
    END
  END q[41]
  PIN q[420]
    DIRECTION OUTPUT ;
    USE SIGNAL ;
    PORT
      LAYER M4 ;
        RECT  21.462 59.088 21.546 59.112 ;
    END
  END q[420]
  PIN q[421]
    DIRECTION OUTPUT ;
    USE SIGNAL ;
    PORT
      LAYER M4 ;
        RECT  21.462 59.184 21.546 59.208 ;
    END
  END q[421]
  PIN q[422]
    DIRECTION OUTPUT ;
    USE SIGNAL ;
    PORT
      LAYER M4 ;
        RECT  21.462 59.328 21.546 59.352 ;
    END
  END q[422]
  PIN q[423]
    DIRECTION OUTPUT ;
    USE SIGNAL ;
    PORT
      LAYER M4 ;
        RECT  21.462 59.472 21.546 59.496 ;
    END
  END q[423]
  PIN q[424]
    DIRECTION OUTPUT ;
    USE SIGNAL ;
    PORT
      LAYER M4 ;
        RECT  21.462 59.568 21.546 59.592 ;
    END
  END q[424]
  PIN q[425]
    DIRECTION OUTPUT ;
    USE SIGNAL ;
    PORT
      LAYER M4 ;
        RECT  21.462 59.712 21.546 59.736 ;
    END
  END q[425]
  PIN q[426]
    DIRECTION OUTPUT ;
    USE SIGNAL ;
    PORT
      LAYER M4 ;
        RECT  21.462 59.856 21.546 59.88 ;
    END
  END q[426]
  PIN q[427]
    DIRECTION OUTPUT ;
    USE SIGNAL ;
    PORT
      LAYER M4 ;
        RECT  21.462 59.952 21.546 59.976 ;
    END
  END q[427]
  PIN q[428]
    DIRECTION OUTPUT ;
    USE SIGNAL ;
    PORT
      LAYER M4 ;
        RECT  21.462 60.096 21.546 60.12 ;
    END
  END q[428]
  PIN q[429]
    DIRECTION OUTPUT ;
    USE SIGNAL ;
    PORT
      LAYER M4 ;
        RECT  21.462 60.24 21.546 60.264 ;
    END
  END q[429]
  PIN q[42]
    DIRECTION OUTPUT ;
    USE SIGNAL ;
    PORT
      LAYER M4 ;
        RECT  21.462 10.752 21.546 10.776 ;
    END
  END q[42]
  PIN q[430]
    DIRECTION OUTPUT ;
    USE SIGNAL ;
    PORT
      LAYER M4 ;
        RECT  21.462 60.336 21.546 60.36 ;
    END
  END q[430]
  PIN q[431]
    DIRECTION OUTPUT ;
    USE SIGNAL ;
    PORT
      LAYER M4 ;
        RECT  21.462 60.48 21.546 60.504 ;
    END
  END q[431]
  PIN q[432]
    DIRECTION OUTPUT ;
    USE SIGNAL ;
    PORT
      LAYER M4 ;
        RECT  21.462 60.624 21.546 60.648 ;
    END
  END q[432]
  PIN q[433]
    DIRECTION OUTPUT ;
    USE SIGNAL ;
    PORT
      LAYER M4 ;
        RECT  21.462 60.72 21.546 60.744 ;
    END
  END q[433]
  PIN q[434]
    DIRECTION OUTPUT ;
    USE SIGNAL ;
    PORT
      LAYER M4 ;
        RECT  21.462 60.864 21.546 60.888 ;
    END
  END q[434]
  PIN q[435]
    DIRECTION OUTPUT ;
    USE SIGNAL ;
    PORT
      LAYER M4 ;
        RECT  21.462 61.008 21.546 61.032 ;
    END
  END q[435]
  PIN q[436]
    DIRECTION OUTPUT ;
    USE SIGNAL ;
    PORT
      LAYER M4 ;
        RECT  21.462 61.104 21.546 61.128 ;
    END
  END q[436]
  PIN q[437]
    DIRECTION OUTPUT ;
    USE SIGNAL ;
    PORT
      LAYER M4 ;
        RECT  21.462 61.248 21.546 61.272 ;
    END
  END q[437]
  PIN q[438]
    DIRECTION OUTPUT ;
    USE SIGNAL ;
    PORT
      LAYER M4 ;
        RECT  21.462 61.392 21.546 61.416 ;
    END
  END q[438]
  PIN q[439]
    DIRECTION OUTPUT ;
    USE SIGNAL ;
    PORT
      LAYER M4 ;
        RECT  21.462 61.488 21.546 61.512 ;
    END
  END q[439]
  PIN q[43]
    DIRECTION OUTPUT ;
    USE SIGNAL ;
    PORT
      LAYER M4 ;
        RECT  21.462 10.896 21.546 10.92 ;
    END
  END q[43]
  PIN q[440]
    DIRECTION OUTPUT ;
    USE SIGNAL ;
    PORT
      LAYER M4 ;
        RECT  21.462 61.632 21.546 61.656 ;
    END
  END q[440]
  PIN q[441]
    DIRECTION OUTPUT ;
    USE SIGNAL ;
    PORT
      LAYER M4 ;
        RECT  21.462 61.776 21.546 61.8 ;
    END
  END q[441]
  PIN q[442]
    DIRECTION OUTPUT ;
    USE SIGNAL ;
    PORT
      LAYER M4 ;
        RECT  21.462 61.872 21.546 61.896 ;
    END
  END q[442]
  PIN q[443]
    DIRECTION OUTPUT ;
    USE SIGNAL ;
    PORT
      LAYER M4 ;
        RECT  21.462 62.016 21.546 62.04 ;
    END
  END q[443]
  PIN q[444]
    DIRECTION OUTPUT ;
    USE SIGNAL ;
    PORT
      LAYER M4 ;
        RECT  21.462 62.112 21.546 62.136 ;
    END
  END q[444]
  PIN q[445]
    DIRECTION OUTPUT ;
    USE SIGNAL ;
    PORT
      LAYER M4 ;
        RECT  21.462 62.256 21.546 62.28 ;
    END
  END q[445]
  PIN q[446]
    DIRECTION OUTPUT ;
    USE SIGNAL ;
    PORT
      LAYER M4 ;
        RECT  21.462 62.4 21.546 62.424 ;
    END
  END q[446]
  PIN q[447]
    DIRECTION OUTPUT ;
    USE SIGNAL ;
    PORT
      LAYER M4 ;
        RECT  21.462 62.496 21.546 62.52 ;
    END
  END q[447]
  PIN q[448]
    DIRECTION OUTPUT ;
    USE SIGNAL ;
    PORT
      LAYER M4 ;
        RECT  21.462 62.64 21.546 62.664 ;
    END
  END q[448]
  PIN q[449]
    DIRECTION OUTPUT ;
    USE SIGNAL ;
    PORT
      LAYER M4 ;
        RECT  21.462 62.784 21.546 62.808 ;
    END
  END q[449]
  PIN q[44]
    DIRECTION OUTPUT ;
    USE SIGNAL ;
    PORT
      LAYER M4 ;
        RECT  21.462 10.992 21.546 11.016 ;
    END
  END q[44]
  PIN q[450]
    DIRECTION OUTPUT ;
    USE SIGNAL ;
    PORT
      LAYER M4 ;
        RECT  21.462 62.88 21.546 62.904 ;
    END
  END q[450]
  PIN q[451]
    DIRECTION OUTPUT ;
    USE SIGNAL ;
    PORT
      LAYER M4 ;
        RECT  21.462 63.024 21.546 63.048 ;
    END
  END q[451]
  PIN q[452]
    DIRECTION OUTPUT ;
    USE SIGNAL ;
    PORT
      LAYER M4 ;
        RECT  21.462 63.168 21.546 63.192 ;
    END
  END q[452]
  PIN q[453]
    DIRECTION OUTPUT ;
    USE SIGNAL ;
    PORT
      LAYER M4 ;
        RECT  21.462 63.264 21.546 63.288 ;
    END
  END q[453]
  PIN q[454]
    DIRECTION OUTPUT ;
    USE SIGNAL ;
    PORT
      LAYER M4 ;
        RECT  21.462 63.408 21.546 63.432 ;
    END
  END q[454]
  PIN q[455]
    DIRECTION OUTPUT ;
    USE SIGNAL ;
    PORT
      LAYER M4 ;
        RECT  21.462 63.552 21.546 63.576 ;
    END
  END q[455]
  PIN q[456]
    DIRECTION OUTPUT ;
    USE SIGNAL ;
    PORT
      LAYER M4 ;
        RECT  21.462 63.648 21.546 63.672 ;
    END
  END q[456]
  PIN q[457]
    DIRECTION OUTPUT ;
    USE SIGNAL ;
    PORT
      LAYER M4 ;
        RECT  21.462 63.792 21.546 63.816 ;
    END
  END q[457]
  PIN q[458]
    DIRECTION OUTPUT ;
    USE SIGNAL ;
    PORT
      LAYER M4 ;
        RECT  21.462 63.936 21.546 63.96 ;
    END
  END q[458]
  PIN q[459]
    DIRECTION OUTPUT ;
    USE SIGNAL ;
    PORT
      LAYER M4 ;
        RECT  21.462 64.032 21.546 64.056 ;
    END
  END q[459]
  PIN q[45]
    DIRECTION OUTPUT ;
    USE SIGNAL ;
    PORT
      LAYER M4 ;
        RECT  21.462 11.136 21.546 11.16 ;
    END
  END q[45]
  PIN q[460]
    DIRECTION OUTPUT ;
    USE SIGNAL ;
    PORT
      LAYER M4 ;
        RECT  21.462 64.176 21.546 64.2 ;
    END
  END q[460]
  PIN q[461]
    DIRECTION OUTPUT ;
    USE SIGNAL ;
    PORT
      LAYER M4 ;
        RECT  21.462 64.32 21.546 64.344 ;
    END
  END q[461]
  PIN q[462]
    DIRECTION OUTPUT ;
    USE SIGNAL ;
    PORT
      LAYER M4 ;
        RECT  21.462 64.416 21.546 64.44 ;
    END
  END q[462]
  PIN q[463]
    DIRECTION OUTPUT ;
    USE SIGNAL ;
    PORT
      LAYER M4 ;
        RECT  21.462 64.56 21.546 64.584 ;
    END
  END q[463]
  PIN q[464]
    DIRECTION OUTPUT ;
    USE SIGNAL ;
    PORT
      LAYER M4 ;
        RECT  21.462 64.704 21.546 64.728 ;
    END
  END q[464]
  PIN q[465]
    DIRECTION OUTPUT ;
    USE SIGNAL ;
    PORT
      LAYER M4 ;
        RECT  21.462 64.8 21.546 64.824 ;
    END
  END q[465]
  PIN q[466]
    DIRECTION OUTPUT ;
    USE SIGNAL ;
    PORT
      LAYER M4 ;
        RECT  21.462 64.944 21.546 64.968 ;
    END
  END q[466]
  PIN q[467]
    DIRECTION OUTPUT ;
    USE SIGNAL ;
    PORT
      LAYER M4 ;
        RECT  21.462 65.088 21.546 65.112 ;
    END
  END q[467]
  PIN q[468]
    DIRECTION OUTPUT ;
    USE SIGNAL ;
    PORT
      LAYER M4 ;
        RECT  21.462 65.184 21.546 65.208 ;
    END
  END q[468]
  PIN q[469]
    DIRECTION OUTPUT ;
    USE SIGNAL ;
    PORT
      LAYER M4 ;
        RECT  21.462 65.328 21.546 65.352 ;
    END
  END q[469]
  PIN q[46]
    DIRECTION OUTPUT ;
    USE SIGNAL ;
    PORT
      LAYER M4 ;
        RECT  21.462 11.28 21.546 11.304 ;
    END
  END q[46]
  PIN q[470]
    DIRECTION OUTPUT ;
    USE SIGNAL ;
    PORT
      LAYER M4 ;
        RECT  21.462 65.472 21.546 65.496 ;
    END
  END q[470]
  PIN q[471]
    DIRECTION OUTPUT ;
    USE SIGNAL ;
    PORT
      LAYER M4 ;
        RECT  21.462 65.568 21.546 65.592 ;
    END
  END q[471]
  PIN q[472]
    DIRECTION OUTPUT ;
    USE SIGNAL ;
    PORT
      LAYER M4 ;
        RECT  21.462 65.712 21.546 65.736 ;
    END
  END q[472]
  PIN q[473]
    DIRECTION OUTPUT ;
    USE SIGNAL ;
    PORT
      LAYER M4 ;
        RECT  21.462 65.856 21.546 65.88 ;
    END
  END q[473]
  PIN q[474]
    DIRECTION OUTPUT ;
    USE SIGNAL ;
    PORT
      LAYER M4 ;
        RECT  21.462 65.952 21.546 65.976 ;
    END
  END q[474]
  PIN q[475]
    DIRECTION OUTPUT ;
    USE SIGNAL ;
    PORT
      LAYER M4 ;
        RECT  21.462 66.096 21.546 66.12 ;
    END
  END q[475]
  PIN q[476]
    DIRECTION OUTPUT ;
    USE SIGNAL ;
    PORT
      LAYER M4 ;
        RECT  21.462 66.24 21.546 66.264 ;
    END
  END q[476]
  PIN q[477]
    DIRECTION OUTPUT ;
    USE SIGNAL ;
    PORT
      LAYER M4 ;
        RECT  21.462 66.336 21.546 66.36 ;
    END
  END q[477]
  PIN q[478]
    DIRECTION OUTPUT ;
    USE SIGNAL ;
    PORT
      LAYER M4 ;
        RECT  21.462 66.48 21.546 66.504 ;
    END
  END q[478]
  PIN q[479]
    DIRECTION OUTPUT ;
    USE SIGNAL ;
    PORT
      LAYER M4 ;
        RECT  21.462 66.624 21.546 66.648 ;
    END
  END q[479]
  PIN q[47]
    DIRECTION OUTPUT ;
    USE SIGNAL ;
    PORT
      LAYER M4 ;
        RECT  21.462 11.376 21.546 11.4 ;
    END
  END q[47]
  PIN q[480]
    DIRECTION OUTPUT ;
    USE SIGNAL ;
    PORT
      LAYER M4 ;
        RECT  21.462 66.72 21.546 66.744 ;
    END
  END q[480]
  PIN q[481]
    DIRECTION OUTPUT ;
    USE SIGNAL ;
    PORT
      LAYER M4 ;
        RECT  21.462 66.864 21.546 66.888 ;
    END
  END q[481]
  PIN q[482]
    DIRECTION OUTPUT ;
    USE SIGNAL ;
    PORT
      LAYER M4 ;
        RECT  21.462 67.008 21.546 67.032 ;
    END
  END q[482]
  PIN q[483]
    DIRECTION OUTPUT ;
    USE SIGNAL ;
    PORT
      LAYER M4 ;
        RECT  21.462 67.104 21.546 67.128 ;
    END
  END q[483]
  PIN q[484]
    DIRECTION OUTPUT ;
    USE SIGNAL ;
    PORT
      LAYER M4 ;
        RECT  21.462 67.248 21.546 67.272 ;
    END
  END q[484]
  PIN q[485]
    DIRECTION OUTPUT ;
    USE SIGNAL ;
    PORT
      LAYER M4 ;
        RECT  21.462 67.392 21.546 67.416 ;
    END
  END q[485]
  PIN q[486]
    DIRECTION OUTPUT ;
    USE SIGNAL ;
    PORT
      LAYER M4 ;
        RECT  21.462 67.488 21.546 67.512 ;
    END
  END q[486]
  PIN q[487]
    DIRECTION OUTPUT ;
    USE SIGNAL ;
    PORT
      LAYER M4 ;
        RECT  21.462 67.632 21.546 67.656 ;
    END
  END q[487]
  PIN q[488]
    DIRECTION OUTPUT ;
    USE SIGNAL ;
    PORT
      LAYER M4 ;
        RECT  21.462 67.776 21.546 67.8 ;
    END
  END q[488]
  PIN q[489]
    DIRECTION OUTPUT ;
    USE SIGNAL ;
    PORT
      LAYER M4 ;
        RECT  21.462 67.872 21.546 67.896 ;
    END
  END q[489]
  PIN q[48]
    DIRECTION OUTPUT ;
    USE SIGNAL ;
    PORT
      LAYER M4 ;
        RECT  21.462 11.52 21.546 11.544 ;
    END
  END q[48]
  PIN q[490]
    DIRECTION OUTPUT ;
    USE SIGNAL ;
    PORT
      LAYER M4 ;
        RECT  21.462 68.016 21.546 68.04 ;
    END
  END q[490]
  PIN q[491]
    DIRECTION OUTPUT ;
    USE SIGNAL ;
    PORT
      LAYER M4 ;
        RECT  21.462 68.16 21.546 68.184 ;
    END
  END q[491]
  PIN q[492]
    DIRECTION OUTPUT ;
    USE SIGNAL ;
    PORT
      LAYER M4 ;
        RECT  21.462 68.256 21.546 68.28 ;
    END
  END q[492]
  PIN q[493]
    DIRECTION OUTPUT ;
    USE SIGNAL ;
    PORT
      LAYER M4 ;
        RECT  21.462 68.4 21.546 68.424 ;
    END
  END q[493]
  PIN q[494]
    DIRECTION OUTPUT ;
    USE SIGNAL ;
    PORT
      LAYER M4 ;
        RECT  21.462 68.544 21.546 68.568 ;
    END
  END q[494]
  PIN q[495]
    DIRECTION OUTPUT ;
    USE SIGNAL ;
    PORT
      LAYER M4 ;
        RECT  21.462 68.64 21.546 68.664 ;
    END
  END q[495]
  PIN q[496]
    DIRECTION OUTPUT ;
    USE SIGNAL ;
    PORT
      LAYER M4 ;
        RECT  21.462 68.784 21.546 68.808 ;
    END
  END q[496]
  PIN q[497]
    DIRECTION OUTPUT ;
    USE SIGNAL ;
    PORT
      LAYER M4 ;
        RECT  21.462 68.928 21.546 68.952 ;
    END
  END q[497]
  PIN q[498]
    DIRECTION OUTPUT ;
    USE SIGNAL ;
    PORT
      LAYER M4 ;
        RECT  21.462 69.024 21.546 69.048 ;
    END
  END q[498]
  PIN q[499]
    DIRECTION OUTPUT ;
    USE SIGNAL ;
    PORT
      LAYER M4 ;
        RECT  21.462 69.168 21.546 69.192 ;
    END
  END q[499]
  PIN q[49]
    DIRECTION OUTPUT ;
    USE SIGNAL ;
    PORT
      LAYER M4 ;
        RECT  21.462 11.664 21.546 11.688 ;
    END
  END q[49]
  PIN q[4]
    DIRECTION OUTPUT ;
    USE SIGNAL ;
    PORT
      LAYER M4 ;
        RECT  21.462 5.904 21.546 5.928 ;
    END
  END q[4]
  PIN q[500]
    DIRECTION OUTPUT ;
    USE SIGNAL ;
    PORT
      LAYER M4 ;
        RECT  21.462 69.312 21.546 69.336 ;
    END
  END q[500]
  PIN q[501]
    DIRECTION OUTPUT ;
    USE SIGNAL ;
    PORT
      LAYER M4 ;
        RECT  21.462 69.408 21.546 69.432 ;
    END
  END q[501]
  PIN q[502]
    DIRECTION OUTPUT ;
    USE SIGNAL ;
    PORT
      LAYER M4 ;
        RECT  21.462 69.552 21.546 69.576 ;
    END
  END q[502]
  PIN q[503]
    DIRECTION OUTPUT ;
    USE SIGNAL ;
    PORT
      LAYER M4 ;
        RECT  21.462 69.696 21.546 69.72 ;
    END
  END q[503]
  PIN q[504]
    DIRECTION OUTPUT ;
    USE SIGNAL ;
    PORT
      LAYER M4 ;
        RECT  21.462 69.792 21.546 69.816 ;
    END
  END q[504]
  PIN q[505]
    DIRECTION OUTPUT ;
    USE SIGNAL ;
    PORT
      LAYER M4 ;
        RECT  21.462 69.936 21.546 69.96 ;
    END
  END q[505]
  PIN q[506]
    DIRECTION OUTPUT ;
    USE SIGNAL ;
    PORT
      LAYER M4 ;
        RECT  21.462 70.08 21.546 70.104 ;
    END
  END q[506]
  PIN q[507]
    DIRECTION OUTPUT ;
    USE SIGNAL ;
    PORT
      LAYER M4 ;
        RECT  21.462 70.176 21.546 70.2 ;
    END
  END q[507]
  PIN q[50]
    DIRECTION OUTPUT ;
    USE SIGNAL ;
    PORT
      LAYER M4 ;
        RECT  21.462 11.76 21.546 11.784 ;
    END
  END q[50]
  PIN q[51]
    DIRECTION OUTPUT ;
    USE SIGNAL ;
    PORT
      LAYER M4 ;
        RECT  21.462 11.904 21.546 11.928 ;
    END
  END q[51]
  PIN q[52]
    DIRECTION OUTPUT ;
    USE SIGNAL ;
    PORT
      LAYER M4 ;
        RECT  21.462 12.048 21.546 12.072 ;
    END
  END q[52]
  PIN q[53]
    DIRECTION OUTPUT ;
    USE SIGNAL ;
    PORT
      LAYER M4 ;
        RECT  21.462 12.144 21.546 12.168 ;
    END
  END q[53]
  PIN q[54]
    DIRECTION OUTPUT ;
    USE SIGNAL ;
    PORT
      LAYER M4 ;
        RECT  21.462 12.288 21.546 12.312 ;
    END
  END q[54]
  PIN q[55]
    DIRECTION OUTPUT ;
    USE SIGNAL ;
    PORT
      LAYER M4 ;
        RECT  21.462 12.432 21.546 12.456 ;
    END
  END q[55]
  PIN q[56]
    DIRECTION OUTPUT ;
    USE SIGNAL ;
    PORT
      LAYER M4 ;
        RECT  21.462 12.528 21.546 12.552 ;
    END
  END q[56]
  PIN q[57]
    DIRECTION OUTPUT ;
    USE SIGNAL ;
    PORT
      LAYER M4 ;
        RECT  21.462 12.672 21.546 12.696 ;
    END
  END q[57]
  PIN q[58]
    DIRECTION OUTPUT ;
    USE SIGNAL ;
    PORT
      LAYER M4 ;
        RECT  21.462 12.816 21.546 12.84 ;
    END
  END q[58]
  PIN q[59]
    DIRECTION OUTPUT ;
    USE SIGNAL ;
    PORT
      LAYER M4 ;
        RECT  21.462 12.912 21.546 12.936 ;
    END
  END q[59]
  PIN q[5]
    DIRECTION OUTPUT ;
    USE SIGNAL ;
    PORT
      LAYER M4 ;
        RECT  21.462 6.048 21.546 6.072 ;
    END
  END q[5]
  PIN q[60]
    DIRECTION OUTPUT ;
    USE SIGNAL ;
    PORT
      LAYER M4 ;
        RECT  21.462 13.056 21.546 13.08 ;
    END
  END q[60]
  PIN q[61]
    DIRECTION OUTPUT ;
    USE SIGNAL ;
    PORT
      LAYER M4 ;
        RECT  21.462 13.2 21.546 13.224 ;
    END
  END q[61]
  PIN q[62]
    DIRECTION OUTPUT ;
    USE SIGNAL ;
    PORT
      LAYER M4 ;
        RECT  21.462 13.296 21.546 13.32 ;
    END
  END q[62]
  PIN q[63]
    DIRECTION OUTPUT ;
    USE SIGNAL ;
    PORT
      LAYER M4 ;
        RECT  21.462 13.44 21.546 13.464 ;
    END
  END q[63]
  PIN q[64]
    DIRECTION OUTPUT ;
    USE SIGNAL ;
    PORT
      LAYER M4 ;
        RECT  21.462 13.584 21.546 13.608 ;
    END
  END q[64]
  PIN q[65]
    DIRECTION OUTPUT ;
    USE SIGNAL ;
    PORT
      LAYER M4 ;
        RECT  21.462 13.68 21.546 13.704 ;
    END
  END q[65]
  PIN q[66]
    DIRECTION OUTPUT ;
    USE SIGNAL ;
    PORT
      LAYER M4 ;
        RECT  21.462 13.824 21.546 13.848 ;
    END
  END q[66]
  PIN q[67]
    DIRECTION OUTPUT ;
    USE SIGNAL ;
    PORT
      LAYER M4 ;
        RECT  21.462 13.968 21.546 13.992 ;
    END
  END q[67]
  PIN q[68]
    DIRECTION OUTPUT ;
    USE SIGNAL ;
    PORT
      LAYER M4 ;
        RECT  21.462 14.064 21.546 14.088 ;
    END
  END q[68]
  PIN q[69]
    DIRECTION OUTPUT ;
    USE SIGNAL ;
    PORT
      LAYER M4 ;
        RECT  21.462 14.208 21.546 14.232 ;
    END
  END q[69]
  PIN q[6]
    DIRECTION OUTPUT ;
    USE SIGNAL ;
    PORT
      LAYER M4 ;
        RECT  21.462 6.144 21.546 6.168 ;
    END
  END q[6]
  PIN q[70]
    DIRECTION OUTPUT ;
    USE SIGNAL ;
    PORT
      LAYER M4 ;
        RECT  21.462 14.352 21.546 14.376 ;
    END
  END q[70]
  PIN q[71]
    DIRECTION OUTPUT ;
    USE SIGNAL ;
    PORT
      LAYER M4 ;
        RECT  21.462 14.448 21.546 14.472 ;
    END
  END q[71]
  PIN q[72]
    DIRECTION OUTPUT ;
    USE SIGNAL ;
    PORT
      LAYER M4 ;
        RECT  21.462 14.592 21.546 14.616 ;
    END
  END q[72]
  PIN q[73]
    DIRECTION OUTPUT ;
    USE SIGNAL ;
    PORT
      LAYER M4 ;
        RECT  21.462 14.736 21.546 14.76 ;
    END
  END q[73]
  PIN q[74]
    DIRECTION OUTPUT ;
    USE SIGNAL ;
    PORT
      LAYER M4 ;
        RECT  21.462 14.832 21.546 14.856 ;
    END
  END q[74]
  PIN q[75]
    DIRECTION OUTPUT ;
    USE SIGNAL ;
    PORT
      LAYER M4 ;
        RECT  21.462 14.976 21.546 15 ;
    END
  END q[75]
  PIN q[76]
    DIRECTION OUTPUT ;
    USE SIGNAL ;
    PORT
      LAYER M4 ;
        RECT  21.462 15.12 21.546 15.144 ;
    END
  END q[76]
  PIN q[77]
    DIRECTION OUTPUT ;
    USE SIGNAL ;
    PORT
      LAYER M4 ;
        RECT  21.462 15.216 21.546 15.24 ;
    END
  END q[77]
  PIN q[78]
    DIRECTION OUTPUT ;
    USE SIGNAL ;
    PORT
      LAYER M4 ;
        RECT  21.462 15.36 21.546 15.384 ;
    END
  END q[78]
  PIN q[79]
    DIRECTION OUTPUT ;
    USE SIGNAL ;
    PORT
      LAYER M4 ;
        RECT  21.462 15.504 21.546 15.528 ;
    END
  END q[79]
  PIN q[7]
    DIRECTION OUTPUT ;
    USE SIGNAL ;
    PORT
      LAYER M4 ;
        RECT  21.462 6.288 21.546 6.312 ;
    END
  END q[7]
  PIN q[80]
    DIRECTION OUTPUT ;
    USE SIGNAL ;
    PORT
      LAYER M4 ;
        RECT  21.462 15.6 21.546 15.624 ;
    END
  END q[80]
  PIN q[81]
    DIRECTION OUTPUT ;
    USE SIGNAL ;
    PORT
      LAYER M4 ;
        RECT  21.462 15.744 21.546 15.768 ;
    END
  END q[81]
  PIN q[82]
    DIRECTION OUTPUT ;
    USE SIGNAL ;
    PORT
      LAYER M4 ;
        RECT  21.462 15.888 21.546 15.912 ;
    END
  END q[82]
  PIN q[83]
    DIRECTION OUTPUT ;
    USE SIGNAL ;
    PORT
      LAYER M4 ;
        RECT  21.462 15.984 21.546 16.008 ;
    END
  END q[83]
  PIN q[84]
    DIRECTION OUTPUT ;
    USE SIGNAL ;
    PORT
      LAYER M4 ;
        RECT  21.462 16.128 21.546 16.152 ;
    END
  END q[84]
  PIN q[85]
    DIRECTION OUTPUT ;
    USE SIGNAL ;
    PORT
      LAYER M4 ;
        RECT  21.462 16.272 21.546 16.296 ;
    END
  END q[85]
  PIN q[86]
    DIRECTION OUTPUT ;
    USE SIGNAL ;
    PORT
      LAYER M4 ;
        RECT  21.462 16.368 21.546 16.392 ;
    END
  END q[86]
  PIN q[87]
    DIRECTION OUTPUT ;
    USE SIGNAL ;
    PORT
      LAYER M4 ;
        RECT  21.462 16.512 21.546 16.536 ;
    END
  END q[87]
  PIN q[88]
    DIRECTION OUTPUT ;
    USE SIGNAL ;
    PORT
      LAYER M4 ;
        RECT  21.462 16.656 21.546 16.68 ;
    END
  END q[88]
  PIN q[89]
    DIRECTION OUTPUT ;
    USE SIGNAL ;
    PORT
      LAYER M4 ;
        RECT  21.462 16.752 21.546 16.776 ;
    END
  END q[89]
  PIN q[8]
    DIRECTION OUTPUT ;
    USE SIGNAL ;
    PORT
      LAYER M4 ;
        RECT  21.462 6.432 21.546 6.456 ;
    END
  END q[8]
  PIN q[90]
    DIRECTION OUTPUT ;
    USE SIGNAL ;
    PORT
      LAYER M4 ;
        RECT  21.462 16.896 21.546 16.92 ;
    END
  END q[90]
  PIN q[91]
    DIRECTION OUTPUT ;
    USE SIGNAL ;
    PORT
      LAYER M4 ;
        RECT  21.462 17.04 21.546 17.064 ;
    END
  END q[91]
  PIN q[92]
    DIRECTION OUTPUT ;
    USE SIGNAL ;
    PORT
      LAYER M4 ;
        RECT  21.462 17.136 21.546 17.16 ;
    END
  END q[92]
  PIN q[93]
    DIRECTION OUTPUT ;
    USE SIGNAL ;
    PORT
      LAYER M4 ;
        RECT  21.462 17.28 21.546 17.304 ;
    END
  END q[93]
  PIN q[94]
    DIRECTION OUTPUT ;
    USE SIGNAL ;
    PORT
      LAYER M4 ;
        RECT  21.462 17.424 21.546 17.448 ;
    END
  END q[94]
  PIN q[95]
    DIRECTION OUTPUT ;
    USE SIGNAL ;
    PORT
      LAYER M4 ;
        RECT  21.462 17.52 21.546 17.544 ;
    END
  END q[95]
  PIN q[96]
    DIRECTION OUTPUT ;
    USE SIGNAL ;
    PORT
      LAYER M4 ;
        RECT  21.462 17.664 21.546 17.688 ;
    END
  END q[96]
  PIN q[97]
    DIRECTION OUTPUT ;
    USE SIGNAL ;
    PORT
      LAYER M4 ;
        RECT  21.462 17.808 21.546 17.832 ;
    END
  END q[97]
  PIN q[98]
    DIRECTION OUTPUT ;
    USE SIGNAL ;
    PORT
      LAYER M4 ;
        RECT  21.462 17.904 21.546 17.928 ;
    END
  END q[98]
  PIN q[99]
    DIRECTION OUTPUT ;
    USE SIGNAL ;
    PORT
      LAYER M4 ;
        RECT  21.462 18.048 21.546 18.072 ;
    END
  END q[99]
  PIN q[9]
    DIRECTION OUTPUT ;
    USE SIGNAL ;
    PORT
      LAYER M4 ;
        RECT  21.462 6.528 21.546 6.552 ;
    END
  END q[9]
  PIN rst_n
    DIRECTION INPUT ;
    USE SIGNAL ;
    PORT
      LAYER M5 ;
        RECT  9.696 0.054 9.72 0.138 ;
    END
    PORT
      LAYER M5 ;
        RECT  9.696 0.08 9.72 2.137 ;
    END
  END rst_n
  PIN VDD
    DIRECTION INOUT ;
    USE POWER ;
    PORT
      LAYER M5 ;
        RECT  18.792 2.151 18.912 73.449 ;
        RECT  16.092 2.151 16.212 73.449 ;
        RECT  13.392 2.151 13.512 73.449 ;
        RECT  10.692 2.151 10.812 73.449 ;
        RECT  7.992 2.151 8.112 73.449 ;
        RECT  5.292 2.151 5.412 73.449 ;
        RECT  2.592 2.151 2.712 73.449 ;
    END
  END VDD
  PIN VSS
    DIRECTION INOUT ;
    USE GROUND ;
    PORT
      LAYER M5 ;
        RECT  18.6 2.137 18.72 73.463 ;
        RECT  15.9 2.137 16.02 73.463 ;
        RECT  13.2 2.137 13.32 73.463 ;
        RECT  10.5 2.137 10.62 73.463 ;
        RECT  7.8 2.137 7.92 73.463 ;
        RECT  5.1 2.137 5.22 73.463 ;
        RECT  2.4 2.137 2.52 73.463 ;
    END
  END VSS
  # OT_OBS_CLOSED layer=M5 d_um=1.536 added=68
  OBS
    LAYER RVTN ;
     RECT  2.16 2.16 19.44 2.295 ;
     RECT  2.16 2.565 19.44 2.835 ;
     RECT  2.16 3.105 19.44 3.375 ;
     RECT  2.16 3.645 19.44 3.915 ;
     RECT  2.16 4.185 19.44 4.455 ;
     RECT  2.16 4.725 19.44 4.995 ;
     RECT  2.16 5.265 19.44 5.535 ;
     RECT  2.16 5.805 19.44 6.075 ;
     RECT  2.16 6.345 19.44 6.615 ;
     RECT  2.16 6.885 19.44 7.155 ;
     RECT  2.16 7.425 19.44 7.695 ;
     RECT  2.16 7.965 19.44 8.235 ;
     RECT  2.16 8.505 19.44 8.775 ;
     RECT  2.16 9.045 19.44 9.315 ;
     RECT  2.16 9.585 19.44 9.855 ;
     RECT  2.16 10.125 19.44 10.395 ;
     RECT  2.16 10.665 19.44 10.935 ;
     RECT  2.16 11.205 19.44 11.475 ;
     RECT  2.16 11.745 19.44 12.015 ;
     RECT  2.16 12.285 19.44 12.555 ;
     RECT  2.16 12.825 19.44 13.095 ;
     RECT  2.16 13.365 19.44 13.635 ;
     RECT  2.16 13.905 19.44 14.175 ;
     RECT  2.16 14.445 19.44 14.715 ;
     RECT  2.16 14.985 19.44 15.255 ;
     RECT  2.16 15.525 19.44 15.795 ;
     RECT  2.16 16.065 19.44 16.335 ;
     RECT  2.16 16.605 19.44 16.875 ;
     RECT  2.16 17.145 19.44 17.415 ;
     RECT  2.16 17.685 19.44 17.955 ;
     RECT  2.16 18.225 19.44 18.495 ;
     RECT  2.16 18.765 19.44 19.035 ;
     RECT  2.16 19.305 19.44 19.575 ;
     RECT  2.16 19.845 19.44 20.115 ;
     RECT  2.16 20.385 19.44 20.655 ;
     RECT  2.16 20.925 19.44 21.195 ;
     RECT  2.16 21.465 19.44 21.735 ;
     RECT  2.16 22.005 19.44 22.275 ;
     RECT  2.16 22.545 19.44 22.815 ;
     RECT  2.16 23.085 19.44 23.355 ;
     RECT  2.16 23.625 19.44 23.895 ;
     RECT  2.16 24.165 19.44 24.435 ;
     RECT  2.16 24.705 19.44 24.975 ;
     RECT  2.16 25.245 19.44 25.515 ;
     RECT  2.16 25.785 19.44 26.055 ;
     RECT  2.16 26.325 19.44 26.595 ;
     RECT  2.16 26.865 19.44 27.135 ;
     RECT  2.16 27.405 19.44 27.675 ;
     RECT  2.16 27.945 19.44 28.215 ;
     RECT  2.16 28.485 19.44 28.755 ;
     RECT  2.16 29.025 19.44 29.295 ;
     RECT  2.16 29.565 19.44 29.835 ;
     RECT  2.16 30.105 19.44 30.375 ;
     RECT  2.16 30.645 19.44 30.915 ;
     RECT  2.16 31.185 19.44 31.455 ;
     RECT  2.16 31.725 19.44 31.995 ;
     RECT  2.16 32.265 19.44 32.535 ;
     RECT  2.16 32.805 19.44 33.075 ;
     RECT  2.16 33.345 19.44 33.615 ;
     RECT  2.16 33.885 19.44 34.155 ;
     RECT  2.16 34.425 19.44 34.695 ;
     RECT  2.16 34.965 19.44 35.235 ;
     RECT  2.16 35.505 19.44 35.775 ;
     RECT  2.16 36.045 19.44 36.315 ;
     RECT  2.16 36.585 19.44 36.855 ;
     RECT  2.16 37.125 19.44 37.395 ;
     RECT  2.16 37.665 19.44 37.935 ;
     RECT  2.16 38.205 19.44 38.475 ;
     RECT  2.16 38.745 19.44 39.015 ;
     RECT  2.16 39.285 19.44 39.555 ;
     RECT  2.16 39.825 19.44 40.095 ;
     RECT  2.16 40.365 19.44 40.635 ;
     RECT  2.16 40.905 19.44 41.175 ;
     RECT  2.16 41.445 19.44 41.715 ;
     RECT  2.16 41.985 19.44 42.255 ;
     RECT  2.16 42.525 19.44 42.795 ;
     RECT  2.16 43.065 19.44 43.335 ;
     RECT  2.16 43.605 19.44 43.875 ;
     RECT  2.16 44.145 19.44 44.415 ;
     RECT  2.16 44.685 19.44 44.955 ;
     RECT  2.16 45.225 19.44 45.495 ;
     RECT  2.16 45.765 19.44 46.035 ;
     RECT  2.16 46.305 19.44 46.575 ;
     RECT  2.16 46.845 19.44 47.115 ;
     RECT  2.16 47.385 19.44 47.655 ;
     RECT  2.16 47.925 19.44 48.195 ;
     RECT  2.16 48.465 19.44 48.735 ;
     RECT  2.16 49.005 19.44 49.275 ;
     RECT  2.16 49.545 19.44 49.815 ;
     RECT  2.16 50.085 19.44 50.355 ;
     RECT  2.16 50.625 19.44 50.895 ;
     RECT  2.16 51.165 19.44 51.435 ;
     RECT  2.16 51.705 19.44 51.975 ;
     RECT  2.16 52.245 19.44 52.515 ;
     RECT  2.16 52.785 19.44 53.055 ;
     RECT  2.16 53.325 19.44 53.595 ;
     RECT  2.16 53.865 19.44 54.135 ;
     RECT  2.16 54.405 19.44 54.675 ;
     RECT  2.16 54.945 19.44 55.215 ;
     RECT  2.16 55.485 19.44 55.755 ;
     RECT  2.16 56.025 19.44 56.295 ;
     RECT  2.16 56.565 19.44 56.835 ;
     RECT  2.16 57.105 19.44 57.375 ;
     RECT  2.16 57.645 19.44 57.915 ;
     RECT  2.16 58.185 19.44 58.455 ;
     RECT  2.16 58.725 19.44 58.995 ;
     RECT  2.16 59.265 19.44 59.535 ;
     RECT  2.16 59.805 19.44 60.075 ;
     RECT  2.16 60.345 19.44 60.615 ;
     RECT  2.16 60.885 19.44 61.155 ;
     RECT  2.16 61.425 19.44 61.695 ;
     RECT  2.16 61.965 19.44 62.235 ;
     RECT  2.16 62.505 19.44 62.775 ;
     RECT  2.16 63.045 19.44 63.315 ;
     RECT  2.16 63.585 19.44 63.855 ;
     RECT  2.16 64.125 19.44 64.395 ;
     RECT  2.16 64.665 19.44 64.935 ;
     RECT  2.16 65.205 19.44 65.475 ;
     RECT  2.16 65.745 19.44 66.015 ;
     RECT  2.16 66.285 19.44 66.555 ;
     RECT  2.16 66.825 19.44 67.095 ;
     RECT  2.16 67.365 19.44 67.635 ;
     RECT  2.16 67.905 19.44 68.175 ;
     RECT  2.16 68.445 19.44 68.715 ;
     RECT  2.16 68.985 19.44 69.255 ;
     RECT  2.16 69.525 19.44 69.795 ;
     RECT  2.16 70.065 19.44 70.335 ;
     RECT  2.16 70.605 19.44 70.875 ;
     RECT  2.16 71.145 19.44 71.415 ;
     RECT  2.16 71.685 19.44 71.955 ;
     RECT  2.16 72.225 19.44 72.495 ;
     RECT  2.16 72.765 19.44 73.035 ;
     RECT  2.16 73.305 19.44 73.44 ;
    LAYER RVTP ;
     RECT  2.16 2.295 19.44 2.565 ;
     RECT  2.16 2.835 19.44 3.105 ;
     RECT  2.16 3.375 19.44 3.645 ;
     RECT  2.16 3.915 19.44 4.185 ;
     RECT  2.16 4.455 19.44 4.725 ;
     RECT  2.16 4.995 19.44 5.265 ;
     RECT  2.16 5.535 19.44 5.805 ;
     RECT  2.16 6.075 19.44 6.345 ;
     RECT  2.16 6.615 19.44 6.885 ;
     RECT  2.16 7.155 19.44 7.425 ;
     RECT  2.16 7.695 19.44 7.965 ;
     RECT  2.16 8.235 19.44 8.505 ;
     RECT  2.16 8.775 19.44 9.045 ;
     RECT  2.16 9.315 19.44 9.585 ;
     RECT  2.16 9.855 19.44 10.125 ;
     RECT  2.16 10.395 19.44 10.665 ;
     RECT  2.16 10.935 19.44 11.205 ;
     RECT  2.16 11.475 19.44 11.745 ;
     RECT  2.16 12.015 19.44 12.285 ;
     RECT  2.16 12.555 19.44 12.825 ;
     RECT  2.16 13.095 19.44 13.365 ;
     RECT  2.16 13.635 19.44 13.905 ;
     RECT  2.16 14.175 19.44 14.445 ;
     RECT  2.16 14.715 19.44 14.985 ;
     RECT  2.16 15.255 19.44 15.525 ;
     RECT  2.16 15.795 19.44 16.065 ;
     RECT  2.16 16.335 19.44 16.605 ;
     RECT  2.16 16.875 19.44 17.145 ;
     RECT  2.16 17.415 19.44 17.685 ;
     RECT  2.16 17.955 19.44 18.225 ;
     RECT  2.16 18.495 19.44 18.765 ;
     RECT  2.16 19.035 19.44 19.305 ;
     RECT  2.16 19.575 19.44 19.845 ;
     RECT  2.16 20.115 19.44 20.385 ;
     RECT  2.16 20.655 19.44 20.925 ;
     RECT  2.16 21.195 19.44 21.465 ;
     RECT  2.16 21.735 19.44 22.005 ;
     RECT  2.16 22.275 19.44 22.545 ;
     RECT  2.16 22.815 19.44 23.085 ;
     RECT  2.16 23.355 19.44 23.625 ;
     RECT  2.16 23.895 19.44 24.165 ;
     RECT  2.16 24.435 19.44 24.705 ;
     RECT  2.16 24.975 19.44 25.245 ;
     RECT  2.16 25.515 19.44 25.785 ;
     RECT  2.16 26.055 19.44 26.325 ;
     RECT  2.16 26.595 19.44 26.865 ;
     RECT  2.16 27.135 19.44 27.405 ;
     RECT  2.16 27.675 19.44 27.945 ;
     RECT  2.16 28.215 19.44 28.485 ;
     RECT  2.16 28.755 19.44 29.025 ;
     RECT  2.16 29.295 19.44 29.565 ;
     RECT  2.16 29.835 19.44 30.105 ;
     RECT  2.16 30.375 19.44 30.645 ;
     RECT  2.16 30.915 19.44 31.185 ;
     RECT  2.16 31.455 19.44 31.725 ;
     RECT  2.16 31.995 19.44 32.265 ;
     RECT  2.16 32.535 19.44 32.805 ;
     RECT  2.16 33.075 19.44 33.345 ;
     RECT  2.16 33.615 19.44 33.885 ;
     RECT  2.16 34.155 19.44 34.425 ;
     RECT  2.16 34.695 19.44 34.965 ;
     RECT  2.16 35.235 19.44 35.505 ;
     RECT  2.16 35.775 19.44 36.045 ;
     RECT  2.16 36.315 19.44 36.585 ;
     RECT  2.16 36.855 19.44 37.125 ;
     RECT  2.16 37.395 19.44 37.665 ;
     RECT  2.16 37.935 19.44 38.205 ;
     RECT  2.16 38.475 19.44 38.745 ;
     RECT  2.16 39.015 19.44 39.285 ;
     RECT  2.16 39.555 19.44 39.825 ;
     RECT  2.16 40.095 19.44 40.365 ;
     RECT  2.16 40.635 19.44 40.905 ;
     RECT  2.16 41.175 19.44 41.445 ;
     RECT  2.16 41.715 19.44 41.985 ;
     RECT  2.16 42.255 19.44 42.525 ;
     RECT  2.16 42.795 19.44 43.065 ;
     RECT  2.16 43.335 19.44 43.605 ;
     RECT  2.16 43.875 19.44 44.145 ;
     RECT  2.16 44.415 19.44 44.685 ;
     RECT  2.16 44.955 19.44 45.225 ;
     RECT  2.16 45.495 19.44 45.765 ;
     RECT  2.16 46.035 19.44 46.305 ;
     RECT  2.16 46.575 19.44 46.845 ;
     RECT  2.16 47.115 19.44 47.385 ;
     RECT  2.16 47.655 19.44 47.925 ;
     RECT  2.16 48.195 19.44 48.465 ;
     RECT  2.16 48.735 19.44 49.005 ;
     RECT  2.16 49.275 19.44 49.545 ;
     RECT  2.16 49.815 19.44 50.085 ;
     RECT  2.16 50.355 19.44 50.625 ;
     RECT  2.16 50.895 19.44 51.165 ;
     RECT  2.16 51.435 19.44 51.705 ;
     RECT  2.16 51.975 19.44 52.245 ;
     RECT  2.16 52.515 19.44 52.785 ;
     RECT  2.16 53.055 19.44 53.325 ;
     RECT  2.16 53.595 19.44 53.865 ;
     RECT  2.16 54.135 19.44 54.405 ;
     RECT  2.16 54.675 19.44 54.945 ;
     RECT  2.16 55.215 19.44 55.485 ;
     RECT  2.16 55.755 19.44 56.025 ;
     RECT  2.16 56.295 19.44 56.565 ;
     RECT  2.16 56.835 19.44 57.105 ;
     RECT  2.16 57.375 19.44 57.645 ;
     RECT  2.16 57.915 19.44 58.185 ;
     RECT  2.16 58.455 19.44 58.725 ;
     RECT  2.16 58.995 19.44 59.265 ;
     RECT  2.16 59.535 19.44 59.805 ;
     RECT  2.16 60.075 19.44 60.345 ;
     RECT  2.16 60.615 19.44 60.885 ;
     RECT  2.16 61.155 19.44 61.425 ;
     RECT  2.16 61.695 19.44 61.965 ;
     RECT  2.16 62.235 19.44 62.505 ;
     RECT  2.16 62.775 19.44 63.045 ;
     RECT  2.16 63.315 19.44 63.585 ;
     RECT  2.16 63.855 19.44 64.125 ;
     RECT  2.16 64.395 19.44 64.665 ;
     RECT  2.16 64.935 19.44 65.205 ;
     RECT  2.16 65.475 19.44 65.745 ;
     RECT  2.16 66.015 19.44 66.285 ;
     RECT  2.16 66.555 19.44 66.825 ;
     RECT  2.16 67.095 19.44 67.365 ;
     RECT  2.16 67.635 19.44 67.905 ;
     RECT  2.16 68.175 19.44 68.445 ;
     RECT  2.16 68.715 19.44 68.985 ;
     RECT  2.16 69.255 19.44 69.525 ;
     RECT  2.16 69.795 19.44 70.065 ;
     RECT  2.16 70.335 19.44 70.605 ;
     RECT  2.16 70.875 19.44 71.145 ;
     RECT  2.16 71.415 19.44 71.685 ;
     RECT  2.16 71.955 19.44 72.225 ;
     RECT  2.16 72.495 19.44 72.765 ;
     RECT  2.16 73.035 19.44 73.305 ;
    LAYER M1 ;
     RECT  2.16 2.151 19.44 73.449 ;
    LAYER M2 ;
     RECT  0.031 13.032 0.139 13.392 ;
     RECT  0.031 26.676 0.139 26.694 ;
     RECT  0.031 68.724 0.139 68.742 ;
     RECT  0.139 4.77 0.175 4.788 ;
     RECT  0.139 5.742 0.175 5.76 ;
     RECT  0.139 6.822 0.175 7.956 ;
     RECT  0.139 31.23 0.175 31.248 ;
     RECT  0.139 64.908 0.175 64.926 ;
     RECT  0.175 4.5 0.211 4.788 ;
     RECT  0.175 5.742 0.211 7.956 ;
     RECT  0.139 12.492 0.239 13.392 ;
     RECT  0.139 26.676 0.239 27.09 ;
     RECT  0.031 33.516 0.239 33.534 ;
     RECT  0.139 35.586 0.239 35.604 ;
     RECT  0.139 36.828 0.239 36.846 ;
     RECT  0.139 68.724 0.239 68.94 ;
     RECT  0.031 69.876 0.239 69.894 ;
     RECT  0.239 12.492 0.311 13.05 ;
     RECT  0.031 63.792 0.311 63.81 ;
     RECT  0.139 28.962 0.535 28.98 ;
     RECT  0.139 44.352 0.535 44.37 ;
     RECT  0.139 48.402 0.535 48.42 ;
     RECT  0.139 53.568 0.535 53.586 ;
     RECT  0.139 58.122 0.535 58.68 ;
     RECT  1.399 71.892 1.723 71.91 ;
     RECT  0.211 4.5 2.16 7.956 ;
     RECT  0.139 9.522 2.16 9.54 ;
     RECT  0.311 12.492 2.16 12.546 ;
     RECT  0.139 17.46 2.16 17.478 ;
     RECT  0.535 19.926 2.16 19.944 ;
     RECT  0.139 22.212 2.16 22.77 ;
     RECT  0.535 25.02 2.16 25.038 ;
     RECT  0.239 27.072 2.16 27.09 ;
     RECT  0.139 27.882 2.16 27.9 ;
     RECT  0.535 28.962 2.16 29.052 ;
     RECT  0.139 30.15 2.16 30.168 ;
     RECT  0.175 31.122 2.16 31.248 ;
     RECT  0.535 33.39 2.16 33.408 ;
     RECT  1.327 34.974 2.16 34.992 ;
     RECT  0.535 39.87 2.16 39.888 ;
     RECT  0.139 42.732 2.16 43.326 ;
     RECT  0.535 44.352 2.16 44.442 ;
     RECT  0.535 47.664 2.16 48.42 ;
     RECT  0.139 50.598 2.16 50.616 ;
     RECT  0.535 52.866 2.16 53.586 ;
     RECT  0.535 57.996 2.16 58.68 ;
     RECT  0.175 64.872 2.16 64.926 ;
     RECT  0.239 68.922 2.16 68.94 ;
     RECT  1.723 71.352 2.16 71.91 ;
     RECT  2.16 2.151 19.44 73.449 ;
     RECT  19.44 71.046 19.931 71.604 ;
     RECT  19.44 6.624 19.967 70.254 ;
     RECT  19.967 6.624 20.219 14.814 ;
     RECT  20.219 7.596 20.255 14.814 ;
     RECT  19.931 71.046 20.363 71.064 ;
     RECT  19.967 15.57 20.435 70.254 ;
     RECT  20.435 15.57 20.471 68.94 ;
     RECT  20.435 69.768 20.471 70.254 ;
     RECT  20.255 7.596 20.507 14.634 ;
     RECT  20.471 15.57 20.507 53.514 ;
     RECT  20.471 54.306 20.507 68.4 ;
     RECT  20.471 69.768 20.507 69.894 ;
     RECT  20.219 6.624 20.543 6.84 ;
     RECT  20.507 9.828 20.543 14.364 ;
     RECT  20.507 18.27 20.543 20.916 ;
     RECT  20.507 21.744 20.543 25.434 ;
     RECT  20.507 33.426 20.543 36.306 ;
     RECT  20.507 37.17 20.543 39.384 ;
     RECT  20.507 40.446 20.543 44.514 ;
     RECT  20.507 45.576 20.543 47.376 ;
     RECT  20.507 48.402 20.543 49.914 ;
     RECT  20.507 50.94 20.543 53.316 ;
     RECT  20.507 55.764 20.543 59.292 ;
     RECT  20.507 60.858 20.543 62.334 ;
     RECT  20.507 63.324 20.543 63.342 ;
     RECT  20.507 64.098 20.543 64.692 ;
     RECT  20.507 66.258 20.543 68.4 ;
     RECT  20.543 6.822 20.579 6.84 ;
     RECT  20.543 11.826 20.579 14.364 ;
     RECT  20.507 16.38 20.579 17.514 ;
     RECT  20.543 18.27 20.579 18.288 ;
     RECT  20.543 22.212 20.579 24.768 ;
     RECT  20.543 33.696 20.579 34.758 ;
     RECT  20.543 37.476 20.579 39.384 ;
     RECT  20.543 43.308 20.579 44.514 ;
     RECT  20.543 50.94 20.579 51.192 ;
     RECT  20.543 55.764 20.579 57.906 ;
     RECT  20.543 67.104 20.579 68.4 ;
     RECT  20.579 16.578 20.615 17.514 ;
     RECT  20.579 24.138 20.615 24.768 ;
     RECT  20.579 34.056 20.615 34.758 ;
     RECT  20.579 38.718 20.615 39.384 ;
     RECT  20.543 42.156 20.615 42.552 ;
     RECT  20.579 50.94 20.615 50.958 ;
     RECT  20.615 16.686 20.651 17.514 ;
     RECT  20.615 42.156 20.651 42.174 ;
     RECT  19.44 4.23 21.299 5.094 ;
     RECT  21.299 4.23 21.335 4.824 ;
     RECT  21.335 4.23 21.371 4.554 ;
     RECT  20.543 19.278 21.371 20.916 ;
     RECT  21.371 4.266 21.407 4.554 ;
     RECT  20.507 7.596 21.407 8.262 ;
     RECT  21.371 20.628 21.407 20.916 ;
     RECT  20.507 26.226 21.407 28.476 ;
     RECT  20.507 30.96 21.407 31.554 ;
     RECT  20.543 45.81 21.407 47.304 ;
     RECT  20.543 48.402 21.407 48.456 ;
     RECT  20.579 67.644 21.407 68.4 ;
     RECT  21.407 4.266 21.443 4.284 ;
     RECT  21.407 7.596 21.443 7.614 ;
     RECT  20.507 9.018 21.443 9.036 ;
     RECT  20.543 9.828 21.443 9.846 ;
     RECT  20.543 10.836 21.443 10.854 ;
     RECT  20.579 11.952 21.443 13.554 ;
     RECT  20.579 14.346 21.443 14.364 ;
     RECT  20.507 15.57 21.443 15.588 ;
     RECT  20.651 16.776 21.443 17.514 ;
     RECT  21.371 19.278 21.443 19.872 ;
     RECT  21.407 20.628 21.443 20.646 ;
     RECT  20.579 22.212 21.443 22.914 ;
     RECT  20.615 24.75 21.443 24.768 ;
     RECT  21.407 26.226 21.443 26.586 ;
     RECT  21.407 27.342 21.443 28.476 ;
     RECT  20.507 29.538 21.443 30.204 ;
     RECT  21.407 30.96 21.443 31.248 ;
     RECT  20.507 32.616 21.443 32.634 ;
     RECT  20.615 34.128 21.443 34.758 ;
     RECT  20.579 37.944 21.443 37.962 ;
     RECT  20.615 38.826 21.443 39.384 ;
     RECT  20.543 40.446 21.443 41.166 ;
     RECT  20.579 43.308 21.443 43.326 ;
     RECT  20.579 44.496 21.443 44.514 ;
     RECT  21.407 46.08 21.443 47.304 ;
     RECT  21.407 48.438 21.443 48.456 ;
     RECT  20.543 49.518 21.443 49.914 ;
     RECT  20.543 51.948 21.443 53.316 ;
     RECT  20.507 54.306 21.443 54.936 ;
     RECT  20.579 55.764 21.443 57.204 ;
     RECT  20.543 58.806 21.443 59.292 ;
     RECT  20.543 61.704 21.443 62.064 ;
     RECT  20.543 64.674 21.443 64.692 ;
     RECT  20.507 69.768 21.443 69.786 ;
     RECT  19.44 72.936 21.551 72.954 ;
     RECT  21.443 26.568 21.587 26.586 ;
     RECT  21.443 46.206 21.587 46.224 ;
    LAYER M3 ;
     RECT  2.415 2.143 2.505 2.413 ;
     RECT  5.115 2.143 5.205 2.413 ;
     RECT  7.815 2.143 7.905 2.413 ;
     RECT  10.515 2.143 10.605 2.413 ;
     RECT  13.215 2.143 13.305 2.413 ;
     RECT  15.915 2.143 16.005 2.413 ;
     RECT  18.615 2.143 18.705 2.413 ;
     RECT  18.615 2.413 18.897 2.731 ;
     RECT  5.115 2.413 5.397 2.767 ;
     RECT  18.615 2.731 19.134 2.839 ;
     RECT  18.615 2.839 19.206 3.001 ;
     RECT  10.515 2.413 10.797 3.037 ;
     RECT  4.104 2.767 4.122 3.145 ;
     RECT  5.115 2.767 5.67 3.145 ;
     RECT  18.252 3.001 19.206 3.145 ;
     RECT  17.136 3.379 17.154 3.649 ;
     RECT  4.104 3.145 6.102 3.685 ;
     RECT  18.18 3.145 19.206 3.721 ;
     RECT  17.136 3.649 17.19 3.955 ;
     RECT  18.108 3.721 19.206 3.955 ;
     RECT  17.136 3.955 17.37 3.991 ;
     RECT  18.108 3.955 19.314 3.991 ;
     RECT  21.348 4.225 21.366 4.261 ;
     RECT  2.415 2.413 2.697 4.351 ;
     RECT  2.415 4.351 2.934 4.531 ;
     RECT  3.924 3.685 6.102 4.531 ;
     RECT  12.096 3.541 12.114 4.657 ;
     RECT  13.215 2.413 13.497 4.657 ;
     RECT  0.18 4.495 0.198 4.693 ;
     RECT  17.136 3.991 19.314 4.693 ;
     RECT  0.18 4.693 0.558 4.765 ;
     RECT  2.415 4.531 6.75 4.765 ;
     RECT  7.815 2.413 8.097 4.765 ;
     RECT  21.348 4.261 21.438 4.801 ;
     RECT  12.096 4.657 13.497 4.891 ;
     RECT  21.312 4.801 21.438 5.071 ;
     RECT  11.88 4.891 13.497 5.189 ;
     RECT  10.515 3.037 11.142 5.233 ;
     RECT  15.915 2.413 16.197 5.233 ;
     RECT  16.992 4.693 19.314 5.233 ;
     RECT  10.44 5.233 11.142 5.269 ;
     RECT  11.88 5.189 11.898 5.269 ;
     RECT  21.276 5.071 21.438 5.453 ;
     RECT  21.276 5.453 21.402 5.693 ;
     RECT  10.44 5.269 11.898 5.707 ;
     RECT  8.856 5.611 8.874 5.773 ;
     RECT  2.415 4.765 8.097 5.809 ;
     RECT  8.856 5.773 8.946 5.809 ;
     RECT  2.304 5.809 8.097 5.851 ;
     RECT  8.856 5.809 9.342 5.851 ;
     RECT  14.832 5.809 14.85 5.881 ;
     RECT  10.116 5.707 11.898 5.909 ;
     RECT  21.276 5.693 21.366 5.933 ;
     RECT  12.636 5.189 13.497 6.007 ;
     RECT  10.116 5.909 11.25 6.035 ;
     RECT  21.276 5.933 21.33 6.077 ;
     RECT  14.832 5.881 14.886 6.107 ;
     RECT  21.276 6.077 21.294 6.173 ;
     RECT  10.296 6.035 11.25 6.179 ;
     RECT  14.868 6.107 14.886 6.269 ;
     RECT  15.915 5.233 19.314 6.313 ;
     RECT  2.304 5.851 9.342 6.413 ;
     RECT  15.915 6.313 19.422 6.421 ;
     RECT  2.304 6.413 9.306 6.575 ;
     RECT  15.84 6.421 19.422 6.691 ;
     RECT  20.52 6.619 20.538 6.691 ;
     RECT  15.84 6.691 20.538 6.809 ;
     RECT  15.915 6.809 20.538 6.817 ;
     RECT  15.915 6.817 20.574 7.085 ;
     RECT  2.415 6.575 9.306 7.195 ;
     RECT  12.312 6.007 13.497 7.619 ;
     RECT  21.42 7.591 21.438 7.663 ;
     RECT  0.144 4.765 0.558 7.709 ;
     RECT  2.415 7.195 9.486 7.735 ;
     RECT  10.296 6.179 10.797 7.735 ;
     RECT  15.915 7.085 20.502 7.763 ;
     RECT  2.415 7.735 10.797 7.819 ;
     RECT  2.412 7.819 10.797 7.963 ;
     RECT  2.304 7.963 10.797 8.059 ;
     RECT  21.312 7.663 21.438 8.237 ;
     RECT  2.268 8.059 10.797 8.267 ;
     RECT  2.268 8.267 9.414 8.303 ;
     RECT  2.304 8.303 9.414 8.429 ;
     RECT  12.564 7.619 13.497 8.429 ;
     RECT  15.915 7.763 19.206 8.581 ;
     RECT  15.696 8.581 19.206 8.587 ;
     RECT  19.944 7.763 20.502 8.587 ;
     RECT  0.144 7.709 0.162 8.621 ;
     RECT  14.832 8.671 14.85 8.707 ;
     RECT  14.832 8.707 14.922 8.771 ;
     RECT  10.296 8.267 10.797 8.779 ;
     RECT  14.904 8.771 14.922 8.843 ;
     RECT  15.696 8.587 20.502 8.851 ;
     RECT  10.296 8.779 10.854 8.879 ;
     RECT  2.304 8.429 9.018 8.969 ;
     RECT  13.068 8.429 13.497 8.969 ;
     RECT  15.408 8.851 20.502 8.969 ;
     RECT  21.312 8.237 21.402 9.013 ;
     RECT  2.304 8.969 7.038 9.149 ;
     RECT  2.304 9.149 6.93 9.311 ;
     RECT  7.776 8.969 9.018 9.319 ;
     RECT  10.296 8.879 10.797 9.319 ;
     RECT  15.915 8.969 20.502 9.389 ;
     RECT  7.776 9.319 10.797 9.509 ;
     RECT  19.908 9.389 20.502 9.689 ;
     RECT  0.144 9.517 0.162 9.773 ;
     RECT  21.312 9.013 21.438 9.851 ;
     RECT  15.915 9.389 19.134 9.859 ;
     RECT  13.215 8.969 13.497 9.931 ;
     RECT  15.336 9.859 19.134 9.959 ;
     RECT  21.312 9.851 21.33 10.013 ;
     RECT  2.304 9.311 6.822 10.057 ;
     RECT  13.215 9.931 13.698 10.085 ;
     RECT  2.304 10.057 6.93 10.093 ;
     RECT  7.776 9.509 8.982 10.093 ;
     RECT  9.72 9.509 10.797 10.093 ;
     RECT  20.16 9.689 20.502 10.093 ;
     RECT  9.72 10.093 10.854 10.229 ;
     RECT  2.304 10.093 8.982 10.291 ;
     RECT  9.72 10.229 10.797 10.291 ;
     RECT  20.16 10.093 20.538 10.435 ;
     RECT  20.124 10.435 20.538 10.507 ;
     RECT  0.216 10.651 0.234 10.781 ;
     RECT  15.588 9.959 19.134 10.831 ;
     RECT  21.42 10.747 21.438 10.859 ;
     RECT  15.516 10.831 19.134 10.939 ;
     RECT  2.304 10.291 10.797 11.011 ;
     RECT  15.372 10.939 19.134 11.011 ;
     RECT  14.724 11.011 19.134 11.129 ;
     RECT  14.724 11.129 14.85 11.237 ;
     RECT  14.832 11.237 14.85 11.273 ;
     RECT  15.696 11.129 19.134 11.435 ;
     RECT  12.348 11.281 12.366 11.443 ;
     RECT  13.215 10.085 13.497 11.443 ;
     RECT  19.908 10.507 20.538 11.515 ;
     RECT  19.872 11.515 20.538 11.741 ;
     RECT  2.304 11.011 10.926 11.785 ;
     RECT  19.908 11.741 20.538 11.821 ;
     RECT  12.348 11.443 13.497 12.055 ;
     RECT  19.908 11.821 20.574 12.055 ;
     RECT  12.168 12.055 13.497 12.209 ;
     RECT  15.696 11.435 18.954 12.209 ;
     RECT  19.908 12.055 20.61 12.209 ;
     RECT  15.804 12.209 18.954 12.361 ;
     RECT  2.268 11.785 11.07 12.461 ;
     RECT  19.944 12.209 20.61 12.461 ;
     RECT  15.804 12.361 19.098 12.517 ;
     RECT  0.144 12.487 0.162 12.523 ;
     RECT  2.304 12.461 11.07 12.605 ;
     RECT  2.304 12.605 9.702 12.623 ;
     RECT  20.484 12.461 20.61 12.701 ;
     RECT  12.78 12.209 13.497 12.829 ;
     RECT  2.304 12.623 9.63 12.893 ;
     RECT  0.144 12.523 0.198 12.907 ;
     RECT  0.144 12.907 0.234 12.955 ;
     RECT  12.78 12.829 13.59 13.019 ;
     RECT  14.976 12.901 14.994 13.019 ;
     RECT  0.144 12.955 0.306 13.027 ;
     RECT  0.036 13.027 0.306 13.055 ;
     RECT  15.804 12.517 19.17 13.099 ;
     RECT  12.78 13.019 13.497 13.171 ;
     RECT  15.048 13.099 19.17 13.195 ;
     RECT  12.528 13.171 13.497 13.289 ;
     RECT  0.036 13.055 0.234 13.397 ;
     RECT  0.216 13.397 0.234 13.421 ;
     RECT  2.304 12.893 9.342 13.432 ;
     RECT  2.232 13.432 9.342 13.469 ;
     RECT  15.048 13.195 19.386 13.559 ;
     RECT  20.484 12.701 20.502 13.579 ;
     RECT  2.268 13.469 9.342 13.613 ;
     RECT  15.372 13.559 19.386 13.631 ;
     RECT  15.372 13.631 19.098 13.865 ;
     RECT  20.232 13.579 20.502 13.909 ;
     RECT  20.232 13.909 20.538 14.071 ;
     RECT  15.372 13.865 19.026 14.099 ;
     RECT  20.232 14.071 20.574 14.347 ;
     RECT  21.42 11.947 21.438 14.369 ;
     RECT  2.268 13.613 9.234 14.377 ;
     RECT  10.515 12.605 11.07 14.377 ;
     RECT  19.908 14.347 20.574 14.441 ;
     RECT  19.944 14.441 20.574 14.621 ;
     RECT  19.944 14.621 20.502 14.639 ;
     RECT  2.268 14.377 11.07 14.675 ;
     RECT  19.944 14.639 20.25 14.819 ;
     RECT  15.408 14.099 19.026 14.827 ;
     RECT  2.304 14.675 11.07 14.909 ;
     RECT  15.408 14.827 19.062 14.917 ;
     RECT  14.868 14.917 19.062 15.089 ;
     RECT  19.944 14.819 19.962 15.149 ;
     RECT  13.215 13.289 13.497 15.151 ;
     RECT  15.408 15.089 19.062 15.151 ;
     RECT  13.104 15.151 13.497 15.197 ;
     RECT  0.216 15.259 0.234 15.389 ;
     RECT  15.408 15.151 19.098 15.787 ;
     RECT  2.304 14.909 3.294 15.799 ;
     RECT  4.104 14.909 11.07 15.799 ;
     RECT  15.408 15.787 19.386 15.917 ;
     RECT  15.408 15.917 19.134 15.961 ;
     RECT  20.484 15.592 20.502 15.979 ;
     RECT  14.508 15.961 19.134 16.013 ;
     RECT  15.228 16.013 19.134 16.061 ;
     RECT  20.196 15.979 20.502 16.375 ;
     RECT  21.42 15.355 21.438 16.507 ;
     RECT  20.196 16.375 20.574 16.573 ;
     RECT  15.3 16.061 19.134 16.589 ;
     RECT  20.196 16.573 20.61 16.609 ;
     RECT  19.944 16.609 20.61 16.681 ;
     RECT  2.304 15.799 11.07 16.747 ;
     RECT  2.268 16.747 11.07 16.835 ;
     RECT  19.944 16.681 20.646 16.925 ;
     RECT  21.384 16.507 21.438 17.069 ;
     RECT  15.3 16.589 19.098 17.179 ;
     RECT  15.192 17.179 19.098 17.383 ;
     RECT  0.216 17.275 0.234 17.405 ;
     RECT  0.144 17.455 0.162 17.693 ;
     RECT  20.448 16.925 20.646 17.693 ;
     RECT  2.304 16.835 11.07 17.761 ;
     RECT  2.304 17.761 11.178 17.803 ;
     RECT  21.42 17.069 21.438 17.837 ;
     RECT  14.868 17.383 19.098 17.879 ;
     RECT  14.868 17.879 14.886 17.987 ;
     RECT  20.448 17.693 20.574 18.301 ;
     RECT  19.944 18.301 20.574 18.427 ;
     RECT  15.66 17.879 19.098 18.715 ;
     RECT  2.268 17.803 11.178 18.749 ;
     RECT  15.66 18.715 19.134 19.039 ;
     RECT  19.908 18.427 20.574 19.039 ;
     RECT  15.516 19.039 20.574 19.085 ;
     RECT  15.516 19.085 20.538 19.381 ;
     RECT  2.268 18.749 6.606 19.507 ;
     RECT  7.56 18.749 11.178 19.507 ;
     RECT  2.268 19.507 6.786 19.571 ;
     RECT  14.544 18.301 14.562 19.651 ;
     RECT  15.3 19.381 20.538 19.651 ;
     RECT  14.256 19.651 20.538 19.769 ;
     RECT  2.304 19.571 6.786 19.777 ;
     RECT  7.524 19.507 11.178 19.777 ;
     RECT  14.256 19.769 14.274 19.841 ;
     RECT  15.372 19.769 20.538 19.913 ;
     RECT  0.54 19.921 0.558 20.093 ;
     RECT  13.215 15.197 13.497 20.191 ;
     RECT  21.42 19.273 21.438 20.347 ;
     RECT  21.384 20.347 21.438 20.461 ;
     RECT  15.372 19.913 19.422 20.587 ;
     RECT  20.484 19.913 20.538 20.621 ;
     RECT  21.348 20.461 21.438 20.651 ;
     RECT  21.348 20.651 21.402 20.765 ;
     RECT  15.264 20.587 19.422 20.821 ;
     RECT  14.616 20.821 19.422 20.861 ;
     RECT  13.215 20.191 13.878 20.893 ;
     RECT  14.616 20.861 19.026 20.893 ;
     RECT  21.384 20.765 21.402 20.921 ;
     RECT  20.484 20.621 20.502 20.971 ;
     RECT  13.215 20.893 19.026 21.119 ;
     RECT  13.215 21.119 18.99 21.155 ;
     RECT  20.232 20.971 20.502 21.163 ;
     RECT  0.216 21.451 0.234 21.629 ;
     RECT  13.215 21.155 13.734 21.659 ;
     RECT  19.944 21.163 20.502 21.739 ;
     RECT  14.832 21.155 18.99 21.979 ;
     RECT  19.944 21.739 20.538 21.979 ;
     RECT  0.144 22.207 0.162 22.363 ;
     RECT  0.144 22.363 0.234 22.493 ;
     RECT  14.832 21.979 20.538 22.541 ;
     RECT  14.832 22.541 19.422 22.621 ;
     RECT  14.76 22.621 19.422 22.739 ;
     RECT  21.42 22.207 21.438 22.919 ;
     RECT  0.144 22.493 0.162 22.925 ;
     RECT  14.832 22.739 19.422 23.189 ;
     RECT  2.304 19.777 11.178 23.251 ;
     RECT  20.484 22.541 20.538 23.419 ;
     RECT  19.908 23.419 20.538 23.459 ;
     RECT  19.944 23.459 20.538 23.521 ;
     RECT  0.216 23.419 0.234 23.597 ;
     RECT  13.215 21.659 13.662 23.665 ;
     RECT  13.215 23.665 13.77 23.819 ;
     RECT  19.944 23.521 20.574 23.837 ;
     RECT  12.384 23.707 12.402 23.891 ;
     RECT  13.215 23.819 13.497 23.899 ;
     RECT  20.16 23.837 20.574 24.133 ;
     RECT  14.832 23.189 19.062 24.205 ;
     RECT  20.16 24.133 20.61 24.269 ;
     RECT  2.304 23.251 11.502 24.283 ;
     RECT  2.268 24.283 11.502 24.467 ;
     RECT  14.832 24.205 19.134 24.673 ;
     RECT  21.42 24.667 21.438 24.773 ;
     RECT  14.724 24.673 19.134 24.781 ;
     RECT  14.652 24.781 19.134 24.943 ;
     RECT  14.652 24.943 19.422 25.169 ;
     RECT  15.156 25.169 19.422 25.195 ;
     RECT  20.484 24.269 20.61 25.195 ;
     RECT  2.304 24.467 11.502 25.249 ;
     RECT  15.156 25.195 20.61 25.277 ;
     RECT  2.268 25.249 11.502 25.439 ;
     RECT  0.54 25.015 0.558 25.613 ;
     RECT  15.915 25.277 20.61 25.781 ;
     RECT  15.156 25.277 15.174 25.979 ;
     RECT  15.915 25.781 19.17 26.051 ;
     RECT  20.448 25.781 20.61 26.051 ;
     RECT  12.564 23.899 13.497 26.221 ;
     RECT  15.915 26.051 19.098 26.285 ;
     RECT  21.42 26.107 21.438 26.491 ;
     RECT  20.484 26.051 20.61 26.539 ;
     RECT  21.384 26.491 21.438 26.539 ;
     RECT  20.484 26.539 21.438 26.563 ;
     RECT  0.216 25.963 0.234 26.587 ;
     RECT  20.484 26.563 21.582 26.621 ;
     RECT  0.036 26.587 0.234 26.699 ;
     RECT  0.144 26.699 0.234 26.717 ;
     RECT  12.564 26.221 13.59 26.761 ;
     RECT  20.484 26.621 21.438 26.765 ;
     RECT  15.915 26.285 18.954 26.833 ;
     RECT  14.94 26.869 14.958 26.941 ;
     RECT  15.696 26.833 18.954 26.941 ;
     RECT  2.304 25.439 11.502 26.971 ;
     RECT  2.268 26.971 11.502 27.031 ;
     RECT  12.42 26.761 13.59 27.031 ;
     RECT  14.94 26.941 18.954 27.031 ;
     RECT  2.268 27.031 13.59 27.059 ;
     RECT  14.94 27.031 19.494 27.059 ;
     RECT  20.484 26.765 20.61 27.149 ;
     RECT  2.268 27.059 13.554 27.365 ;
     RECT  15.048 27.059 19.494 27.389 ;
     RECT  15.048 27.389 19.242 27.599 ;
     RECT  15.3 27.599 19.242 27.869 ;
     RECT  2.304 27.365 13.497 27.905 ;
     RECT  20.484 27.149 20.502 28.027 ;
     RECT  0.144 26.717 0.162 28.061 ;
     RECT  2.304 27.905 11.502 28.123 ;
     RECT  15.372 27.869 19.242 28.123 ;
     RECT  20.196 28.027 20.502 28.123 ;
     RECT  2.268 28.123 11.502 28.283 ;
     RECT  21.384 26.765 21.438 28.445 ;
     RECT  2.304 28.283 11.502 28.679 ;
     RECT  15.372 28.123 20.502 28.687 ;
     RECT  0.216 28.651 0.234 28.957 ;
     RECT  0.144 28.957 0.234 29.029 ;
     RECT  0.144 29.029 0.558 29.213 ;
     RECT  0.54 29.213 0.558 29.309 ;
     RECT  14.868 28.687 20.502 29.453 ;
     RECT  2.304 28.679 3.654 29.461 ;
     RECT  14.868 29.453 19.134 29.461 ;
     RECT  4.5 28.679 11.502 29.497 ;
     RECT  4.464 29.497 11.502 29.525 ;
     RECT  14.508 29.461 19.134 29.597 ;
     RECT  2.304 29.461 3.726 29.767 ;
     RECT  4.464 29.525 10.962 29.767 ;
     RECT  19.908 29.453 20.502 29.939 ;
     RECT  2.304 29.767 10.962 30.029 ;
     RECT  0.216 30.091 0.234 30.145 ;
     RECT  15.048 29.597 19.134 30.299 ;
     RECT  0.144 30.145 0.234 30.413 ;
     RECT  2.304 30.029 10.89 30.479 ;
     RECT  2.304 30.479 10.854 30.605 ;
     RECT  9.936 30.605 10.854 30.641 ;
     RECT  9.972 30.641 10.854 30.677 ;
     RECT  20.196 29.939 20.502 30.749 ;
     RECT  21.42 28.445 21.438 30.811 ;
     RECT  15.732 30.299 19.134 31.117 ;
     RECT  15.732 31.117 19.17 31.147 ;
     RECT  21.384 30.811 21.438 31.195 ;
     RECT  15.732 31.147 19.206 31.225 ;
     RECT  21.348 31.195 21.438 31.253 ;
     RECT  15.696 31.225 19.206 31.261 ;
     RECT  21.348 31.253 21.402 31.339 ;
     RECT  14.832 30.613 14.85 31.351 ;
     RECT  15.696 31.261 19.314 31.351 ;
     RECT  0.144 30.413 0.198 31.373 ;
     RECT  2.304 30.605 8.874 31.379 ;
     RECT  14.832 31.351 19.314 31.387 ;
     RECT  14.58 31.387 19.314 31.421 ;
     RECT  9.972 30.677 10.797 31.423 ;
     RECT  0.18 31.373 0.198 31.469 ;
     RECT  21.312 31.339 21.402 31.487 ;
     RECT  6.84 31.379 8.874 31.531 ;
     RECT  21.384 31.487 21.402 31.559 ;
     RECT  15.732 31.421 19.314 31.579 ;
     RECT  6.84 31.531 8.946 31.657 ;
     RECT  15.732 31.579 19.386 31.693 ;
     RECT  20.412 30.749 20.502 31.693 ;
     RECT  9.864 31.423 10.797 31.729 ;
     RECT  12.564 27.905 13.497 31.793 ;
     RECT  6.84 31.657 9.09 31.801 ;
     RECT  9.864 31.729 10.854 31.801 ;
     RECT  14.58 31.421 14.886 32.035 ;
     RECT  6.84 31.801 10.926 32.155 ;
     RECT  14.256 32.035 14.886 32.161 ;
     RECT  15.732 31.693 20.502 32.161 ;
     RECT  2.304 31.379 5.922 32.305 ;
     RECT  2.268 32.305 5.922 32.341 ;
     RECT  2.268 32.341 6.03 32.347 ;
     RECT  6.768 32.155 10.926 32.347 ;
     RECT  14.256 32.161 20.502 32.369 ;
     RECT  2.268 32.347 10.926 32.539 ;
     RECT  2.268 32.539 10.998 32.639 ;
     RECT  21.42 32.611 21.438 32.765 ;
     RECT  12.636 31.793 13.497 32.845 ;
     RECT  14.256 32.369 14.274 32.845 ;
     RECT  2.268 32.639 10.854 32.909 ;
     RECT  15.156 32.369 20.502 32.999 ;
     RECT  2.268 32.909 10.797 33.035 ;
     RECT  15.732 32.999 20.502 33.071 ;
     RECT  12.636 32.845 14.274 33.115 ;
     RECT  12.636 33.115 14.85 33.259 ;
     RECT  12.456 33.259 14.85 33.269 ;
     RECT  19.98 33.071 20.502 33.293 ;
     RECT  12.456 33.269 14.814 33.305 ;
     RECT  20.484 33.293 20.502 33.421 ;
     RECT  0.54 33.385 0.558 33.499 ;
     RECT  0.036 33.499 0.558 33.539 ;
     RECT  12.6 33.305 14.814 33.575 ;
     RECT  12.6 33.575 13.95 33.581 ;
     RECT  0.216 33.539 0.558 33.629 ;
     RECT  20.484 33.421 20.538 33.691 ;
     RECT  0.54 33.629 0.558 33.773 ;
     RECT  12.6 33.581 13.698 33.809 ;
     RECT  15.732 33.071 19.134 33.853 ;
     RECT  2.304 33.035 10.797 33.925 ;
     RECT  20.484 33.691 20.574 34.027 ;
     RECT  19.908 34.027 20.574 34.051 ;
     RECT  2.304 33.925 10.854 34.079 ;
     RECT  21.42 33.883 21.438 34.15 ;
     RECT  15.66 33.853 19.134 34.195 ;
     RECT  21.384 34.15 21.438 34.301 ;
     RECT  14.796 33.575 14.814 34.321 ;
     RECT  15.588 34.195 19.134 34.321 ;
     RECT  14.796 34.321 19.134 34.411 ;
     RECT  14.76 34.411 19.134 34.457 ;
     RECT  14.94 34.457 19.134 34.529 ;
     RECT  2.304 34.079 10.797 34.691 ;
     RECT  21.42 34.301 21.438 34.763 ;
     RECT  19.908 34.051 20.61 34.925 ;
     RECT  1.332 32.587 1.35 34.997 ;
     RECT  2.304 34.691 8.874 35.005 ;
     RECT  2.268 35.005 8.874 35.069 ;
     RECT  15.408 34.529 19.134 35.401 ;
     RECT  2.304 35.069 8.874 35.419 ;
     RECT  9.72 34.691 10.797 35.419 ;
     RECT  2.304 35.419 10.797 35.437 ;
     RECT  2.304 35.437 10.854 35.509 ;
     RECT  12.6 33.809 13.497 35.509 ;
     RECT  0.144 35.563 0.162 35.581 ;
     RECT  12.6 35.509 13.734 35.581 ;
     RECT  0.144 35.581 0.234 35.609 ;
     RECT  12.6 35.581 13.914 35.803 ;
     RECT  15.372 35.401 19.134 35.851 ;
     RECT  19.908 34.925 20.538 35.851 ;
     RECT  12.564 35.803 13.914 35.941 ;
     RECT  12.564 35.941 13.95 36.013 ;
     RECT  15.372 35.851 20.538 36.041 ;
     RECT  2.304 35.509 10.926 36.049 ;
     RECT  12.564 36.013 14.346 36.049 ;
     RECT  15.372 36.041 19.206 36.049 ;
     RECT  2.304 36.049 10.962 36.085 ;
     RECT  12.564 36.049 19.206 36.235 ;
     RECT  2.304 36.085 11.034 36.239 ;
     RECT  12.384 36.235 19.206 36.239 ;
     RECT  12.384 36.239 12.402 36.311 ;
     RECT  2.304 36.239 10.926 36.347 ;
     RECT  13.14 36.239 13.95 36.356 ;
     RECT  20.196 36.041 20.538 36.365 ;
     RECT  13.176 36.356 13.95 36.509 ;
     RECT  0.216 35.609 0.234 36.619 ;
     RECT  14.688 36.239 19.206 36.779 ;
     RECT  0.216 36.619 0.306 36.811 ;
     RECT  21.384 36.523 21.402 36.845 ;
     RECT  0.144 36.811 0.306 36.851 ;
     RECT  0.216 36.851 0.306 36.989 ;
     RECT  0.216 36.989 0.234 37.037 ;
     RECT  15.3 36.779 19.206 37.049 ;
     RECT  2.304 36.347 10.89 37.121 ;
     RECT  20.196 36.365 20.502 37.129 ;
     RECT  19.944 37.129 20.502 37.165 ;
     RECT  9.252 37.121 10.89 37.471 ;
     RECT  19.944 37.165 20.538 37.471 ;
     RECT  19.944 37.471 20.574 37.517 ;
     RECT  15.516 37.049 19.206 37.561 ;
     RECT  9.252 37.471 10.926 37.613 ;
     RECT  15.516 37.561 19.422 37.613 ;
     RECT  2.304 37.121 8.37 37.867 ;
     RECT  9.72 37.613 10.926 37.867 ;
     RECT  9.72 37.867 10.998 37.963 ;
     RECT  9.72 37.963 11.034 38.129 ;
     RECT  15.516 37.613 19.098 38.209 ;
     RECT  20.52 37.517 20.574 38.245 ;
     RECT  15.48 38.209 19.098 38.281 ;
     RECT  2.304 37.867 8.766 38.347 ;
     RECT  2.268 38.347 8.766 38.491 ;
     RECT  19.944 38.245 20.574 38.491 ;
     RECT  2.268 38.491 8.802 38.551 ;
     RECT  2.268 38.551 8.946 38.635 ;
     RECT  9.72 38.129 10.854 38.635 ;
     RECT  15.336 38.281 19.098 38.641 ;
     RECT  19.908 38.491 20.574 38.713 ;
     RECT  19.908 38.713 20.61 38.765 ;
     RECT  2.268 38.635 10.854 38.911 ;
     RECT  2.268 38.911 10.926 39.01 ;
     RECT  2.268 39.01 10.962 39.047 ;
     RECT  2.304 39.047 10.962 39.053 ;
     RECT  15.264 38.641 19.098 39.055 ;
     RECT  14.724 39.055 19.134 39.091 ;
     RECT  14.724 39.091 19.422 39.149 ;
     RECT  14.724 39.149 19.278 39.209 ;
     RECT  0.216 39.115 0.234 39.245 ;
     RECT  14.796 39.209 19.278 39.281 ;
     RECT  2.304 39.053 10.89 39.293 ;
     RECT  21.42 37.939 21.438 39.389 ;
     RECT  20.484 38.765 20.61 39.533 ;
     RECT  2.304 39.293 10.854 39.581 ;
     RECT  20.484 39.533 20.502 39.784 ;
     RECT  20.448 39.784 20.502 39.883 ;
     RECT  0.54 39.865 0.558 39.917 ;
     RECT  20.232 39.883 20.502 40.019 ;
     RECT  15.408 39.281 19.278 40.063 ;
     RECT  20.232 40.019 20.25 40.135 ;
     RECT  20.196 40.135 20.25 40.199 ;
     RECT  20.196 40.199 20.214 40.205 ;
     RECT  0.216 40.267 0.234 40.397 ;
     RECT  2.304 39.581 10.797 40.507 ;
     RECT  2.268 40.507 10.797 40.531 ;
     RECT  15.192 40.063 19.278 40.559 ;
     RECT  15.876 40.559 19.278 40.603 ;
     RECT  2.268 40.531 10.89 40.667 ;
     RECT  15.876 40.603 19.422 40.891 ;
     RECT  21.42 40.441 21.438 41.171 ;
     RECT  14.868 40.567 14.886 41.179 ;
     RECT  15.876 40.891 19.926 41.179 ;
     RECT  14.832 41.179 14.886 41.477 ;
     RECT  2.268 40.667 10.854 41.597 ;
     RECT  15.876 41.179 20.502 41.707 ;
     RECT  2.304 41.597 10.854 41.719 ;
     RECT  14.94 41.707 20.502 41.719 ;
     RECT  21.384 41.803 21.402 41.933 ;
     RECT  2.304 41.719 10.926 41.947 ;
     RECT  2.304 41.947 10.962 42.077 ;
     RECT  14.94 41.719 20.538 42.151 ;
     RECT  14.94 42.151 20.646 42.449 ;
     RECT  15.3 42.449 20.646 42.461 ;
     RECT  15.3 42.461 19.422 42.719 ;
     RECT  15.408 42.719 19.422 43.169 ;
     RECT  0.144 42.727 0.162 43.195 ;
     RECT  0.144 43.195 0.234 43.325 ;
     RECT  0.144 43.325 0.162 43.517 ;
     RECT  20.484 42.461 20.646 43.517 ;
     RECT  2.304 42.077 10.926 43.529 ;
     RECT  15.408 43.169 19.098 43.529 ;
     RECT  15.408 43.529 19.062 43.573 ;
     RECT  15.264 43.573 19.062 43.609 ;
     RECT  14.868 43.609 19.062 43.709 ;
     RECT  20.484 43.517 20.574 43.723 ;
     RECT  20.232 43.723 20.574 43.997 ;
     RECT  20.232 43.997 20.502 44.041 ;
     RECT  2.304 43.529 10.89 44.249 ;
     RECT  0.144 44.347 0.162 44.419 ;
     RECT  15.192 43.709 19.062 44.455 ;
     RECT  19.944 44.041 20.502 44.455 ;
     RECT  21.42 43.303 21.438 44.519 ;
     RECT  0.144 44.419 0.558 44.525 ;
     RECT  15.192 44.455 20.502 44.587 ;
     RECT  0.54 44.525 0.558 44.669 ;
     RECT  14.832 44.587 20.502 44.669 ;
     RECT  13.215 36.509 13.95 45.121 ;
     RECT  14.832 44.669 19.098 45.121 ;
     RECT  2.304 44.249 10.797 45.265 ;
     RECT  2.304 45.265 10.926 45.403 ;
     RECT  13.215 45.121 19.098 45.491 ;
     RECT  19.944 44.669 20.502 45.533 ;
     RECT  20.448 45.533 20.502 45.563 ;
     RECT  20.484 45.563 20.502 45.571 ;
     RECT  13.215 45.491 19.062 45.599 ;
     RECT  2.268 45.403 10.926 45.761 ;
     RECT  21.42 45.787 21.438 45.805 ;
     RECT  6.732 45.761 10.926 45.869 ;
     RECT  14.976 45.599 19.062 45.959 ;
     RECT  6.732 45.869 10.89 45.965 ;
     RECT  21.384 45.805 21.438 46.111 ;
     RECT  21.312 46.111 21.438 46.171 ;
     RECT  21.312 46.171 21.582 46.229 ;
     RECT  21.312 46.229 21.438 46.301 ;
     RECT  15.48 45.959 19.062 46.345 ;
     RECT  15.48 46.345 19.098 46.381 ;
     RECT  2.268 45.761 5.886 46.445 ;
     RECT  15.48 46.381 19.314 46.499 ;
     RECT  2.304 46.445 5.886 46.555 ;
     RECT  6.732 45.965 10.797 46.555 ;
     RECT  20.484 45.571 20.538 46.651 ;
     RECT  2.304 46.555 10.797 46.741 ;
     RECT  2.304 46.741 10.998 46.949 ;
     RECT  20.484 46.651 20.574 47.069 ;
     RECT  2.304 46.949 10.926 47.111 ;
     RECT  15.732 46.499 19.314 47.155 ;
     RECT  20.484 47.069 20.538 47.155 ;
     RECT  15.732 47.155 20.538 47.281 ;
     RECT  15.66 47.281 20.538 47.353 ;
     RECT  2.304 47.111 10.854 47.425 ;
     RECT  15.084 47.353 20.538 47.453 ;
     RECT  15.084 47.453 20.502 47.579 ;
     RECT  15.732 47.579 20.502 47.597 ;
     RECT  20.484 47.597 20.502 47.849 ;
     RECT  0.54 47.659 0.558 47.981 ;
     RECT  2.268 47.425 10.854 48.001 ;
     RECT  13.215 45.599 13.95 48.127 ;
     RECT  12.6 48.127 13.95 48.227 ;
     RECT  2.268 48.001 10.926 48.299 ;
     RECT  13.215 48.227 13.95 48.397 ;
     RECT  21.42 46.301 21.438 48.397 ;
     RECT  13.215 48.397 14.022 48.469 ;
     RECT  14.832 48.091 14.85 48.469 ;
     RECT  21.384 48.397 21.438 48.509 ;
     RECT  13.215 48.469 14.85 48.569 ;
     RECT  2.268 48.299 10.797 48.659 ;
     RECT  13.215 48.569 14.13 48.659 ;
     RECT  15.732 47.597 19.422 48.715 ;
     RECT  0.144 48.397 0.162 48.749 ;
     RECT  21.384 48.509 21.402 48.893 ;
     RECT  15.732 48.715 19.926 48.901 ;
     RECT  15.732 48.901 20.538 49.009 ;
     RECT  2.304 48.659 10.797 49.379 ;
     RECT  2.304 49.379 5.397 49.477 ;
     RECT  15.372 49.009 20.538 49.517 ;
     RECT  2.268 49.477 5.397 49.723 ;
     RECT  20.16 49.517 20.538 49.757 ;
     RECT  15.372 49.517 19.314 49.981 ;
     RECT  14.832 49.981 19.314 50.009 ;
     RECT  2.232 49.723 5.397 50.045 ;
     RECT  21.42 49.513 21.438 50.141 ;
     RECT  14.832 50.009 14.85 50.153 ;
     RECT  0.216 50.491 0.234 50.593 ;
     RECT  6.12 49.379 10.797 50.629 ;
     RECT  15.588 50.009 19.314 50.669 ;
     RECT  6.12 50.629 10.854 50.693 ;
     RECT  20.16 49.757 20.502 50.779 ;
     RECT  0.144 50.593 0.234 50.813 ;
     RECT  21.384 50.395 21.402 50.861 ;
     RECT  19.908 50.779 20.502 50.875 ;
     RECT  13.215 48.659 13.95 50.899 ;
     RECT  19.908 50.875 20.538 50.935 ;
     RECT  14.796 50.791 14.814 50.963 ;
     RECT  2.304 50.045 5.397 50.971 ;
     RECT  6.12 50.693 10.797 50.971 ;
     RECT  12.96 50.899 13.95 50.999 ;
     RECT  0.216 50.813 0.234 51.149 ;
     RECT  15.588 50.669 19.17 51.197 ;
     RECT  2.304 50.971 10.797 51.241 ;
     RECT  14.832 51.097 14.85 51.241 ;
     RECT  15.588 51.197 19.098 51.241 ;
     RECT  19.908 50.935 20.61 51.293 ;
     RECT  2.268 51.241 10.797 51.475 ;
     RECT  19.908 51.293 20.538 51.643 ;
     RECT  14.832 51.241 19.098 51.737 ;
     RECT  15.192 51.737 19.098 51.931 ;
     RECT  19.872 51.643 20.538 51.931 ;
     RECT  0.216 51.883 0.234 52.013 ;
     RECT  13.215 50.999 13.95 52.141 ;
     RECT  2.268 51.475 10.854 52.177 ;
     RECT  15.192 51.931 20.538 52.313 ;
     RECT  2.268 52.177 11.034 52.349 ;
     RECT  12.744 52.141 13.95 52.439 ;
     RECT  15.192 52.313 20.502 52.439 ;
     RECT  2.268 52.349 10.926 52.717 ;
     RECT  2.232 52.717 10.926 52.781 ;
     RECT  15.915 52.439 20.502 52.781 ;
     RECT  19.908 52.781 20.502 52.829 ;
     RECT  2.232 52.781 10.797 52.973 ;
     RECT  14.832 52.519 14.922 52.979 ;
     RECT  0.54 52.861 0.558 53.419 ;
     RECT  0.216 53.419 0.558 53.563 ;
     RECT  2.304 52.973 10.797 53.599 ;
     RECT  15.915 52.781 19.134 53.599 ;
     RECT  0.144 53.563 0.558 53.6 ;
     RECT  0.54 53.6 0.558 53.741 ;
     RECT  21.42 51.943 21.438 53.851 ;
     RECT  2.304 53.599 10.854 53.905 ;
     RECT  2.268 53.905 10.854 53.933 ;
     RECT  15.516 53.599 19.134 53.941 ;
     RECT  19.944 52.829 20.502 53.941 ;
     RECT  15.516 53.941 20.502 54.131 ;
     RECT  21.348 53.851 21.438 54.221 ;
     RECT  21.384 54.221 21.438 54.401 ;
     RECT  20.448 54.131 20.502 54.445 ;
     RECT  15.516 54.131 19.314 54.481 ;
     RECT  15.48 54.481 19.314 54.599 ;
     RECT  20.448 54.445 20.574 54.604 ;
     RECT  2.268 53.933 10.797 54.635 ;
     RECT  13.215 52.439 13.95 54.913 ;
     RECT  14.832 54.607 15.066 54.913 ;
     RECT  0.216 54.715 0.234 54.941 ;
     RECT  20.448 54.604 20.61 54.955 ;
     RECT  15.915 54.599 19.314 55.099 ;
     RECT  20.34 54.955 20.61 55.099 ;
     RECT  2.304 54.635 10.797 55.111 ;
     RECT  13.215 54.913 15.066 55.175 ;
     RECT  15.915 55.099 20.61 55.277 ;
     RECT  15.915 55.277 20.538 55.517 ;
     RECT  20.448 55.517 20.538 55.553 ;
     RECT  14.832 55.175 15.066 55.561 ;
     RECT  15.915 55.517 19.386 55.561 ;
     RECT  14.832 55.561 19.386 55.757 ;
     RECT  2.304 55.111 10.818 55.795 ;
     RECT  2.304 55.795 10.854 55.859 ;
     RECT  20.484 55.553 20.538 55.859 ;
     RECT  15.915 55.757 19.386 56.219 ;
     RECT  14.832 55.757 15.066 56.227 ;
     RECT  14.724 56.227 15.066 56.255 ;
     RECT  11.772 56.101 11.79 56.291 ;
     RECT  0.216 56.107 0.234 56.333 ;
     RECT  17.1 56.219 19.386 56.395 ;
     RECT  20.484 55.859 20.502 56.395 ;
     RECT  14.724 56.255 14.742 56.399 ;
     RECT  15.915 56.219 16.362 56.489 ;
     RECT  2.304 55.859 10.797 56.605 ;
     RECT  2.268 56.605 10.797 56.641 ;
     RECT  17.1 56.395 20.502 56.867 ;
     RECT  17.1 56.867 19.422 56.909 ;
     RECT  2.268 56.641 10.854 56.939 ;
     RECT  20.16 56.867 20.502 56.939 ;
     RECT  15.915 56.489 16.254 57.019 ;
     RECT  20.232 56.939 20.502 57.073 ;
     RECT  13.215 55.175 13.497 57.307 ;
     RECT  13.215 57.307 14.022 57.407 ;
     RECT  15.516 57.019 16.254 57.451 ;
     RECT  17.1 56.909 19.17 57.451 ;
     RECT  15.264 57.451 16.254 57.569 ;
     RECT  15.516 57.569 16.254 57.883 ;
     RECT  16.992 57.451 19.17 57.883 ;
     RECT  20.232 57.073 20.538 57.883 ;
     RECT  15.516 57.883 19.17 57.919 ;
     RECT  15.516 57.919 19.422 57.931 ;
     RECT  20.232 57.883 20.574 57.931 ;
     RECT  15.516 57.931 20.574 58.019 ;
     RECT  13.215 57.407 13.806 58.109 ;
     RECT  15.516 58.019 19.422 58.109 ;
     RECT  0.54 57.991 0.558 58.117 ;
     RECT  2.268 56.939 10.797 58.117 ;
     RECT  20.448 58.019 20.574 58.205 ;
     RECT  2.232 58.117 10.797 58.217 ;
     RECT  0.144 58.117 0.558 58.445 ;
     RECT  2.268 58.217 10.797 58.487 ;
     RECT  20.448 58.205 20.538 58.589 ;
     RECT  12.204 58.495 12.222 58.721 ;
     RECT  0.144 58.445 0.162 58.733 ;
     RECT  21.42 54.401 21.438 58.795 ;
     RECT  2.304 58.487 10.797 58.891 ;
     RECT  15.804 58.109 19.422 58.891 ;
     RECT  21.384 58.795 21.438 58.991 ;
     RECT  14.832 58.351 14.886 59.071 ;
     RECT  2.304 58.891 10.854 59.189 ;
     RECT  14.472 59.071 14.886 59.189 ;
     RECT  21.42 58.991 21.438 59.297 ;
     RECT  15.624 58.891 19.422 59.341 ;
     RECT  20.484 58.589 20.538 59.458 ;
     RECT  2.304 59.189 10.797 59.459 ;
     RECT  15.084 59.341 19.422 59.467 ;
     RECT  20.448 59.458 20.538 59.467 ;
     RECT  13.215 58.109 13.497 59.611 ;
     RECT  13.215 59.611 13.878 60.007 ;
     RECT  15.084 59.467 20.538 60.179 ;
     RECT  2.304 59.459 3.402 60.241 ;
     RECT  4.14 59.459 10.797 60.241 ;
     RECT  13.215 60.007 13.914 60.269 ;
     RECT  15.084 60.179 16.398 60.269 ;
     RECT  17.712 60.179 20.538 60.509 ;
     RECT  15.084 60.269 16.197 60.611 ;
     RECT  17.712 60.509 19.098 60.925 ;
     RECT  14.832 60.691 14.886 60.989 ;
     RECT  2.304 60.241 10.797 61.051 ;
     RECT  15.732 60.611 16.197 61.051 ;
     RECT  17.064 60.925 19.098 61.051 ;
     RECT  2.304 61.051 10.818 61.087 ;
     RECT  2.304 61.087 10.926 61.187 ;
     RECT  15.732 61.051 19.098 61.187 ;
     RECT  2.304 61.187 10.89 61.373 ;
     RECT  15.768 61.187 19.098 61.429 ;
     RECT  19.908 60.509 20.538 61.429 ;
     RECT  10.188 61.373 10.89 61.457 ;
     RECT  10.224 61.457 10.89 61.493 ;
     RECT  14.868 60.989 14.886 61.529 ;
     RECT  10.224 61.493 10.797 61.763 ;
     RECT  21.42 61.483 21.438 61.771 ;
     RECT  21.384 61.771 21.438 61.949 ;
     RECT  0.216 61.867 0.234 61.997 ;
     RECT  13.215 60.269 13.497 62.275 ;
     RECT  12.528 62.275 13.497 62.311 ;
     RECT  15.768 61.429 20.538 62.339 ;
     RECT  10.296 61.763 10.797 62.401 ;
     RECT  12.456 62.311 13.497 62.401 ;
     RECT  14.832 62.275 14.85 62.429 ;
     RECT  2.304 61.373 9.45 62.437 ;
     RECT  2.268 62.437 9.45 62.581 ;
     RECT  10.296 62.401 10.926 62.581 ;
     RECT  15.768 62.339 20.502 62.581 ;
     RECT  2.268 62.581 10.926 62.669 ;
     RECT  21.42 61.949 21.438 62.669 ;
     RECT  12.42 62.401 13.497 62.671 ;
     RECT  12.312 62.671 13.497 62.807 ;
     RECT  12.564 62.807 13.497 62.969 ;
     RECT  2.304 62.669 10.926 63.239 ;
     RECT  13.215 62.969 13.497 63.283 ;
     RECT  15.408 62.581 20.502 63.319 ;
     RECT  13.215 63.283 13.806 63.509 ;
     RECT  15.408 63.319 20.538 63.509 ;
     RECT  0.216 62.875 0.234 63.595 ;
     RECT  0.216 63.595 0.306 63.787 ;
     RECT  0.036 63.787 0.306 63.815 ;
     RECT  0.036 63.815 0.234 63.821 ;
     RECT  0.036 63.821 0.054 63.824 ;
     RECT  15.732 63.509 20.538 63.965 ;
     RECT  12.168 63.589 12.186 64.049 ;
     RECT  13.215 63.509 13.698 64.319 ;
     RECT  15.732 63.965 19.422 64.327 ;
     RECT  15.516 64.327 19.422 64.391 ;
     RECT  13.215 64.319 13.497 64.435 ;
     RECT  12.96 64.435 13.497 64.471 ;
     RECT  11.988 64.399 12.006 64.561 ;
     RECT  11.916 64.561 12.006 64.589 ;
     RECT  12.888 64.471 13.497 64.589 ;
     RECT  11.916 64.589 11.934 64.661 ;
     RECT  21.42 64.411 21.438 64.697 ;
     RECT  20.16 63.965 20.538 64.733 ;
     RECT  20.16 64.733 20.502 64.741 ;
     RECT  11.592 64.669 11.61 64.769 ;
     RECT  15.516 64.391 19.098 64.859 ;
     RECT  0.18 64.867 0.198 64.903 ;
     RECT  15.516 64.859 19.026 65.101 ;
     RECT  0.144 64.903 0.198 65.117 ;
     RECT  13.104 64.589 13.497 65.129 ;
     RECT  2.304 63.239 10.797 65.201 ;
     RECT  0.18 65.117 0.198 65.213 ;
     RECT  19.944 64.741 20.502 65.467 ;
     RECT  2.304 65.201 9.63 65.543 ;
     RECT  10.515 65.201 10.797 65.551 ;
     RECT  14.868 65.101 19.026 65.677 ;
     RECT  0.216 65.323 0.234 65.693 ;
     RECT  19.908 65.467 20.502 65.707 ;
     RECT  2.304 65.543 9.342 65.851 ;
     RECT  19.872 65.707 20.502 65.851 ;
     RECT  2.268 65.851 9.342 65.975 ;
     RECT  10.515 65.551 10.926 66.019 ;
     RECT  14.832 65.677 19.026 66.047 ;
     RECT  10.515 66.019 10.998 66.077 ;
     RECT  15.552 66.047 19.026 66.083 ;
     RECT  10.515 66.077 10.926 66.119 ;
     RECT  15.552 66.083 16.29 66.119 ;
     RECT  19.872 65.851 20.538 66.235 ;
     RECT  2.304 65.975 9.342 66.331 ;
     RECT  17.1 66.083 19.026 66.361 ;
     RECT  15.915 66.119 16.29 66.479 ;
     RECT  2.304 66.331 9.45 66.551 ;
     RECT  12.348 66.523 12.366 66.631 ;
     RECT  19.872 66.235 20.574 66.715 ;
     RECT  12.276 66.631 12.366 66.749 ;
     RECT  17.1 66.361 19.098 66.901 ;
     RECT  2.304 66.551 9.126 67.003 ;
     RECT  2.232 67.003 9.126 67.127 ;
     RECT  19.836 66.715 20.574 67.127 ;
     RECT  19.836 67.127 20.538 67.133 ;
     RECT  12.384 66.901 12.402 67.171 ;
     RECT  13.215 65.129 13.497 67.171 ;
     RECT  19.836 67.133 20.502 67.289 ;
     RECT  12.384 67.171 13.497 67.361 ;
     RECT  15.915 66.479 16.254 67.405 ;
     RECT  17.064 66.901 19.098 67.405 ;
     RECT  2.268 67.127 9.126 67.517 ;
     RECT  21.42 66.859 21.438 67.639 ;
     RECT  14.832 67.027 14.85 67.667 ;
     RECT  2.304 67.517 9.126 67.711 ;
     RECT  15.915 67.405 19.098 67.711 ;
     RECT  2.304 67.711 9.162 67.801 ;
     RECT  15.516 67.711 19.098 67.829 ;
     RECT  2.304 67.801 9.378 67.949 ;
     RECT  15.915 67.829 19.098 67.981 ;
     RECT  19.836 67.289 20.25 67.981 ;
     RECT  15.915 67.981 20.25 68.011 ;
     RECT  10.515 66.119 10.797 68.071 ;
     RECT  2.304 67.949 8.154 68.135 ;
     RECT  10.26 68.071 10.797 68.143 ;
     RECT  12.636 67.361 13.497 68.179 ;
     RECT  11.952 68.179 13.497 68.369 ;
     RECT  10.116 68.143 10.797 68.405 ;
     RECT  9.108 67.949 9.378 68.413 ;
     RECT  21.384 67.639 21.438 68.429 ;
     RECT  0.216 68.011 0.234 68.635 ;
     RECT  9.108 68.413 9.774 68.639 ;
     RECT  14.832 68.521 14.85 68.711 ;
     RECT  9.108 68.639 9.666 68.719 ;
     RECT  0.036 68.635 0.234 68.747 ;
     RECT  8.964 68.719 9.666 68.755 ;
     RECT  10.515 68.405 10.797 68.755 ;
     RECT  0.144 68.747 0.234 68.765 ;
     RECT  2.304 68.135 8.097 68.779 ;
     RECT  15.915 68.011 20.502 68.819 ;
     RECT  10.515 68.755 10.962 68.881 ;
     RECT  0.144 68.765 0.162 69.053 ;
     RECT  1.728 68.779 8.097 69.061 ;
     RECT  8.82 68.755 9.666 69.061 ;
     RECT  15.915 68.819 19.422 69.061 ;
     RECT  15.624 69.061 19.422 69.179 ;
     RECT  1.728 69.061 9.666 69.287 ;
     RECT  11.88 68.521 11.898 69.421 ;
     RECT  12.636 68.369 13.497 69.421 ;
     RECT  1.728 69.287 9.594 69.485 ;
     RECT  20.376 68.819 20.502 69.691 ;
     RECT  0.216 69.691 0.234 69.787 ;
     RECT  15.732 69.179 19.422 69.787 ;
     RECT  20.34 69.691 20.502 69.787 ;
     RECT  0.036 69.787 0.234 69.899 ;
     RECT  15.732 69.787 20.502 69.899 ;
     RECT  0.144 69.899 0.234 69.917 ;
     RECT  1.728 69.485 9.45 69.931 ;
     RECT  10.515 68.881 11.034 70.069 ;
     RECT  11.88 69.421 13.497 70.069 ;
     RECT  10.515 70.069 13.497 70.133 ;
     RECT  1.404 69.931 9.45 70.169 ;
     RECT  15.732 69.899 20.466 70.259 ;
     RECT  21.42 68.429 21.438 70.267 ;
     RECT  8.928 70.169 9.45 70.295 ;
     RECT  0.144 69.917 0.162 70.301 ;
     RECT  21.42 70.267 21.546 70.301 ;
     RECT  8.928 70.295 9.198 70.529 ;
     RECT  9.18 70.529 9.198 70.601 ;
     RECT  10.515 70.133 11.934 70.799 ;
     RECT  1.404 70.169 8.097 71.069 ;
     RECT  15.732 70.259 20.358 71.069 ;
     RECT  1.404 71.069 6.462 71.375 ;
     RECT  10.515 70.799 11.898 71.375 ;
     RECT  2.376 71.375 6.462 71.519 ;
     RECT  5.115 71.519 6.462 71.609 ;
     RECT  7.344 71.069 8.097 71.609 ;
     RECT  15.915 71.069 19.926 71.609 ;
     RECT  2.376 71.519 4.266 71.645 ;
     RECT  2.415 71.645 4.266 71.879 ;
     RECT  15.915 71.609 19.386 71.879 ;
     RECT  1.404 71.375 1.422 71.915 ;
     RECT  3.528 71.879 4.266 71.915 ;
     RECT  10.515 71.375 11.574 72.059 ;
     RECT  3.528 71.915 4.158 72.149 ;
     RECT  6.264 71.609 6.462 72.149 ;
     RECT  15.915 71.879 19.242 72.149 ;
     RECT  2.415 71.879 2.79 72.185 ;
     RECT  17.676 72.149 19.242 72.419 ;
     RECT  4.032 72.149 4.158 72.455 ;
     RECT  6.3 72.149 6.462 72.455 ;
     RECT  11.556 72.059 11.574 72.599 ;
     RECT  4.14 72.455 4.158 72.689 ;
     RECT  6.444 72.455 6.462 72.689 ;
     RECT  17.676 72.419 19.098 72.689 ;
     RECT  15.915 72.149 16.866 72.725 ;
     RECT  17.82 72.689 19.098 72.959 ;
     RECT  21.528 70.301 21.546 72.959 ;
     RECT  18.615 72.959 19.098 73.031 ;
     RECT  2.415 72.185 2.697 73.187 ;
     RECT  5.115 71.609 5.397 73.187 ;
     RECT  7.815 71.609 8.097 73.187 ;
     RECT  10.515 72.059 10.797 73.187 ;
     RECT  13.215 70.133 13.497 73.187 ;
     RECT  15.915 72.725 16.197 73.187 ;
     RECT  18.615 73.031 18.897 73.187 ;
     RECT  2.415 73.187 2.505 73.457 ;
     RECT  5.115 73.187 5.205 73.457 ;
     RECT  7.815 73.187 7.905 73.457 ;
     RECT  10.515 73.187 10.605 73.457 ;
     RECT  13.215 73.187 13.305 73.457 ;
     RECT  15.915 73.187 16.005 73.457 ;
     RECT  18.615 73.187 18.705 73.457 ;
    LAYER M4 ;
     RECT  0.025 13.056 0.108 13.32 ;
     RECT  0.108 5.424 0.133 70.2 ;
     RECT  0.133 5.424 0.173 70.296 ;
     RECT  0.173 5.52 0.209 70.296 ;
     RECT  0.209 5.664 0.569 70.296 ;
     RECT  0.569 5.904 2.408 70.296 ;
     RECT  2.408 2.148 2.512 73.452 ;
     RECT  2.512 2.418 2.704 73.182 ;
     RECT  2.704 40.272 2.729 58.728 ;
     RECT  2.704 16.32 2.765 18.84 ;
     RECT  2.729 47.04 2.765 58.728 ;
     RECT  2.704 68.928 2.765 70.296 ;
     RECT  2.765 47.04 2.801 49.56 ;
     RECT  2.765 70.272 2.801 70.296 ;
     RECT  2.704 10.656 2.837 14.232 ;
     RECT  2.729 40.272 2.837 45.672 ;
     RECT  2.765 50.592 2.837 58.728 ;
     RECT  2.704 65.184 2.837 67.896 ;
     RECT  2.765 68.928 2.837 68.952 ;
     RECT  2.837 10.656 2.873 11.928 ;
     RECT  2.704 29.76 2.873 36.888 ;
     RECT  2.704 37.968 2.873 39.24 ;
     RECT  2.873 29.76 2.909 33.144 ;
     RECT  2.837 65.184 2.945 67.272 ;
     RECT  2.704 19.92 2.981 25.08 ;
     RECT  2.873 34.128 2.981 36.888 ;
     RECT  2.704 26.064 3.017 28.776 ;
     RECT  2.873 38.688 3.017 39.24 ;
     RECT  2.801 47.424 3.017 49.56 ;
     RECT  2.981 34.896 3.125 36.888 ;
     RECT  2.837 50.592 3.125 55.896 ;
     RECT  2.945 65.184 3.125 65.688 ;
     RECT  2.765 16.32 3.197 17.688 ;
     RECT  2.837 13.056 3.233 14.232 ;
     RECT  2.909 29.76 3.251 30.168 ;
     RECT  2.909 31.344 3.269 33.144 ;
     RECT  2.945 66.672 3.292 67.272 ;
     RECT  2.704 15.264 3.305 15.288 ;
     RECT  2.704 60.96 3.377 63.816 ;
     RECT  3.125 50.64 3.395 55.896 ;
     RECT  2.704 6.816 3.413 9.624 ;
     RECT  3.292 66.672 3.413 67.224 ;
     RECT  3.413 7.056 3.449 9.624 ;
     RECT  2.837 41.664 3.683 45.672 ;
     RECT  3.683 41.664 3.701 42.648 ;
     RECT  3.197 17.616 3.733 17.688 ;
     RECT  2.765 18.816 3.733 18.84 ;
     RECT  3.449 7.632 3.809 9.624 ;
     RECT  3.413 67.056 3.809 67.224 ;
     RECT  2.981 22.752 3.841 25.08 ;
     RECT  3.017 26.064 3.841 28.44 ;
     RECT  3.701 41.664 3.877 42.168 ;
     RECT  2.837 57.072 3.877 58.728 ;
     RECT  2.704 59.808 3.877 59.88 ;
     RECT  3.733 17.616 3.884 18.84 ;
     RECT  2.981 19.92 3.884 21.672 ;
     RECT  3.125 35.424 3.913 36.888 ;
     RECT  2.873 11.136 3.925 11.928 ;
     RECT  2.837 40.272 3.925 40.392 ;
     RECT  3.877 41.424 3.925 42.168 ;
     RECT  3.683 43.92 3.925 45.672 ;
     RECT  3.836 46.656 3.925 46.872 ;
     RECT  3.269 31.92 3.949 33.144 ;
     RECT  3.925 40.272 3.949 42.168 ;
     RECT  3.877 57.072 3.973 59.88 ;
     RECT  3.377 60.96 3.973 63.288 ;
     RECT  3.197 16.32 3.985 16.488 ;
     RECT  3.809 7.632 4.025 8.472 ;
     RECT  3.233 13.056 4.025 13.464 ;
     RECT  3.877 70.032 4.025 70.056 ;
     RECT  3.395 50.832 4.057 55.896 ;
     RECT  3.973 57.072 4.057 63.288 ;
     RECT  3.925 11.136 4.097 12.024 ;
     RECT  3.985 16.224 4.097 16.488 ;
     RECT  3.125 65.184 4.117 65.448 ;
     RECT  3.949 31.92 4.124 33.624 ;
     RECT  4.124 31.92 4.165 34.2 ;
     RECT  3.913 35.424 4.165 37.608 ;
     RECT  3.884 17.616 4.453 21.672 ;
     RECT  3.841 22.752 4.453 28.44 ;
     RECT  4.453 17.616 4.489 28.44 ;
     RECT  3.251 29.76 4.489 30.072 ;
     RECT  4.489 17.616 4.741 30.072 ;
     RECT  3.017 38.688 4.741 38.712 ;
     RECT  3.949 39.84 4.741 42.168 ;
     RECT  3.809 9.6 4.813 9.624 ;
     RECT  3.925 43.92 4.813 46.872 ;
     RECT  3.017 47.904 4.813 49.56 ;
     RECT  4.165 31.92 4.885 37.608 ;
     RECT  4.057 50.832 4.885 63.288 ;
     RECT  4.117 64.56 4.885 65.448 ;
     RECT  3.809 67.2 4.885 67.224 ;
     RECT  4.201 11.04 4.957 11.064 ;
     RECT  4.741 17.616 4.981 30.456 ;
     RECT  4.885 31.776 4.981 37.608 ;
     RECT  4.885 50.832 4.993 67.224 ;
     RECT  4.025 7.824 5.065 8.472 ;
     RECT  4.525 5.472 5.108 5.496 ;
     RECT  5.065 6.864 5.108 8.472 ;
     RECT  4.813 9.6 5.108 9.816 ;
     RECT  4.957 10.992 5.108 11.064 ;
     RECT  4.345 12.576 5.108 12.6 ;
     RECT  4.097 16.224 5.108 16.44 ;
     RECT  4.981 17.616 5.108 37.608 ;
     RECT  4.741 38.688 5.108 42.168 ;
     RECT  4.813 43.92 5.108 49.56 ;
     RECT  4.993 50.832 5.108 67.848 ;
     RECT  5.108 2.148 5.212 73.452 ;
     RECT  5.212 2.418 5.404 73.182 ;
     RECT  5.404 8.256 5.645 8.28 ;
     RECT  5.404 9.6 5.651 12.6 ;
     RECT  5.404 58.704 5.897 68.376 ;
     RECT  5.651 10.032 6.005 12.6 ;
     RECT  5.404 5.472 6.365 6.792 ;
     RECT  6.005 10.032 6.365 12.264 ;
     RECT  5.404 43.92 6.433 48.216 ;
     RECT  5.897 66.912 6.437 68.376 ;
     RECT  5.404 49.488 6.469 49.512 ;
     RECT  5.404 50.832 6.469 57.48 ;
     RECT  6.365 5.856 6.473 6.792 ;
     RECT  5.897 58.704 6.541 65.688 ;
     RECT  6.433 43.92 6.565 48.264 ;
     RECT  6.469 49.488 6.565 57.48 ;
     RECT  6.565 43.92 6.785 57.48 ;
     RECT  6.785 43.584 6.793 57.48 ;
     RECT  6.541 58.656 6.793 65.688 ;
     RECT  6.793 43.296 6.937 65.688 ;
     RECT  5.404 15.456 7.009 42.072 ;
     RECT  6.437 67.92 7.153 68.376 ;
     RECT  6.365 10.944 7.225 12.264 ;
     RECT  7.009 14.928 7.429 42.072 ;
     RECT  6.937 43.104 7.429 65.688 ;
     RECT  6.613 8.448 7.441 8.472 ;
     RECT  7.429 14.928 7.441 65.688 ;
     RECT  7.441 14.928 7.477 65.736 ;
     RECT  7.441 8.448 7.513 8.52 ;
     RECT  7.477 14.16 7.549 65.736 ;
     RECT  6.437 66.912 7.549 66.936 ;
     RECT  7.225 10.944 7.657 12.312 ;
     RECT  6.473 5.856 7.808 6.168 ;
     RECT  7.513 8.448 7.808 8.568 ;
     RECT  7.765 9.792 7.808 9.816 ;
     RECT  7.657 10.944 7.808 13.176 ;
     RECT  7.549 14.16 7.808 66.936 ;
     RECT  7.153 67.92 7.808 68.76 ;
     RECT  7.153 70.272 7.808 70.296 ;
     RECT  7.808 2.148 7.912 73.452 ;
     RECT  7.912 2.418 8.104 73.182 ;
     RECT  8.104 5.856 8.165 6.408 ;
     RECT  8.104 7.776 8.819 9.672 ;
     RECT  8.104 10.704 8.849 68.376 ;
     RECT  8.819 7.776 8.86 8.856 ;
     RECT  8.104 69.456 8.867 69.48 ;
     RECT  8.849 10.704 8.885 63.528 ;
     RECT  8.86 8.544 8.957 8.856 ;
     RECT  8.957 8.592 9.029 8.856 ;
     RECT  8.849 64.512 9.029 68.376 ;
     RECT  8.885 15.216 9.101 42.648 ;
     RECT  9.101 15.216 9.137 21.48 ;
     RECT  8.885 43.632 9.137 63.528 ;
     RECT  9.029 67.728 9.173 68.376 ;
     RECT  8.885 10.704 9.209 14.232 ;
     RECT  9.029 64.512 9.209 66.36 ;
     RECT  9.173 67.92 9.245 68.376 ;
     RECT  9.101 22.512 9.281 42.552 ;
     RECT  9.137 47.856 9.281 63.528 ;
     RECT  9.245 67.92 9.281 67.944 ;
     RECT  8.165 6.288 9.353 6.408 ;
     RECT  9.209 10.704 9.353 13.608 ;
     RECT  9.281 22.512 9.353 26.808 ;
     RECT  9.281 27.84 9.353 34.536 ;
     RECT  9.209 64.608 9.353 66.36 ;
     RECT  9.281 47.856 9.389 49.512 ;
     RECT  9.353 66.336 9.461 66.36 ;
     RECT  9.353 10.704 9.673 12.6 ;
     RECT  9.281 40.56 10.141 42.552 ;
     RECT  9.137 43.632 10.141 46.632 ;
     RECT  9.281 35.952 10.465 39.576 ;
     RECT  10.141 40.56 10.465 46.632 ;
     RECT  9.685 5.712 10.508 5.736 ;
     RECT  9.673 10.32 10.508 12.6 ;
     RECT  9.137 15.264 10.508 21.48 ;
     RECT  9.353 22.608 10.508 26.808 ;
     RECT  9.353 27.84 10.508 34.488 ;
     RECT  10.465 35.952 10.508 46.632 ;
     RECT  9.389 47.856 10.508 48.264 ;
     RECT  9.389 49.248 10.508 49.512 ;
     RECT  9.281 50.544 10.508 60.072 ;
     RECT  9.281 61.2 10.508 63.528 ;
     RECT  9.353 64.608 10.508 64.968 ;
     RECT  10.508 2.148 10.612 73.452 ;
     RECT  10.612 2.418 10.804 73.182 ;
     RECT  10.804 23.664 10.829 24.456 ;
     RECT  10.804 43.584 10.829 44.616 ;
     RECT  10.804 35.952 10.865 39.576 ;
     RECT  10.804 41.616 10.865 42.072 ;
     RECT  10.804 51.888 10.865 52.44 ;
     RECT  10.804 45.792 10.901 45.96 ;
     RECT  10.804 25.824 10.937 26.28 ;
     RECT  10.804 62.16 10.937 62.568 ;
     RECT  10.865 41.712 10.973 42.072 ;
     RECT  10.804 66.048 11.009 66.072 ;
     RECT  10.865 37.968 11.045 39.576 ;
     RECT  10.804 20.4 11.081 21.48 ;
     RECT  10.804 27.888 11.869 27.912 ;
     RECT  10.937 26.256 12.229 26.28 ;
     RECT  11.869 27.84 12.229 27.912 ;
     RECT  10.804 31.392 12.428 32.472 ;
     RECT  10.804 34.08 12.428 34.488 ;
     RECT  10.865 35.952 12.469 36.888 ;
     RECT  10.804 11.952 13.208 12.216 ;
     RECT  10.804 15.168 13.208 17.64 ;
     RECT  11.081 20.592 13.208 21.48 ;
     RECT  10.829 23.712 13.208 24.456 ;
     RECT  12.229 26.256 13.208 27.912 ;
     RECT  10.804 29.232 13.208 29.592 ;
     RECT  12.428 31.392 13.208 34.488 ;
     RECT  12.469 35.808 13.208 36.888 ;
     RECT  11.045 38.4 13.208 39.576 ;
     RECT  10.973 41.712 13.208 41.976 ;
     RECT  10.829 44.064 13.208 44.616 ;
     RECT  10.901 45.792 13.208 45.816 ;
     RECT  10.804 48.192 13.208 48.216 ;
     RECT  10.804 49.488 13.208 49.512 ;
     RECT  10.865 51.984 13.208 52.296 ;
     RECT  10.804 55.68 13.208 55.752 ;
     RECT  10.804 57.024 13.208 57.576 ;
     RECT  10.937 62.16 13.208 62.52 ;
     RECT  10.804 64.608 13.208 64.872 ;
     RECT  13.208 2.148 13.312 73.452 ;
     RECT  13.312 2.418 13.504 73.182 ;
     RECT  13.504 33.552 13.961 34.488 ;
     RECT  13.504 29.232 14.537 29.592 ;
     RECT  13.504 44.064 14.821 44.616 ;
     RECT  13.504 23.808 14.861 24.456 ;
     RECT  14.861 23.808 15.649 23.928 ;
     RECT  13.504 48.192 15.649 48.216 ;
     RECT  13.504 12.192 15.908 12.216 ;
     RECT  13.504 15.168 15.908 17.64 ;
     RECT  13.504 20.592 15.908 21.48 ;
     RECT  15.649 23.28 15.908 23.928 ;
     RECT  13.504 26.256 15.908 26.28 ;
     RECT  13.504 27.888 15.908 27.912 ;
     RECT  14.537 29.232 15.908 29.256 ;
     RECT  13.504 31.392 15.908 32.328 ;
     RECT  13.961 34.08 15.908 34.488 ;
     RECT  13.504 35.952 15.908 36.888 ;
     RECT  13.504 38.4 15.908 39.576 ;
     RECT  13.504 41.712 15.908 41.976 ;
     RECT  14.821 44.064 15.908 44.712 ;
     RECT  13.504 45.792 15.908 45.816 ;
     RECT  15.649 47.328 15.908 48.216 ;
     RECT  13.504 49.488 15.908 49.512 ;
     RECT  13.504 51.984 15.908 52.296 ;
     RECT  15.649 54.096 15.908 54.12 ;
     RECT  13.504 55.68 15.908 55.752 ;
     RECT  13.504 57.024 15.908 57.576 ;
     RECT  13.504 62.16 15.908 62.52 ;
     RECT  13.504 64.608 15.908 64.632 ;
     RECT  15.908 2.148 16.012 73.452 ;
     RECT  16.012 2.418 16.204 73.182 ;
     RECT  16.204 26.256 16.301 27.192 ;
     RECT  16.204 62.16 16.373 62.52 ;
     RECT  16.204 53.856 16.625 55.704 ;
     RECT  16.204 35.856 16.697 36.552 ;
     RECT  16.204 21.456 16.841 21.48 ;
     RECT  16.204 22.752 17.057 24.408 ;
     RECT  16.204 44.208 17.093 44.712 ;
     RECT  16.204 31.44 17.197 34.44 ;
     RECT  16.204 42 17.197 42.744 ;
     RECT  17.197 41.904 17.341 42.744 ;
     RECT  16.204 49.44 17.341 51.912 ;
     RECT  16.204 37.632 17.377 38.76 ;
     RECT  16.204 12.384 17.413 12.408 ;
     RECT  17.341 49.44 17.449 51.96 ;
     RECT  17.197 31.44 17.453 34.872 ;
     RECT  17.377 7.68 17.485 7.704 ;
     RECT  17.057 24.384 17.485 24.408 ;
     RECT  17.093 44.688 17.485 44.712 ;
     RECT  16.204 46.224 17.485 47.352 ;
     RECT  16.204 58.512 17.485 58.824 ;
     RECT  17.453 31.44 17.489 31.608 ;
     RECT  17.485 44.688 17.489 47.352 ;
     RECT  16.204 28.944 17.521 30.072 ;
     RECT  17.485 7.632 17.557 7.704 ;
     RECT  17.413 12.384 17.557 12.552 ;
     RECT  17.233 14.16 17.557 14.184 ;
     RECT  16.204 15.264 17.557 15.288 ;
     RECT  16.625 55.248 17.557 55.704 ;
     RECT  16.204 64.32 17.557 64.872 ;
     RECT  17.557 55.248 17.561 56.52 ;
     RECT  17.557 12.384 17.593 12.888 ;
     RECT  17.521 28.8 17.593 30.072 ;
     RECT  17.489 31.44 17.593 31.56 ;
     RECT  16.373 62.16 17.593 62.184 ;
     RECT  17.377 37.632 17.629 39.192 ;
     RECT  17.593 61.92 17.629 62.184 ;
     RECT  17.557 63.36 17.629 64.872 ;
     RECT  16.625 53.856 17.665 54.12 ;
     RECT  17.561 55.248 17.665 55.272 ;
     RECT  16.301 26.496 17.701 27.192 ;
     RECT  17.701 26.016 17.773 27.192 ;
     RECT  17.341 41.664 17.845 42.744 ;
     RECT  17.485 58.512 17.845 59.064 ;
     RECT  16.204 48.336 17.881 48.36 ;
     RECT  17.449 49.392 17.881 51.96 ;
     RECT  17.485 24.384 17.917 24.456 ;
     RECT  17.881 48.336 17.989 51.96 ;
     RECT  17.057 22.752 18.025 23.304 ;
     RECT  17.917 24.384 18.025 24.744 ;
     RECT  17.845 41.664 18.025 42.792 ;
     RECT  17.989 48.336 18.025 52.488 ;
     RECT  18.025 48.336 18.097 52.776 ;
     RECT  17.489 45.552 18.169 47.352 ;
     RECT  18.097 48.336 18.169 52.824 ;
     RECT  17.453 32.592 18.241 34.872 ;
     RECT  16.697 36.048 18.241 36.552 ;
     RECT  17.629 66.864 18.241 66.888 ;
     RECT  17.557 7.632 18.349 7.752 ;
     RECT  17.557 14.16 18.349 15.288 ;
     RECT  16.204 16.56 18.349 17.64 ;
     RECT  17.773 26.016 18.349 27.72 ;
     RECT  17.593 28.8 18.349 31.56 ;
     RECT  18.349 6.768 18.385 7.752 ;
     RECT  18.385 6.768 18.608 8.472 ;
     RECT  17.593 10.08 18.608 10.104 ;
     RECT  17.593 12 18.608 12.888 ;
     RECT  18.349 14.16 18.608 17.64 ;
     RECT  16.204 18.72 18.608 19.608 ;
     RECT  18.025 22.752 18.608 24.744 ;
     RECT  18.349 26.016 18.608 31.56 ;
     RECT  18.241 32.592 18.608 36.552 ;
     RECT  17.629 37.632 18.608 39.24 ;
     RECT  17.989 40.416 18.608 40.44 ;
     RECT  18.025 41.664 18.608 43.368 ;
     RECT  18.097 44.352 18.608 44.376 ;
     RECT  18.169 45.552 18.608 52.824 ;
     RECT  17.665 53.856 18.608 55.272 ;
     RECT  17.561 56.256 18.608 56.52 ;
     RECT  17.845 58.512 18.608 60.024 ;
     RECT  17.629 61.92 18.608 64.872 ;
     RECT  18.241 66.864 18.608 67.368 ;
     RECT  18.608 2.148 18.712 73.452 ;
     RECT  18.712 2.418 18.904 73.182 ;
     RECT  18.904 18.048 19.109 23.928 ;
     RECT  18.904 44.64 19.109 57.576 ;
     RECT  18.904 24.96 19.181 27.72 ;
     RECT  19.109 50.64 19.181 57.576 ;
     RECT  18.904 31.152 19.217 43.368 ;
     RECT  18.904 5.52 19.897 10.392 ;
     RECT  18.904 11.52 19.897 13.32 ;
     RECT  18.904 14.736 19.897 16.92 ;
     RECT  19.181 26.544 19.897 27.72 ;
     RECT  19.181 52.656 19.897 57.576 ;
     RECT  18.904 61.872 19.897 68.184 ;
     RECT  18.904 69.168 19.897 70.104 ;
     RECT  19.897 26.544 19.933 28.152 ;
     RECT  18.904 29.184 19.933 30.072 ;
     RECT  19.109 44.64 19.933 49.512 ;
     RECT  19.109 20.832 20.149 23.928 ;
     RECT  19.181 24.96 20.149 25.464 ;
     RECT  19.933 44.352 20.149 49.512 ;
     RECT  19.181 50.64 20.149 51.672 ;
     RECT  19.897 5.52 20.221 13.32 ;
     RECT  19.897 14.352 20.221 16.92 ;
     RECT  19.217 31.584 20.221 43.368 ;
     RECT  20.149 44.352 20.221 51.672 ;
     RECT  19.933 26.544 20.401 30.072 ;
     RECT  20.221 5.52 20.437 16.92 ;
     RECT  19.109 18.048 20.437 19.848 ;
     RECT  20.149 20.832 20.437 25.464 ;
     RECT  20.401 26.544 20.437 30.456 ;
     RECT  20.221 31.584 20.437 51.672 ;
     RECT  19.897 52.656 20.437 57.96 ;
     RECT  18.904 58.944 20.437 60.888 ;
     RECT  19.897 61.872 20.437 70.104 ;
     RECT  20.437 5.52 20.473 19.848 ;
     RECT  20.437 20.832 20.473 51.672 ;
     RECT  20.437 52.656 20.473 70.104 ;
     RECT  20.473 5.52 21.409 70.104 ;
     RECT  21.409 5.424 21.516 70.296 ;
     RECT  21.516 70.272 21.557 70.296 ;
    LAYER M5 ;
     RECT  2.4 2.137 2.52 2.151 ;
     RECT  5.1 2.137 5.22 2.151 ;
     RECT  7.8 2.137 7.92 2.151 ;
     RECT  9.696 2.137 10.62 2.151 ;
     RECT  13.2 2.137 13.32 2.151 ;
     RECT  15.9 2.137 16.02 2.151 ;
     RECT  18.6 2.137 18.72 2.151 ;
     RECT  9.696 2.151 10.812 5.747 ;
     RECT  2.4 2.151 2.712 6.805 ;
     RECT  2.4 6.805 3.336 7.667 ;
     RECT  7.8 2.151 8.112 7.765 ;
     RECT  5.1 2.151 5.412 9.589 ;
     RECT  7.8 7.765 8.808 10.933 ;
     RECT  5.1 9.589 5.64 12.563 ;
     RECT  3.936 11.365 3.96 13.091 ;
     RECT  10.5 5.747 10.812 17.029 ;
     RECT  10.5 17.029 10.92 17.219 ;
     RECT  3.936 18.229 3.96 19.237 ;
     RECT  5.1 12.563 5.412 19.237 ;
     RECT  3.936 19.237 5.412 19.285 ;
     RECT  3.936 19.285 6.264 19.619 ;
     RECT  4.224 19.619 6.264 20.003 ;
     RECT  4.224 20.003 5.412 20.099 ;
     RECT  2.4 7.667 2.712 21.637 ;
     RECT  2.4 21.637 3.528 22.309 ;
     RECT  5.1 20.099 5.412 22.309 ;
     RECT  6.672 22.597 6.696 22.741 ;
     RECT  7.8 10.933 8.856 22.741 ;
     RECT  2.4 22.309 5.412 22.835 ;
     RECT  6.672 22.741 8.856 22.835 ;
     RECT  2.4 22.835 3.96 22.883 ;
     RECT  6.672 22.835 8.808 23.317 ;
     RECT  6.432 23.317 8.808 23.699 ;
     RECT  13.2 2.151 13.512 23.797 ;
     RECT  3.936 22.883 3.96 24.131 ;
     RECT  6.432 23.699 8.664 25.715 ;
     RECT  5.1 22.835 5.412 26.053 ;
     RECT  4.752 26.053 5.412 26.197 ;
     RECT  3.792 26.197 5.412 26.629 ;
     RECT  6.432 25.715 6.456 26.629 ;
     RECT  3.792 26.629 6.456 27.299 ;
     RECT  7.8 25.715 8.664 27.301 ;
     RECT  7.8 27.301 9.096 27.829 ;
     RECT  12.384 23.797 13.512 27.875 ;
     RECT  7.68 27.829 9.096 28.787 ;
     RECT  7.68 28.787 8.664 29.123 ;
     RECT  4.608 27.299 6.456 29.363 ;
     RECT  2.4 22.883 2.712 30.133 ;
     RECT  4.992 29.363 6.456 31.381 ;
     RECT  7.8 29.123 8.664 31.381 ;
     RECT  4.992 31.381 8.76 31.523 ;
     RECT  2.4 30.133 3.24 31.909 ;
     RECT  4.992 31.523 8.112 31.955 ;
     RECT  4.992 31.955 5.412 32.003 ;
     RECT  2.4 31.909 3.528 32.531 ;
     RECT  5.1 32.003 5.412 34.165 ;
     RECT  4.176 34.165 5.412 34.931 ;
     RECT  12.48 27.875 13.512 36.275 ;
     RECT  5.1 34.931 5.412 36.373 ;
     RECT  6.432 31.955 8.112 36.373 ;
     RECT  3.696 35.605 3.72 36.611 ;
     RECT  0.24 1.285 0.264 36.899 ;
     RECT  5.1 36.373 8.112 37.043 ;
     RECT  5.1 37.043 6.6 37.091 ;
     RECT  7.8 37.043 8.112 37.573 ;
     RECT  6.576 37.091 6.6 38.005 ;
     RECT  7.8 37.573 8.808 38.005 ;
     RECT  5.1 37.091 5.412 38.149 ;
     RECT  6.576 38.005 8.808 38.149 ;
     RECT  5.1 38.149 8.808 38.531 ;
     RECT  5.1 38.531 8.112 40.163 ;
     RECT  2.4 32.531 2.712 40.261 ;
     RECT  3.936 38.677 3.96 40.261 ;
     RECT  2.4 40.261 3.96 40.595 ;
     RECT  6.48 40.163 8.112 41.075 ;
     RECT  2.4 40.595 3.432 42.323 ;
     RECT  6.48 41.075 6.504 42.997 ;
     RECT  7.488 41.075 8.112 42.997 ;
     RECT  2.4 42.323 2.712 43.285 ;
     RECT  2.4 43.285 3.672 43.955 ;
     RECT  3.888 44.341 3.912 44.965 ;
     RECT  5.1 40.163 5.412 44.965 ;
     RECT  6.48 42.997 8.112 44.965 ;
     RECT  3.888 44.965 3.96 45.203 ;
     RECT  5.1 44.965 8.112 45.635 ;
     RECT  3.936 45.203 3.96 45.731 ;
     RECT  5.1 45.635 6.504 46.597 ;
     RECT  5.1 46.597 6.6 46.643 ;
     RECT  3.888 46.645 3.912 46.835 ;
     RECT  7.8 45.635 8.112 47.269 ;
     RECT  7.68 47.269 8.112 48.179 ;
     RECT  2.4 43.955 2.712 48.373 ;
     RECT  2.4 48.373 2.856 48.947 ;
     RECT  7.8 48.179 8.112 49.189 ;
     RECT  9.216 43.861 9.24 49.189 ;
     RECT  7.8 49.189 9.24 49.235 ;
     RECT  6.48 46.643 6.6 50.243 ;
     RECT  7.8 49.235 9.096 50.293 ;
     RECT  2.4 48.947 2.712 50.629 ;
     RECT  6.816 50.293 9.096 50.771 ;
     RECT  7.8 50.771 9.096 51.925 ;
     RECT  7.632 51.925 9.096 52.213 ;
     RECT  6.816 52.213 9.096 52.357 ;
     RECT  2.4 50.629 3.384 52.547 ;
     RECT  6.432 52.357 9.096 52.547 ;
     RECT  5.1 46.643 5.412 52.789 ;
     RECT  6.816 52.547 9.096 53.075 ;
     RECT  2.4 52.547 3.288 53.123 ;
     RECT  2.4 53.123 3.192 54.179 ;
     RECT  5.1 52.789 5.544 54.901 ;
     RECT  5.1 54.901 6.216 55.141 ;
     RECT  7.632 53.075 9.096 55.141 ;
     RECT  5.1 55.141 9.096 55.189 ;
     RECT  4.512 55.189 9.096 56.051 ;
     RECT  5.1 56.051 9.096 57.061 ;
     RECT  4.224 57.061 9.096 58.115 ;
     RECT  5.1 58.115 9.096 58.645 ;
     RECT  5.1 58.645 9.192 58.739 ;
     RECT  5.1 58.739 6.216 59.027 ;
     RECT  7.632 58.739 9.192 59.699 ;
     RECT  3.984 59.029 4.008 60.419 ;
     RECT  5.1 59.027 5.412 61.045 ;
     RECT  5.1 61.045 6.264 61.619 ;
     RECT  7.632 59.699 9.096 62.197 ;
     RECT  6.816 62.197 9.096 62.387 ;
     RECT  6.816 62.387 8.112 62.915 ;
     RECT  5.1 61.619 5.784 63.253 ;
     RECT  4.128 63.253 5.784 63.875 ;
     RECT  4.128 63.875 5.412 64.981 ;
     RECT  4.128 64.981 5.544 65.459 ;
     RECT  7.8 62.915 8.112 65.509 ;
     RECT  2.4 54.179 2.712 66.661 ;
     RECT  2.4 66.661 3.24 67.283 ;
     RECT  5.1 65.459 5.544 67.715 ;
     RECT  7.8 65.509 8.856 69.491 ;
     RECT  2.4 67.283 2.712 73.449 ;
     RECT  5.1 67.715 5.412 73.449 ;
     RECT  7.8 69.491 8.112 73.449 ;
     RECT  10.5 17.219 10.812 73.449 ;
     RECT  13.2 36.275 13.512 73.449 ;
     RECT  15.9 2.151 16.212 73.449 ;
     RECT  18.6 2.151 18.912 73.449 ;
     RECT  2.4 73.449 2.52 73.463 ;
     RECT  5.1 73.449 5.22 73.463 ;
     RECT  7.8 73.449 7.92 73.463 ;
     RECT  10.5 73.449 10.62 73.463 ;
     RECT  13.2 73.449 13.32 73.463 ;
     RECT  15.9 73.449 16.02 73.463 ;
     RECT  18.6 73.449 18.72 73.463 ;
     RECT  2.712 11.365 3.936 13.091 ;
     RECT  3.96 11.365 5.1 13.091 ;
     RECT  2.712 18.229 3.936 19.619 ;
     RECT  3.96 18.229 5.1 19.237 ;
     RECT  2.712 19.619 4.224 20.099 ;
     RECT  5.412 22.597 6.672 23.317 ;
     RECT  6.696 22.597 7.8 22.741 ;
     RECT  3.96 22.835 5.1 24.131 ;
     RECT  2.712 22.883 3.936 24.131 ;
     RECT  5.412 23.317 6.432 26.629 ;
     RECT  6.456 25.715 7.8 27.829 ;
     RECT  2.712 26.197 3.792 27.299 ;
     RECT  9.096 27.301 10.5 28.787 ;
     RECT  6.456 27.829 7.68 29.123 ;
     RECT  6.456 29.123 7.8 31.381 ;
     RECT  3.528 31.909 4.992 32.003 ;
     RECT  5.412 31.955 6.432 36.373 ;
     RECT  2.712 34.165 4.176 34.931 ;
     RECT  2.712 34.931 5.1 35.605 ;
     RECT  2.712 35.605 3.696 36.611 ;
     RECT  3.72 35.605 5.1 36.611 ;
     RECT  6.6 37.043 7.8 38.005 ;
     RECT  5.412 37.091 6.576 38.149 ;
     RECT  2.712 38.677 3.936 40.261 ;
     RECT  3.96 38.677 5.1 40.595 ;
     RECT  5.412 40.163 6.48 44.965 ;
     RECT  6.504 41.075 7.488 42.997 ;
     RECT  2.712 42.323 3.432 43.285 ;
     RECT  3.672 43.285 5.1 43.955 ;
     RECT  8.112 43.861 9.216 49.189 ;
     RECT  9.24 43.861 10.5 49.235 ;
     RECT  2.712 43.955 5.1 44.341 ;
     RECT  2.712 44.341 3.888 45.203 ;
     RECT  3.912 44.341 5.1 44.965 ;
     RECT  3.96 44.965 5.1 45.731 ;
     RECT  2.712 45.203 3.936 45.731 ;
     RECT  6.504 45.635 7.8 46.597 ;
     RECT  2.712 45.731 5.1 46.645 ;
     RECT  6.6 46.597 7.8 47.269 ;
     RECT  5.412 46.643 6.48 50.243 ;
     RECT  2.712 46.645 3.888 46.835 ;
     RECT  3.912 46.645 5.1 46.835 ;
     RECT  6.6 47.269 7.68 48.179 ;
     RECT  6.6 48.179 7.8 50.243 ;
     RECT  9.096 49.235 10.5 58.645 ;
     RECT  5.412 50.243 7.8 50.293 ;
     RECT  5.412 50.293 6.816 50.771 ;
     RECT  5.412 50.771 7.8 51.925 ;
     RECT  5.412 51.925 7.632 52.213 ;
     RECT  5.412 52.213 6.816 52.357 ;
     RECT  5.412 52.357 6.432 52.547 ;
     RECT  5.412 52.547 6.816 52.789 ;
     RECT  5.544 52.789 6.816 53.075 ;
     RECT  6.216 54.901 7.632 55.141 ;
     RECT  4.512 56.051 5.1 57.061 ;
     RECT  2.712 57.061 4.224 58.115 ;
     RECT  2.712 58.115 5.1 59.029 ;
     RECT  9.192 58.645 10.5 59.699 ;
     RECT  6.216 58.739 7.632 59.027 ;
     RECT  2.712 59.029 3.984 60.419 ;
     RECT  4.008 59.029 5.1 60.419 ;
     RECT  9.096 59.699 10.5 62.387 ;
     RECT  6.264 61.045 7.632 61.619 ;
     RECT  5.784 61.619 7.632 62.197 ;
     RECT  5.784 62.197 6.816 62.915 ;
     RECT  2.712 63.253 4.128 65.459 ;
     RECT  5.412 63.875 5.544 64.981 ;
     RECT  2.712 65.459 3.24 66.661 ;
  END
END qwen_glue_v508
END LIBRARY
